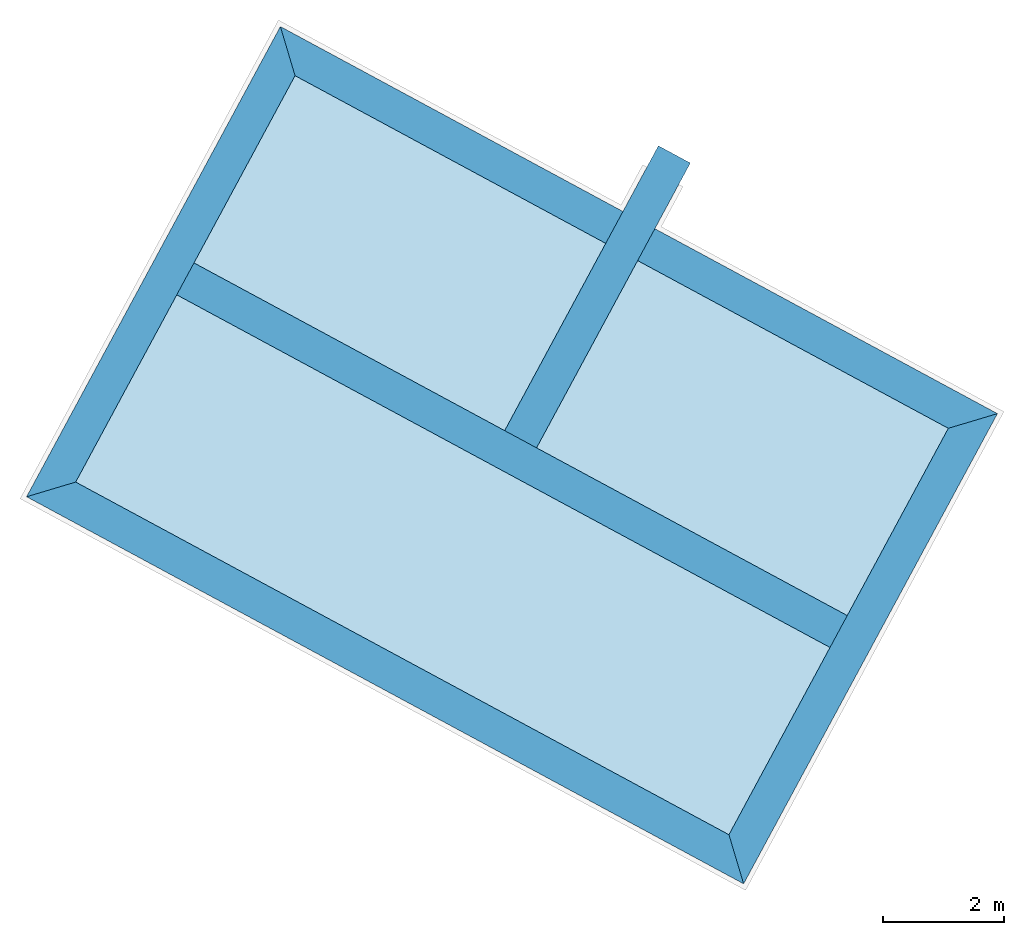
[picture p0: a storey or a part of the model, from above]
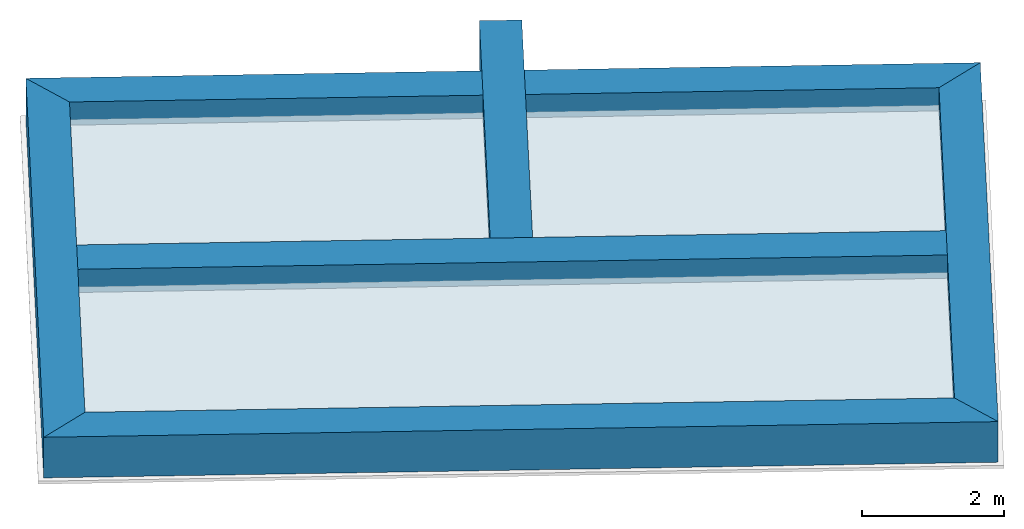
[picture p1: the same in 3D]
Properties of the parts of a building model (IFC2X3), part 1 of 3

# File
Description: ViewDefinition [CoordinationView_V2.0], Option [Elements to export: Visible elements (on all stories)], Option [Partial Structure Display: Entire Model], Option [IFC Domain: All], Option [Structural Function: All Elements], Option [Convert Grid elements: On], Option [Convert IFC Annotations and Archicad 2D elements: Off], Option [Convert 2D symbols of Doors and Windows: Off], Option [Export geometries that Participates in Collision Detection only: Off], Option [Split complex elements: Off], Option [Material Preservation: Never explode], Option [Elements in Solid Element Operations: BRep], Option [Elements with junctions: BRep], Option [IFC Model position: Survey Point and Project Origin], Option [Curtain Wall export mode: Single Element], Option [Railing export mode: Single Element], Option [Stair export mode: Single Element], Option [Properties To Export: All properties], Option [Space containment: Off], Option [Geometry to type objects: Off], Option [Element Properties: Off], Option [Building Material Properties: On], Option [Element Parameters: Off], Option [Component Parameters: Off], Option [IFC Base Quantities: Off], Option [Door Window Parameters: On], Option [IFC Space boundaries: Off], Option [Archicad Zone Categories as IFC Space classification data: Off], Option [Element Classifications: On]
File name: I:\_PROJEKT\PQRS\SIWH_18\05_Ausführungsplanung\02 CAD\06 IFC-Modelle\02 TGA\230327\SIWH_18_2302327 - neu.ifc
Time: 2023-03-27T13:30:50
Author: Kohlrausch Stephan
Organization: Gruppe GME Architekten BDA
Written by: DDS_IFC v3.0
Made in: IFC file generated by Graphisoft Archicad 26.0.0 GER FULL Windows version (IFC add-on version: 4022 GER FULL).
Authorization: Kohlrausch Stephan

# IfcProject, Neubau eines Einfamilienhauses
Description: Katrepeler Landstraße 70A

# IfcSite, Gelände
RefLatitude: 52, 31, 0, 0; RefLongitude: 13, 24, 0, 0; RefElevation: 4.65 m

# IfcBuildingStorey (5)
In: Gebäude
Name | Elevation (m)
Erdgeschoss | 0
Staffelgeschoss | 4.55
Gründung | -3.68
Dachaufsicht | 7.905
Kellergeschoss | -2.98

# IfcBuildingElementProxy: 1-Flügelfenster 22, Fenster-016
In: Kellergeschoss
AC_Pset_RenovationAndPhasing - Renovation Status: Existing

# IfcBuildingElementProxy: ALLGEMEIN - BAUTEIL (404)
In: Staffelgeschoss
Material: ALLGEMEIN - BAUTEIL
Material Properties - ALLGEMEIN - BAUTEIL, ThermalConductivity: 0.13; ALLGEMEIN - BAUTEIL, SpecificHeatCapacity: 1600 J/kg/K; ALLGEMEIN - BAUTEIL, MassDensity: 500 kg/m3; ALLGEMEIN - BAUTEIL, Embodied Energy: 13.1 (MJ/kg); ALLGEMEIN - BAUTEIL, Embodied Carbon: 0.64 (kgCO₂/kg); ALLGEMEIN - BAUTEIL, Name: ALLGEMEIN - BAUTEIL; ALLGEMEIN - BAUTEIL, Participates in Collision Detection: yes
AC_Pset_RenovationAndPhasing - Renovation Status: Existing

# IfcBuildingElementProxy: ALLGEMEIN - BAUTEIL 50 (3)
In: Staffelgeschoss
Material: ALLGEMEIN - BAUTEIL
AC_Pset_RenovationAndPhasing - Renovation Status: Existing
Material Properties - ALLGEMEIN - BAUTEIL, ThermalConductivity: 0.13; ALLGEMEIN - BAUTEIL, SpecificHeatCapacity: 1600 J/kg/K; ALLGEMEIN - BAUTEIL, MassDensity: 500 kg/m3; ALLGEMEIN - BAUTEIL, Embodied Energy: 13.1 (MJ/kg); ALLGEMEIN - BAUTEIL, Embodied Carbon: 0.64 (kgCO₂/kg); ALLGEMEIN - BAUTEIL, Name: ALLGEMEIN - BAUTEIL; ALLGEMEIN - BAUTEIL, Participates in Collision Detection: yes
Name
I-Wand038
I-Wand039
I-Wand040

# IfcBuildingElementProxy: ALLGEMEIN - BAUTEIL 520, Decke003
In: Erdgeschoss
Material: ALLGEMEIN - BAUTEIL
AC_Pset_RenovationAndPhasing - Renovation Status: Existing
Material Properties - ALLGEMEIN - BAUTEIL, ThermalConductivity: 0.13; ALLGEMEIN - BAUTEIL, SpecificHeatCapacity: 1600 J/kg/K; ALLGEMEIN - BAUTEIL, MassDensity: 500 kg/m3; ALLGEMEIN - BAUTEIL, Embodied Energy: 13.1 (MJ/kg); ALLGEMEIN - BAUTEIL, Embodied Carbon: 0.64 (kgCO₂/kg); ALLGEMEIN - BAUTEIL, Name: ALLGEMEIN - BAUTEIL; ALLGEMEIN - BAUTEIL, Participates in Collision Detection: yes

# IfcBuildingElementProxy: ALLGEMEIN - NIEDRIGE PRIORITÄT 100 (5)
In: Erdgeschoss
Material: ALLGEMEIN - NIEDRIGE PRIORITÄT
AC_Pset_RenovationAndPhasing - Renovation Status: Existing
Material Properties - ALLGEMEIN - NIEDRIGE PRIORITÄT, ThermalConductivity: 0; ALLGEMEIN - NIEDRIGE PRIORITÄT, SpecificHeatCapacity: 0 J/kg/K; ALLGEMEIN - NIEDRIGE PRIORITÄT, MassDensity: 0 kg/m3; ALLGEMEIN - NIEDRIGE PRIORITÄT, Embodied Energy: 0 (MJ/kg); ALLGEMEIN - NIEDRIGE PRIORITÄT, Embodied Carbon: 0 (kgCO₂/kg); ALLGEMEIN - NIEDRIGE PRIORITÄT, Name: ALLGEMEIN - NIEDRIGE PRIORITÄT; ALLGEMEIN - NIEDRIGE PRIORITÄT, Participates in Collision Detection: yes
Name
Decke043
Decke045
Decke047
Decke048
Decke049

# IfcBuildingElementProxy: ALLGEMEIN - NIEDRIGE PRIORITÄT 150, Decke051
In: Erdgeschoss
Material: ALLGEMEIN - NIEDRIGE PRIORITÄT
Material Properties - ALLGEMEIN - NIEDRIGE PRIORITÄT, ThermalConductivity: 0; ALLGEMEIN - NIEDRIGE PRIORITÄT, SpecificHeatCapacity: 0 J/kg/K; ALLGEMEIN - NIEDRIGE PRIORITÄT, MassDensity: 0 kg/m3; ALLGEMEIN - NIEDRIGE PRIORITÄT, Embodied Energy: 0 (MJ/kg); ALLGEMEIN - NIEDRIGE PRIORITÄT, Embodied Carbon: 0 (kgCO₂/kg); ALLGEMEIN - NIEDRIGE PRIORITÄT, Name: ALLGEMEIN - NIEDRIGE PRIORITÄT; ALLGEMEIN - NIEDRIGE PRIORITÄT, Participates in Collision Detection: yes
AC_Pset_RenovationAndPhasing - Renovation Status: Existing

# IfcBuildingElementProxy: ALLGEMEIN - NIEDRIGE PRIORITÄT 182 (2)
In: Erdgeschoss
Material: ALLGEMEIN - NIEDRIGE PRIORITÄT
AC_Pset_RenovationAndPhasing - Renovation Status: Existing
Material Properties - ALLGEMEIN - NIEDRIGE PRIORITÄT, ThermalConductivity: 0; ALLGEMEIN - NIEDRIGE PRIORITÄT, SpecificHeatCapacity: 0 J/kg/K; ALLGEMEIN - NIEDRIGE PRIORITÄT, MassDensity: 0 kg/m3; ALLGEMEIN - NIEDRIGE PRIORITÄT, Embodied Energy: 0 (MJ/kg); ALLGEMEIN - NIEDRIGE PRIORITÄT, Embodied Carbon: 0 (kgCO₂/kg); ALLGEMEIN - NIEDRIGE PRIORITÄT, Name: ALLGEMEIN - NIEDRIGE PRIORITÄT; ALLGEMEIN - NIEDRIGE PRIORITÄT, Participates in Collision Detection: yes
Name
Decke031
Decke042

# IfcBuildingElementProxy: ALLGEMEIN - NIEDRIGE PRIORITÄT 50 (3)
In: Erdgeschoss
Material: ALLGEMEIN - NIEDRIGE PRIORITÄT
AC_Pset_RenovationAndPhasing - Renovation Status: Existing
Material Properties - ALLGEMEIN - NIEDRIGE PRIORITÄT, ThermalConductivity: 0; ALLGEMEIN - NIEDRIGE PRIORITÄT, SpecificHeatCapacity: 0 J/kg/K; ALLGEMEIN - NIEDRIGE PRIORITÄT, MassDensity: 0 kg/m3; ALLGEMEIN - NIEDRIGE PRIORITÄT, Embodied Energy: 0 (MJ/kg); ALLGEMEIN - NIEDRIGE PRIORITÄT, Embodied Carbon: 0 (kgCO₂/kg); ALLGEMEIN - NIEDRIGE PRIORITÄT, Name: ALLGEMEIN - NIEDRIGE PRIORITÄT; ALLGEMEIN - NIEDRIGE PRIORITÄT, Participates in Collision Detection: yes
Name
Decke044
Decke046
Decke050

# IfcBuildingElementProxy: BO | Dämmung 8+Folie+Estrich 7+Fliese 0,5 | 16cm 170 (8)
In: Staffelgeschoss
AC_Pset_RenovationAndPhasing - Renovation Status: Existing
Material Properties - Dämmung, hart EPS, ThermalConductivity: 0.042; Dämmung, hart EPS, SpecificHeatCapacity: 1450 J/kg/K; Dämmung, hart EPS, MassDensity: 15 kg/m3; Dämmung, hart EPS, Embodied Energy: 76 (MJ/kg); Dämmung, hart EPS, Embodied Carbon: 3.18 (kgCO₂/kg); Dämmung, hart EPS, Name: Dämmung, hart EPS; Dämmung, hart EPS, Participates in Collision Detection: yes; Estrich, ThermalConductivity: 0.8; Estrich, SpecificHeatCapacity: 800 J/kg/K; Estrich, MassDensity: 2300 kg/m3; Estrich, Embodied Energy: 0.92 (MJ/kg); Estrich, Embodied Carbon: 0.15 (kgCO₂/kg); Estrich, Name: Estrich; Estrich, Participates in Collision Detection: yes; Kleber, ThermalConductivity: 0.8; Kleber, SpecificHeatCapacity: 800 J/kg/K; Kleber, MassDensity: 2300 kg/m3; Kleber, Embodied Energy: 0.92 (MJ/kg); Kleber, Embodied Carbon: 0.15 (kgCO₂/kg); Kleber, Name: Kleber; Kleber, Participates in Collision Detection: yes; Beton, Leichtbeton, ThermalConductivity: 0.12; Beton, Leichtbeton, SpecificHeatCapacity: 800 J/kg/K; Beton, Leichtbeton, MassDensity: 450 kg/m3; Beton, Leichtbeton, Embodied Energy: 6.2 (MJ/kg); Beton, Leichtbeton, Embodied Carbon: 0.46 (kgCO₂/kg); Beton, Leichtbeton, Name: Beton, Leichtbeton; Beton, Leichtbeton, Participates in Collision Detection: yes
Name | Material
Decke028 | Dämmung, hart EPS, Sperrschicht, Folie, Estrich, Kleber, Beton, Leichtbeton | Material Properties - Sperrschicht, Folie, ThermalConductivity: 0.14; Sperrschicht, Folie, SpecificHeatCapacity: 1000 J/kg/K; Sperrschicht, Folie, MassDensity: 1200 kg/m3; Sperrschicht, Folie, Embodied Energy: 77.2 (MJ/kg); Sperrschicht, Folie, Embodied Carbon: 3.1 (kgCO₂/kg); Sperrschicht, Folie, Name: Sperrschicht, Folie; Sperrschicht, Folie, Participates in Collision Detection: yes
Decke029 | Beton, Leichtbeton, Kleber, Estrich, Dämmung, hart EPS
Decke041 | Beton, Leichtbeton, Kleber, Estrich, Dämmung, hart EPS
Decke055 | Beton, Leichtbeton, Kleber, Estrich, Dämmung, hart EPS
Decke056 | Beton, Leichtbeton, Kleber, Estrich, Dämmung, hart EPS
Decke057 | Beton, Leichtbeton, Kleber, Estrich, Dämmung, hart EPS
Decke058 | Beton, Leichtbeton, Kleber, Estrich, Dämmung, hart EPS
Decke040 | Dämmung, hart EPS, Sperrschicht, Folie, Estrich, Kleber, Beton, Leichtbeton | Material Properties - Sperrschicht, Folie, ThermalConductivity: 0.14; Sperrschicht, Folie, SpecificHeatCapacity: 1000 J/kg/K; Sperrschicht, Folie, MassDensity: 1200 kg/m3; Sperrschicht, Folie, Embodied Energy: 77.2 (MJ/kg); Sperrschicht, Folie, Embodied Carbon: 3.1 (kgCO₂/kg); Sperrschicht, Folie, Name: Sperrschicht, Folie; Sperrschicht, Folie, Participates in Collision Detection: yes

# IfcBuildingElementProxy: Beton, Stahlbeton C30/35 500 (2)
In: Kellergeschoss
Material: Beton, Stahlbeton C30/35
AC_Pset_RenovationAndPhasing - Renovation Status: Existing
Material Properties - Beton, Stahlbeton C30/35, ThermalConductivity: 1.35; Beton, Stahlbeton C30/35, SpecificHeatCapacity: 1000 J/kg/K; Beton, Stahlbeton C30/35, MassDensity: 2000 kg/m3; Beton, Stahlbeton C30/35, Embodied Energy: 0.78 (MJ/kg); Beton, Stahlbeton C30/35, Embodied Carbon: 0.113 (kgCO₂/kg); Beton, Stahlbeton C30/35, Name: Beton, Stahlbeton C30/35; Beton, Stahlbeton C30/35, Participates in Collision Detection: yes
Name
A-Wand038
A-Wand037

# IfcBuildingElementProxy: Beton, WU-Beton 10 (3)
In: Erdgeschoss
Material: Beton, WU-Beton
AC_Pset_RenovationAndPhasing - Renovation Status: Existing
Material Properties - Beton, WU-Beton, ThermalConductivity: 1.7; Beton, WU-Beton, SpecificHeatCapacity: 800 J/kg/K; Beton, WU-Beton, MassDensity: 2300 kg/m3; Beton, WU-Beton, Embodied Energy: 0.88 (MJ/kg); Beton, WU-Beton, Embodied Carbon: 0.132 (kgCO₂/kg); Beton, WU-Beton, Name: Beton, WU-Beton; Beton, WU-Beton, Participates in Collision Detection: yes
Name
Wand-016
Wand-015
Wand-017

# IfcBuildingElementProxy: Eingangstür 02 1 22, Tür-017
In: Erdgeschoss
AC_Pset_RenovationAndPhasing - Renovation Status: Existing

# IfcBuildingElementProxy: Fassadentyp (12)
AC_Pset_RenovationAndPhasing - Renovation Status: Existing
Material Properties - Glas, Normalglas-50% durchlässig, ThermalConductivity: 1.4; Glas, Normalglas-50% durchlässig, SpecificHeatCapacity: 750 J/kg/K; Glas, Normalglas-50% durchlässig, MassDensity: 2200 kg/m3; Glas, Normalglas-50% durchlässig, Embodied Energy: 0.85 (MJ/kg); Glas, Normalglas-50% durchlässig, Embodied Carbon: 0.02 (kgCO₂/kg); Glas, Normalglas-50% durchlässig, Name: Glas, Normalglas-50% durchlässig; Glas, Normalglas-50% durchlässig, Participates in Collision Detection: yes; Metall, Stahl lackiert, ThermalConductivity: 50; Metall, Stahl lackiert, SpecificHeatCapacity: 450 J/kg/K; Metall, Stahl lackiert, MassDensity: 7800 kg/m3; Metall, Stahl lackiert, Embodied Energy: 20.1 (MJ/kg); Metall, Stahl lackiert, Embodied Carbon: 1.46 (kgCO₂/kg); Metall, Stahl lackiert, Name: Metall, Stahl lackiert; Metall, Stahl lackiert, Participates in Collision Detection: yes
Name | In | Material | Metall, Aluminium, ThermalConductivity | Metall, Aluminium, SpecificHeatCapacity (J/kg/K) | Metall, Aluminium, MassDensity (kg/m3) | Metall, Aluminium, Embodied Energy | Metall, Aluminium, Embodied Carbon | Metall, Aluminium, Name | Metall, Aluminium, Participates in Collision Detection
Fassade-006 | Erdgeschoss | Glas, Normalglas-50% durchlässig (2), Metall, Stahl lackiert (8), Metall, Aluminium (2) | 160 | 880 | 2800 | 155 (MJ/kg) | 9.16 (kgCO₂/kg) | Metall, Aluminium | yes
Fassade-006 | Erdgeschoss | Metall, Aluminium (3), Glas, Normalglas-50% durchlässig (2), Metall, Edelstahl, Metall, Stahl lackiert (16) | 160 | 880 | 2800 | 155 (MJ/kg) | 9.16 (kgCO₂/kg) | Metall, Aluminium | yes | Material Properties - Metall, Edelstahl, ThermalConductivity: 17; Metall, Edelstahl, SpecificHeatCapacity: 460 J/kg/K; Metall, Edelstahl, MassDensity: 7900 kg/m3; Metall, Edelstahl, Embodied Energy: 56.7 (MJ/kg); Metall, Edelstahl, Embodied Carbon: 6.15 (kgCO₂/kg); Metall, Edelstahl, Name: Metall, Edelstahl; Metall, Edelstahl, Participates in Collision Detection: yes
Fassade-007 | Erdgeschoss | Glas, Normalglas-50% durchlässig (3), Metall, Aluminium (5), Metall, Edelstahl, Metall, Stahl lackiert (18), Dämmung, hart EPS (2) | 160 | 880 | 2800 | 155 (MJ/kg) | 9.16 (kgCO₂/kg) | Metall, Aluminium | yes | Material Properties - Metall, Edelstahl, ThermalConductivity: 17; Metall, Edelstahl, SpecificHeatCapacity: 460 J/kg/K; Metall, Edelstahl, MassDensity: 7900 kg/m3; Metall, Edelstahl, Embodied Energy: 56.7 (MJ/kg); Metall, Edelstahl, Embodied Carbon: 6.15 (kgCO₂/kg); Metall, Edelstahl, Name: Metall, Edelstahl; Metall, Edelstahl, Participates in Collision Detection: yes; Dämmung, hart EPS, ThermalConductivity: 0.042; Dämmung, hart EPS, SpecificHeatCapacity: 1450 J/kg/K; Dämmung, hart EPS, MassDensity: 15 kg/m3; Dämmung, hart EPS, Embodied Energy: 76 (MJ/kg); Dämmung, hart EPS, Embodied Carbon: 3.18 (kgCO₂/kg); Dämmung, hart EPS, Name: Dämmung, hart EPS; Dämmung, hart EPS, Participates in Collision Detection: yes
Fassade-008 | Erdgeschoss | Glas, Normalglas-50% durchlässig (4), Metall, Stahl lackiert (14), Metall, Aluminium (5), Gummi, Dämmung, hart EPS | 160 | 880 | 2800 | 155 (MJ/kg) | 9.16 (kgCO₂/kg) | Metall, Aluminium | yes | Material Properties - Dämmung, hart EPS, ThermalConductivity: 0.042; Dämmung, hart EPS, SpecificHeatCapacity: 1450 J/kg/K; Dämmung, hart EPS, MassDensity: 15 kg/m3; Dämmung, hart EPS, Embodied Energy: 76 (MJ/kg); Dämmung, hart EPS, Embodied Carbon: 3.18 (kgCO₂/kg); Dämmung, hart EPS, Name: Dämmung, hart EPS; Dämmung, hart EPS, Participates in Collision Detection: yes; Gummi, ThermalConductivity: 0.17; Gummi, SpecificHeatCapacity: 1400 J/kg/K; Gummi, MassDensity: 1200 kg/m3; Gummi, Embodied Energy: 110 (MJ/kg); Gummi, Embodied Carbon: 3.8 (kgCO₂/kg); Gummi, Name: Gummi; Gummi, Participates in Collision Detection: yes
Fassade-006 | Erdgeschoss | Glas, Normalglas-50% durchlässig (3), Metall, Stahl lackiert (18), Metall, Aluminium (4) | 160 | 880 | 2800 | 155 (MJ/kg) | 9.16 (kgCO₂/kg) | Metall, Aluminium | yes
Fassade-007 | Erdgeschoss | Metall, Aluminium (4), Glas, Normalglas-50% durchlässig (2), Metall, Edelstahl (2), Dämmung, hart EPS (2), Metall, Stahl lackiert (14) | 160 | 880 | 2800 | 155 (MJ/kg) | 9.16 (kgCO₂/kg) | Metall, Aluminium | yes | Material Properties - Metall, Edelstahl, ThermalConductivity: 17; Metall, Edelstahl, SpecificHeatCapacity: 460 J/kg/K; Metall, Edelstahl, MassDensity: 7900 kg/m3; Metall, Edelstahl, Embodied Energy: 56.7 (MJ/kg); Metall, Edelstahl, Embodied Carbon: 6.15 (kgCO₂/kg); Metall, Edelstahl, Name: Metall, Edelstahl; Metall, Edelstahl, Participates in Collision Detection: yes; Dämmung, hart EPS, ThermalConductivity: 0.042; Dämmung, hart EPS, SpecificHeatCapacity: 1450 J/kg/K; Dämmung, hart EPS, MassDensity: 15 kg/m3; Dämmung, hart EPS, Embodied Energy: 76 (MJ/kg); Dämmung, hart EPS, Embodied Carbon: 3.18 (kgCO₂/kg); Dämmung, hart EPS, Name: Dämmung, hart EPS; Dämmung, hart EPS, Participates in Collision Detection: yes
Fassade-008 | Staffelgeschoss | Glas, Normalglas-50% durchlässig (27), Metall, Aluminium (28), Metall, Edelstahl, Metall, Stahl lackiert (74), Dämmung, hart EPS (2) | 160 | 880 | 2800 | 155 (MJ/kg) | 9.16 (kgCO₂/kg) | Metall, Aluminium | yes | Material Properties - Metall, Edelstahl, ThermalConductivity: 17; Metall, Edelstahl, SpecificHeatCapacity: 460 J/kg/K; Metall, Edelstahl, MassDensity: 7900 kg/m3; Metall, Edelstahl, Embodied Energy: 56.7 (MJ/kg); Metall, Edelstahl, Embodied Carbon: 6.15 (kgCO₂/kg); Metall, Edelstahl, Name: Metall, Edelstahl; Metall, Edelstahl, Participates in Collision Detection: yes; Dämmung, hart EPS, ThermalConductivity: 0.042; Dämmung, hart EPS, SpecificHeatCapacity: 1450 J/kg/K; Dämmung, hart EPS, MassDensity: 15 kg/m3; Dämmung, hart EPS, Embodied Energy: 76 (MJ/kg); Dämmung, hart EPS, Embodied Carbon: 3.18 (kgCO₂/kg); Dämmung, hart EPS, Name: Dämmung, hart EPS; Dämmung, hart EPS, Participates in Collision Detection: yes
3 x Fassade-006 | Staffelgeschoss | Glas, Normalglas-50% durchlässig, Metall, Stahl lackiert (6)
Fassade-008 | Staffelgeschoss | Glas, Normalglas-50% durchlässig (2), Metall, Aluminium (2), Metall, Edelstahl, Metall, Stahl lackiert (15), Dämmung, hart EPS | 160 | 880 | 2800 | 155 (MJ/kg) | 9.16 (kgCO₂/kg) | Metall, Aluminium | yes | Material Properties - Metall, Edelstahl, ThermalConductivity: 17; Metall, Edelstahl, SpecificHeatCapacity: 460 J/kg/K; Metall, Edelstahl, MassDensity: 7900 kg/m3; Metall, Edelstahl, Embodied Energy: 56.7 (MJ/kg); Metall, Edelstahl, Embodied Carbon: 6.15 (kgCO₂/kg); Metall, Edelstahl, Name: Metall, Edelstahl; Metall, Edelstahl, Participates in Collision Detection: yes; Dämmung, hart EPS, ThermalConductivity: 0.042; Dämmung, hart EPS, SpecificHeatCapacity: 1450 J/kg/K; Dämmung, hart EPS, MassDensity: 15 kg/m3; Dämmung, hart EPS, Embodied Energy: 76 (MJ/kg); Dämmung, hart EPS, Embodied Carbon: 3.18 (kgCO₂/kg); Dämmung, hart EPS, Name: Dämmung, hart EPS; Dämmung, hart EPS, Participates in Collision Detection: yes
Fassade-006 | Staffelgeschoss | Glas, Normalglas-50% durchlässig (3), Metall, Aluminium (3), Metall, Edelstahl, Metall, Stahl lackiert (15), Dämmung, hart EPS | 160 | 880 | 2800 | 155 (MJ/kg) | 9.16 (kgCO₂/kg) | Metall, Aluminium | yes | Material Properties - Metall, Edelstahl, ThermalConductivity: 17; Metall, Edelstahl, SpecificHeatCapacity: 460 J/kg/K; Metall, Edelstahl, MassDensity: 7900 kg/m3; Metall, Edelstahl, Embodied Energy: 56.7 (MJ/kg); Metall, Edelstahl, Embodied Carbon: 6.15 (kgCO₂/kg); Metall, Edelstahl, Name: Metall, Edelstahl; Metall, Edelstahl, Participates in Collision Detection: yes; Dämmung, hart EPS, ThermalConductivity: 0.042; Dämmung, hart EPS, SpecificHeatCapacity: 1450 J/kg/K; Dämmung, hart EPS, MassDensity: 15 kg/m3; Dämmung, hart EPS, Embodied Energy: 76 (MJ/kg); Dämmung, hart EPS, Embodied Carbon: 3.18 (kgCO₂/kg); Dämmung, hart EPS, Name: Dämmung, hart EPS; Dämmung, hart EPS, Participates in Collision Detection: yes

# IfcBuildingElementProxy: Flachbildfernseher 22, Objekt-0064
In: Erdgeschoss
AC_Pset_RenovationAndPhasing - Renovation Status: Existing

# IfcBuildingElementProxy: Geländerart (5)
In: Staffelgeschoss
AC_Pset_RenovationAndPhasing - Renovation Status: Existing
Material Properties - Metall, Stahl lackiert, ThermalConductivity: 50; Metall, Stahl lackiert, SpecificHeatCapacity: 450 J/kg/K; Metall, Stahl lackiert, MassDensity: 7800 kg/m3; Metall, Stahl lackiert, Embodied Energy: 20.1 (MJ/kg); Metall, Stahl lackiert, Embodied Carbon: 1.46 (kgCO₂/kg); Metall, Stahl lackiert, Name: Metall, Stahl lackiert; Metall, Stahl lackiert, Participates in Collision Detection: yes
Name | Material | Glas, Normalglas-50% durchlässig, ThermalConductivity | Glas, Normalglas-50% durchlässig, SpecificHeatCapacity (J/kg/K) | Glas, Normalglas-50% durchlässig, MassDensity (kg/m3) | Glas, Normalglas-50% durchlässig, Embodied Energy | Glas, Normalglas-50% durchlässig, Embodied Carbon | Glas, Normalglas-50% durchlässig, Name | Glas, Normalglas-50% durchlässig, Participates in Collision Detection
4 x Geländer-005 | Metall, Stahl lackiert (5), Glas, Normalglas-50% durchlässig | 1.4 | 750 | 2200 | 0.85 (MJ/kg) | 0.02 (kgCO₂/kg) | Glas, Normalglas-50% durchlässig | yes
Geländer-005 | Metall, Stahl lackiert (5), Glas, Normalglas | Material Properties - Glas, Normalglas, ThermalConductivity: 1.4; Glas, Normalglas, SpecificHeatCapacity: 750 J/kg/K; Glas, Normalglas, MassDensity: 2200 kg/m3; Glas, Normalglas, Embodied Energy: 0.85 (MJ/kg); Glas, Normalglas, Embodied Carbon: 0.02 (kgCO₂/kg); Glas, Normalglas, Name: Glas, Normalglas; Glas, Normalglas, Participates in Collision Detection: yes

# IfcBuildingElementProxy: Gipskarton 15 (3)
Material: Gipskarton
AC_Pset_RenovationAndPhasing - Renovation Status: Existing
Material Properties - Gipskarton, ThermalConductivity: 0.25; Gipskarton, SpecificHeatCapacity: 1000 J/kg/K; Gipskarton, MassDensity: 900 kg/m3; Gipskarton, Embodied Energy: 6.75 (MJ/kg); Gipskarton, Embodied Carbon: 0.39 (kgCO₂/kg); Gipskarton, Name: Gipskarton; Gipskarton, Participates in Collision Detection: yes
Name | In
Decke001 | Erdgeschoss
Decke007 | Erdgeschoss
Decke002 | Staffelgeschoss

# IfcBuildingElementProxy: Glas, Normalglas 10 (6)
Material: Glas, Normalglas
AC_Pset_RenovationAndPhasing - Renovation Status: Existing
Material Properties - Glas, Normalglas, ThermalConductivity: 1.4; Glas, Normalglas, SpecificHeatCapacity: 750 J/kg/K; Glas, Normalglas, MassDensity: 2200 kg/m3; Glas, Normalglas, Embodied Energy: 0.85 (MJ/kg); Glas, Normalglas, Embodied Carbon: 0.02 (kgCO₂/kg); Glas, Normalglas, Name: Glas, Normalglas; Glas, Normalglas, Participates in Collision Detection: yes
Name | In
I-Wand033 | Erdgeschoss
I-Wand035 | Erdgeschoss
I-Wand036 | Erdgeschoss
I-Wand031 | Staffelgeschoss
I-Wand032 | Staffelgeschoss
I-Wand037 | Staffelgeschoss

# IfcBuildingElementProxy: Holz, Treppenstufe 966, Decke000
In: Erdgeschoss
Material: Holz, Treppenstufe
AC_Pset_RenovationAndPhasing - Renovation Status: Existing
Material Properties - Holz, Treppenstufe, ThermalConductivity: 0.09; Holz, Treppenstufe, SpecificHeatCapacity: 1600 J/kg/K; Holz, Treppenstufe, MassDensity: 300 kg/m3; Holz, Treppenstufe, Embodied Energy: 11.9 (MJ/kg); Holz, Treppenstufe, Embodied Carbon: 0.52 (kgCO₂/kg); Holz, Treppenstufe, Name: Holz, Treppenstufe; Holz, Treppenstufe, Participates in Collision Detection: yes

# IfcBuildingElementProxy: Kamin freistehend 22 (2)
In: Staffelgeschoss
AC_Pset_RenovationAndPhasing - Renovation Status: Existing

# IfcBuildingElementProxy: Kleiderschrank 22 (2)
In: Erdgeschoss
AC_Pset_RenovationAndPhasing - Renovation Status: Existing

# IfcBuildingElementProxy: MW Kalksandstein 175, I-Wand017
In: Staffelgeschoss
Material: MW Kalksandstein
Material Properties - MW Kalksandstein, ThermalConductivity: 0.93; MW Kalksandstein, SpecificHeatCapacity: 840 J/kg/K; MW Kalksandstein, MassDensity: 1800 kg/m3; MW Kalksandstein, Embodied Energy: 1.2 (MJ/kg); MW Kalksandstein, Embodied Carbon: 0.07 (kgCO₂/kg); MW Kalksandstein, Name: MW Kalksandstein; MW Kalksandstein, Participates in Collision Detection: yes
AC_Pset_RenovationAndPhasing - Renovation Status: Existing

# IfcBuildingElementProxy: MW Kalksandstein 500, A-Wand036
In: Kellergeschoss
Material: MW Kalksandstein
AC_Pset_RenovationAndPhasing - Renovation Status: Existing
Material Properties - MW Kalksandstein, ThermalConductivity: 0.93; MW Kalksandstein, SpecificHeatCapacity: 840 J/kg/K; MW Kalksandstein, MassDensity: 1800 kg/m3; MW Kalksandstein, Embodied Energy: 1.2 (MJ/kg); MW Kalksandstein, Embodied Carbon: 0.07 (kgCO₂/kg); MW Kalksandstein, Name: MW Kalksandstein; MW Kalksandstein, Participates in Collision Detection: yes

# IfcBuildingElementProxy: Metall, Edelstahl D152 (10)
Material: Metall, Edelstahl
AC_Pset_RenovationAndPhasing - Renovation Status: Existing
Material Properties - Metall, Edelstahl, ThermalConductivity: 17; Metall, Edelstahl, SpecificHeatCapacity: 460 J/kg/K; Metall, Edelstahl, MassDensity: 7900 kg/m3; Metall, Edelstahl, Embodied Energy: 56.7 (MJ/kg); Metall, Edelstahl, Embodied Carbon: 6.15 (kgCO₂/kg); Metall, Edelstahl, Name: Metall, Edelstahl; Metall, Edelstahl, Participates in Collision Detection: yes
Name | In
5 x Stütze-003 | Erdgeschoss
5 x Stütze-003 | Staffelgeschoss

# IfcBuildingElementProxy: Metall, Edelstahl-Stütze D152 (4)
In: Erdgeschoss
Material: Metall, Edelstahl-Stütze
AC_Pset_RenovationAndPhasing - Renovation Status: Existing
Material Properties - Metall, Edelstahl-Stütze, ThermalConductivity: 17; Metall, Edelstahl-Stütze, SpecificHeatCapacity: 460 J/kg/K; Metall, Edelstahl-Stütze, MassDensity: 7900 kg/m3; Metall, Edelstahl-Stütze, Embodied Energy: 56.7 (MJ/kg); Metall, Edelstahl-Stütze, Embodied Carbon: 6.15 (kgCO₂/kg); Metall, Edelstahl-Stütze, Name: Metall, Edelstahl-Stütze; Metall, Edelstahl-Stütze, Participates in Collision Detection: yes

# IfcBuildingElementProxy: Metall, Stahl lackiert D152 (8)
In: Staffelgeschoss
Material: Metall, Stahl lackiert
AC_Pset_RenovationAndPhasing - Renovation Status: Existing
Material Properties - Metall, Stahl lackiert, ThermalConductivity: 50; Metall, Stahl lackiert, SpecificHeatCapacity: 450 J/kg/K; Metall, Stahl lackiert, MassDensity: 7800 kg/m3; Metall, Stahl lackiert, Embodied Energy: 20.1 (MJ/kg); Metall, Stahl lackiert, Embodied Carbon: 1.46 (kgCO₂/kg); Metall, Stahl lackiert, Name: Metall, Stahl lackiert; Metall, Stahl lackiert, Participates in Collision Detection: yes
Name
4 x Stütze-003
4 x Stütze-004

# IfcBuildingElementProxy: Schiebetür 02 1 22 (2)
In: Staffelgeschoss
AC_Pset_RenovationAndPhasing - Renovation Status: Existing

# IfcBuildingElementProxy: Schiebetür 02 1-Fl 26, Tür-017
In: Staffelgeschoss
AC_Pset_RenovationAndPhasing - Renovation Status: Existing

# IfcBuildingElementProxy: Schreibtisch 22, Objekt-0068
In: Staffelgeschoss
AC_Pset_RenovationAndPhasing - Renovation Status: Existing

# IfcBuildingElementProxy: Sektionaltor 22, Tür-016
In: Erdgeschoss
AC_Pset_RenovationAndPhasing - Renovation Status: Existing

# IfcBuildingElementProxy: Sofa Set 01 17 (4)
In: Erdgeschoss
AC_Pset_RenovationAndPhasing - Renovation Status: Existing

# IfcBuildingElementProxy: Teleskoptür 22 (2)
AC_Pset_RenovationAndPhasing - Renovation Status: Existing
Name | In
Tür-011 | Erdgeschoss
Tür-011 | Staffelgeschoss

# IfcBuildingElementProxy: Treppentyp (2)
AC_Pset_RenovationAndPhasing - Renovation Status: Existing
Name | In | Material
Treppe-001 | Kellergeschoss | ALLGEMEIN - BAUTEIL | Material Properties - ALLGEMEIN - BAUTEIL, ThermalConductivity: 0.13; ALLGEMEIN - BAUTEIL, SpecificHeatCapacity: 1600 J/kg/K; ALLGEMEIN - BAUTEIL, MassDensity: 500 kg/m3; ALLGEMEIN - BAUTEIL, Embodied Energy: 13.1 (MJ/kg); ALLGEMEIN - BAUTEIL, Embodied Carbon: 0.64 (kgCO₂/kg); ALLGEMEIN - BAUTEIL, Name: ALLGEMEIN - BAUTEIL; ALLGEMEIN - BAUTEIL, Participates in Collision Detection: yes
Treppe-001 | Erdgeschoss | Metall, Stahl lackiert | Material Properties - Metall, Stahl lackiert, ThermalConductivity: 50; Metall, Stahl lackiert, SpecificHeatCapacity: 450 J/kg/K; Metall, Stahl lackiert, MassDensity: 7800 kg/m3; Metall, Stahl lackiert, Embodied Energy: 20.1 (MJ/kg); Metall, Stahl lackiert, Embodied Carbon: 1.46 (kgCO₂/kg); Metall, Stahl lackiert, Name: Metall, Stahl lackiert; Metall, Stahl lackiert, Participates in Collision Detection: yes

# IfcBuildingElementProxy: Unterschrank Mehrfach-Schublade 22 (4)
In: Erdgeschoss
AC_Pset_RenovationAndPhasing - Renovation Status: Existing

# IfcBuildingElementProxy: WI | KS 11,5+1-seitig Putz 1,5 | 13cm 130 (3)
In: Staffelgeschoss
Material: Verputz, Gips, MW Kalksandstein
AC_Pset_RenovationAndPhasing - Renovation Status: Existing
Material Properties - Verputz, Gips, ThermalConductivity: 0.4; Verputz, Gips, SpecificHeatCapacity: 1000 J/kg/K; Verputz, Gips, MassDensity: 1000 kg/m3; Verputz, Gips, Embodied Energy: 1.6 (MJ/kg); Verputz, Gips, Embodied Carbon: 0.11 (kgCO₂/kg); Verputz, Gips, Name: Verputz, Gips; Verputz, Gips, Participates in Collision Detection: yes; MW Kalksandstein, ThermalConductivity: 0.93; MW Kalksandstein, SpecificHeatCapacity: 840 J/kg/K; MW Kalksandstein, MassDensity: 1800 kg/m3; MW Kalksandstein, Embodied Energy: 1.2 (MJ/kg); MW Kalksandstein, Embodied Carbon: 0.07 (kgCO₂/kg); MW Kalksandstein, Name: MW Kalksandstein; MW Kalksandstein, Participates in Collision Detection: yes
Name
I-Wand018
I-Wand019
I-Wand010

# IfcBuildingElementProxy: Wasser 789, Decke026
In: Erdgeschoss
Material: Wasser
Material Properties - Wasser, ThermalConductivity: 0.6; Wasser, SpecificHeatCapacity: 4200 J/kg/K; Wasser, MassDensity: 1000 kg/m3; Wasser, Embodied Energy: 0.01 (MJ/kg); Wasser, Embodied Carbon: 0.001 (kgCO₂/kg); Wasser, Name: Wasser; Wasser, Participates in Collision Detection: no
AC_Pset_RenovationAndPhasing - Renovation Status: Existing

# IfcBuildingElementProxy: Zargentür 1-Fl 22 (12)
AC_Pset_RenovationAndPhasing - Renovation Status: Existing
Name | In
3 x Tür-017 | Kellergeschoss
6 x Tür-017 | Erdgeschoss
3 x Tür-017 | Staffelgeschoss

# IfcBuildingElementProxy: _SIWH - BO | EG 180, Decke008
In: Erdgeschoss
Material: ALLGEMEIN - BAUTEIL
AC_Pset_RenovationAndPhasing - Renovation Status: Existing
Material Properties - ALLGEMEIN - BAUTEIL, ThermalConductivity: 0.13; ALLGEMEIN - BAUTEIL, SpecificHeatCapacity: 1600 J/kg/K; ALLGEMEIN - BAUTEIL, MassDensity: 500 kg/m3; ALLGEMEIN - BAUTEIL, Embodied Energy: 13.1 (MJ/kg); ALLGEMEIN - BAUTEIL, Embodied Carbon: 0.64 (kgCO₂/kg); ALLGEMEIN - BAUTEIL, Name: ALLGEMEIN - BAUTEIL; ALLGEMEIN - BAUTEIL, Participates in Collision Detection: yes

# IfcBuildingElementProxy: _SIWH - BO | SG 190, Decke005
In: Staffelgeschoss
Material: ALLGEMEIN - BAUTEIL
Material Properties - ALLGEMEIN - BAUTEIL, ThermalConductivity: 0.13; ALLGEMEIN - BAUTEIL, SpecificHeatCapacity: 1600 J/kg/K; ALLGEMEIN - BAUTEIL, MassDensity: 500 kg/m3; ALLGEMEIN - BAUTEIL, Embodied Energy: 13.1 (MJ/kg); ALLGEMEIN - BAUTEIL, Embodied Carbon: 0.64 (kgCO₂/kg); ALLGEMEIN - BAUTEIL, Name: ALLGEMEIN - BAUTEIL; ALLGEMEIN - BAUTEIL, Participates in Collision Detection: yes
AC_Pset_RenovationAndPhasing - Renovation Status: Existing

# IfcColumn: Beton, Stahlbeton C30/35 D450 (2)
In: Erdgeschoss
Classification: Stütze / Pfeiler (Archicad Klassifizierung); Material: Beton, Stahlbeton C30/35
AC_Pset_RenovationAndPhasing - Renovation Status: Existing
Pset_ColumnCommon - IsExternal: no; LoadBearing: yes; Reference: Beton, Stahlbeton C30/35 D450
Material Properties - Beton, Stahlbeton C30/35, ThermalConductivity: 1.35; Beton, Stahlbeton C30/35, SpecificHeatCapacity: 1000 J/kg/K; Beton, Stahlbeton C30/35, MassDensity: 2000 kg/m3; Beton, Stahlbeton C30/35, Embodied Energy: 0.78 (MJ/kg); Beton, Stahlbeton C30/35, Embodied Carbon: 0.113 (kgCO₂/kg); Beton, Stahlbeton C30/35, Name: Beton, Stahlbeton C30/35; Beton, Stahlbeton C30/35, Participates in Collision Detection: yes

# IfcColumn: _SIWH - Außenstütze1 EG 2395 x 400, Stütze-004
In: Erdgeschoss
Classification: Stütze (Archicad Klassifizierung); Material: _SIWH - Beton, Stahlbeton
AC_Pset_RenovationAndPhasing - Renovation Status: Existing
Pset_ColumnCommon - IsExternal: yes; LoadBearing: yes; Reference: _SIWH - Außenstütze1 EG 2395 x 400
Material Properties - _SIWH - Beton, Stahlbeton, ThermalConductivity: 1.35; _SIWH - Beton, Stahlbeton, SpecificHeatCapacity: 1000 J/kg/K; _SIWH - Beton, Stahlbeton, MassDensity: 2000 kg/m3; _SIWH - Beton, Stahlbeton, Embodied Energy: 0.78 (MJ/kg); _SIWH - Beton, Stahlbeton, Embodied Carbon: 0.113 (kgCO₂/kg); _SIWH - Beton, Stahlbeton, Name: _SIWH - Beton, Stahlbeton; _SIWH - Beton, Stahlbeton, Participates in Collision Detection: yes

# IfcColumn: _SIWH - Beton, Stahlbeton 400 x 2200, Stütze-003
In: Erdgeschoss
Classification: Stütze (Archicad Klassifizierung); Material: _SIWH - Beton, Stahlbeton
Pset_ColumnCommon - IsExternal: yes; LoadBearing: yes; Reference: _SIWH - Beton, Stahlbeton 400 x 2200
Material Properties - _SIWH - Beton, Stahlbeton, ThermalConductivity: 1.35; _SIWH - Beton, Stahlbeton, SpecificHeatCapacity: 1000 J/kg/K; _SIWH - Beton, Stahlbeton, MassDensity: 2000 kg/m3; _SIWH - Beton, Stahlbeton, Embodied Energy: 0.78 (MJ/kg); _SIWH - Beton, Stahlbeton, Embodied Carbon: 0.113 (kgCO₂/kg); _SIWH - Beton, Stahlbeton, Name: _SIWH - Beton, Stahlbeton; _SIWH - Beton, Stahlbeton, Participates in Collision Detection: yes
AC_Pset_RenovationAndPhasing - Renovation Status: Existing

# IfcColumn: _SIWH - Beton, Stahlbeton 400 x 400 (11)
In: Erdgeschoss
Classification: Stütze (Archicad Klassifizierung); Material: _SIWH - Beton, Stahlbeton
AC_Pset_RenovationAndPhasing - Renovation Status: Existing
Pset_ColumnCommon - IsExternal: yes; LoadBearing: yes; Reference: _SIWH - Beton, Stahlbeton 400 x 400
Material Properties - _SIWH - Beton, Stahlbeton, ThermalConductivity: 1.35; _SIWH - Beton, Stahlbeton, SpecificHeatCapacity: 1000 J/kg/K; _SIWH - Beton, Stahlbeton, MassDensity: 2000 kg/m3; _SIWH - Beton, Stahlbeton, Embodied Energy: 0.78 (MJ/kg); _SIWH - Beton, Stahlbeton, Embodied Carbon: 0.113 (kgCO₂/kg); _SIWH - Beton, Stahlbeton, Name: _SIWH - Beton, Stahlbeton; _SIWH - Beton, Stahlbeton, Participates in Collision Detection: yes

# IfcCovering: Dämmung, hart Mineralwolle (6)
Classification: Dämmung (Archicad Klassifizierung); Material: Dämmung, hart Mineralwolle
Pset_CoveringCommon - Material: Dämmung, hart Mineralwolle
Material Properties - Dämmung, hart Mineralwolle, ThermalConductivity: 0.036; Dämmung, hart Mineralwolle, SpecificHeatCapacity: 840 J/kg/K; Dämmung, hart Mineralwolle, MassDensity: 115 kg/m3; Dämmung, hart Mineralwolle, Embodied Energy: 21.4 (MJ/kg); Dämmung, hart Mineralwolle, Embodied Carbon: 1.69 (kgCO₂/kg); Dämmung, hart Mineralwolle, Name: Dämmung, hart Mineralwolle; Dämmung, hart Mineralwolle, Participates in Collision Detection: yes
AC_Pset_RenovationAndPhasing - Renovation Status: Existing
Name | In
4 x Freifläche-006 | Staffelgeschoss
Freifläche-005 | Staffelgeschoss
Freifläche-004 | Dachaufsicht

# IfcCovering: _SIWH - Abgehängte Decke Arkade 25 (2)
In: Erdgeschoss
Classification: Abgehängte Decke / Deckenbekleidung (Archicad Klassifizierung); Material: _SIWH - Abgehängte Decke Arkade
Pset_CoveringCommon - Material: _SIWH - Abgehängte Decke Arkade
AC_Pset_RenovationAndPhasing - Renovation Status: Existing
Material Properties - _SIWH - Abgehängte Decke Arkade, ThermalConductivity: 0.13; _SIWH - Abgehängte Decke Arkade, SpecificHeatCapacity: 1600 J/kg/K; _SIWH - Abgehängte Decke Arkade, MassDensity: 500 kg/m3; _SIWH - Abgehängte Decke Arkade, Embodied Energy: 13.1 (MJ/kg); _SIWH - Abgehängte Decke Arkade, Embodied Carbon: 0.64 (kgCO₂/kg); _SIWH - Abgehängte Decke Arkade, Name: _SIWH - Abgehängte Decke Arkade; _SIWH - Abgehängte Decke Arkade, Participates in Collision Detection: yes
Name
Decke016
Decke015

# IfcCovering: _SIWH - Attika1 Achse3 EG 440 x 865, A-Wand054
In: Staffelgeschoss
Classification: Dämmung (Archicad Klassifizierung); Material: _SIWH - Dämmung, weich Mineralwolle, _SIWH - Dämmung, hart Mineralwolle
Pset_CoveringCommon - Material: _SIWH - Attika1 Achse3 EG
AC_Pset_RenovationAndPhasing - Renovation Status: Existing
Material Properties - _SIWH - Dämmung, weich Mineralwolle, ThermalConductivity: 0.037; _SIWH - Dämmung, weich Mineralwolle, SpecificHeatCapacity: 840 J/kg/K; _SIWH - Dämmung, weich Mineralwolle, MassDensity: 40 kg/m3; _SIWH - Dämmung, weich Mineralwolle, Embodied Energy: 14.3 (MJ/kg); _SIWH - Dämmung, weich Mineralwolle, Embodied Carbon: 1.08 (kgCO₂/kg); _SIWH - Dämmung, weich Mineralwolle, Name: _SIWH - Dämmung, weich Mineralwolle; _SIWH - Dämmung, weich Mineralwolle, Participates in Collision Detection: yes; _SIWH - Dämmung, hart Mineralwolle, ThermalConductivity: 0.036; _SIWH - Dämmung, hart Mineralwolle, SpecificHeatCapacity: 840 J/kg/K; _SIWH - Dämmung, hart Mineralwolle, MassDensity: 115 kg/m3; _SIWH - Dämmung, hart Mineralwolle, Embodied Energy: 21.4 (MJ/kg); _SIWH - Dämmung, hart Mineralwolle, Embodied Carbon: 1.69 (kgCO₂/kg); _SIWH - Dämmung, hart Mineralwolle, Name: _SIWH - Dämmung, hart Mineralwolle; _SIWH - Dämmung, hart Mineralwolle, Participates in Collision Detection: yes

# IfcCovering: _SIWH - Attika1 AchseB EG 440 x 865 (2)
In: Staffelgeschoss
Classification: Dämmung (Archicad Klassifizierung); Material: _SIWH - Dämmung, weich Mineralwolle, _SIWH - Dämmung, hart Mineralwolle
Pset_CoveringCommon - Material: _SIWH - Attika1 AchseB EG
AC_Pset_RenovationAndPhasing - Renovation Status: Existing
Material Properties - _SIWH - Dämmung, weich Mineralwolle, ThermalConductivity: 0.037; _SIWH - Dämmung, weich Mineralwolle, SpecificHeatCapacity: 840 J/kg/K; _SIWH - Dämmung, weich Mineralwolle, MassDensity: 40 kg/m3; _SIWH - Dämmung, weich Mineralwolle, Embodied Energy: 14.3 (MJ/kg); _SIWH - Dämmung, weich Mineralwolle, Embodied Carbon: 1.08 (kgCO₂/kg); _SIWH - Dämmung, weich Mineralwolle, Name: _SIWH - Dämmung, weich Mineralwolle; _SIWH - Dämmung, weich Mineralwolle, Participates in Collision Detection: yes; _SIWH - Dämmung, hart Mineralwolle, ThermalConductivity: 0.036; _SIWH - Dämmung, hart Mineralwolle, SpecificHeatCapacity: 840 J/kg/K; _SIWH - Dämmung, hart Mineralwolle, MassDensity: 115 kg/m3; _SIWH - Dämmung, hart Mineralwolle, Embodied Energy: 21.4 (MJ/kg); _SIWH - Dämmung, hart Mineralwolle, Embodied Carbon: 1.69 (kgCO₂/kg); _SIWH - Dämmung, hart Mineralwolle, Name: _SIWH - Dämmung, hart Mineralwolle; _SIWH - Dämmung, hart Mineralwolle, Participates in Collision Detection: yes
Name
A-Wand057
A-Wand059

# IfcCovering: _SIWH - Attika2 Achse3 EG 440 x 585, A-Wand056
In: Staffelgeschoss
Classification: Dämmung (Archicad Klassifizierung); Material: _SIWH - Dämmung, weich Mineralwolle, _SIWH - Dämmung, hart Mineralwolle
Pset_CoveringCommon - Material: _SIWH - Attika2 Achse3 EG
Material Properties - _SIWH - Dämmung, weich Mineralwolle, ThermalConductivity: 0.037; _SIWH - Dämmung, weich Mineralwolle, SpecificHeatCapacity: 840 J/kg/K; _SIWH - Dämmung, weich Mineralwolle, MassDensity: 40 kg/m3; _SIWH - Dämmung, weich Mineralwolle, Embodied Energy: 14.3 (MJ/kg); _SIWH - Dämmung, weich Mineralwolle, Embodied Carbon: 1.08 (kgCO₂/kg); _SIWH - Dämmung, weich Mineralwolle, Name: _SIWH - Dämmung, weich Mineralwolle; _SIWH - Dämmung, weich Mineralwolle, Participates in Collision Detection: yes; _SIWH - Dämmung, hart Mineralwolle, ThermalConductivity: 0.036; _SIWH - Dämmung, hart Mineralwolle, SpecificHeatCapacity: 840 J/kg/K; _SIWH - Dämmung, hart Mineralwolle, MassDensity: 115 kg/m3; _SIWH - Dämmung, hart Mineralwolle, Embodied Energy: 21.4 (MJ/kg); _SIWH - Dämmung, hart Mineralwolle, Embodied Carbon: 1.69 (kgCO₂/kg); _SIWH - Dämmung, hart Mineralwolle, Name: _SIWH - Dämmung, hart Mineralwolle; _SIWH - Dämmung, hart Mineralwolle, Participates in Collision Detection: yes
AC_Pset_RenovationAndPhasing - Renovation Status: Existing

# IfcCovering: _SIWH - Attika3 Achse3 EG 260 x 385, A-Wand055
In: Staffelgeschoss
Classification: Dämmung (Archicad Klassifizierung); Material: _SIWH - Dämmung, hart Mineralwolle
Pset_CoveringCommon - Material: _SIWH - Attika3 Achse3 EG
AC_Pset_RenovationAndPhasing - Renovation Status: Existing
Material Properties - _SIWH - Dämmung, hart Mineralwolle, ThermalConductivity: 0.036; _SIWH - Dämmung, hart Mineralwolle, SpecificHeatCapacity: 840 J/kg/K; _SIWH - Dämmung, hart Mineralwolle, MassDensity: 115 kg/m3; _SIWH - Dämmung, hart Mineralwolle, Embodied Energy: 21.4 (MJ/kg); _SIWH - Dämmung, hart Mineralwolle, Embodied Carbon: 1.69 (kgCO₂/kg); _SIWH - Dämmung, hart Mineralwolle, Name: _SIWH - Dämmung, hart Mineralwolle; _SIWH - Dämmung, hart Mineralwolle, Participates in Collision Detection: yes

# IfcCovering: _SIWH - Attika4 Achse3 EG 320 x 385, A-Wand058
In: Staffelgeschoss
Classification: Dämmung (Archicad Klassifizierung); Material: _SIWH - Dämmung, hart Mineralwolle
Pset_CoveringCommon - Material: _SIWH - Attika4 Achse3 EG
Material Properties - _SIWH - Dämmung, hart Mineralwolle, ThermalConductivity: 0.036; _SIWH - Dämmung, hart Mineralwolle, SpecificHeatCapacity: 840 J/kg/K; _SIWH - Dämmung, hart Mineralwolle, MassDensity: 115 kg/m3; _SIWH - Dämmung, hart Mineralwolle, Embodied Energy: 21.4 (MJ/kg); _SIWH - Dämmung, hart Mineralwolle, Embodied Carbon: 1.69 (kgCO₂/kg); _SIWH - Dämmung, hart Mineralwolle, Name: _SIWH - Dämmung, hart Mineralwolle; _SIWH - Dämmung, hart Mineralwolle, Participates in Collision Detection: yes
AC_Pset_RenovationAndPhasing - Renovation Status: Existing

# IfcCovering: _SIWH - Attikablech1 Achse3+B EG 660 x 115 (2)
In: Staffelgeschoss
Classification: Dachdeckung (Archicad Klassifizierung)
Pset_CoveringCommon - Material: _SIWH - Attikablech1 Achse3+B EG
AC_Pset_RenovationAndPhasing - Renovation Status: Existing
Material Properties - _SIWH - Metall, Aluminium, ThermalConductivity: 160; _SIWH - Metall, Aluminium, SpecificHeatCapacity: 880 J/kg/K; _SIWH - Metall, Aluminium, MassDensity: 2800 kg/m3; _SIWH - Metall, Aluminium, Embodied Energy: 155 (MJ/kg); _SIWH - Metall, Aluminium, Embodied Carbon: 9.16 (kgCO₂/kg); _SIWH - Metall, Aluminium, Name: _SIWH - Metall, Aluminium; _SIWH - Metall, Aluminium, Participates in Collision Detection: yes; _SIWH - Holz, Bauholz, ThermalConductivity: 0.13; _SIWH - Holz, Bauholz, SpecificHeatCapacity: 1600 J/kg/K; _SIWH - Holz, Bauholz, MassDensity: 500 kg/m3; _SIWH - Holz, Bauholz, Embodied Energy: 6.95 (MJ/kg); _SIWH - Holz, Bauholz, Embodied Carbon: 0.29 (kgCO₂/kg); _SIWH - Holz, Bauholz, Name: _SIWH - Holz, Bauholz; _SIWH - Holz, Bauholz, Participates in Collision Detection: yes
Name | Material
Wand-028 | _SIWH - Metall, Aluminium, _SIWH - Holz, Bauholz
Wand-028 | _SIWH - Holz, Bauholz, _SIWH - Metall, Aluminium

# IfcCovering: _SIWH - Attikablech3 Achse3+4' EG 380 x 92 (2)
In: Staffelgeschoss
Classification: Dachdeckung (Archicad Klassifizierung); Material: _SIWH - Metall, Aluminium, _SIWH - Holz, Bauholz
Pset_CoveringCommon - Material: _SIWH - Attikablech3 Achse3+4' EG
AC_Pset_RenovationAndPhasing - Renovation Status: Existing
Material Properties - _SIWH - Metall, Aluminium, ThermalConductivity: 160; _SIWH - Metall, Aluminium, SpecificHeatCapacity: 880 J/kg/K; _SIWH - Metall, Aluminium, MassDensity: 2800 kg/m3; _SIWH - Metall, Aluminium, Embodied Energy: 155 (MJ/kg); _SIWH - Metall, Aluminium, Embodied Carbon: 9.16 (kgCO₂/kg); _SIWH - Metall, Aluminium, Name: _SIWH - Metall, Aluminium; _SIWH - Metall, Aluminium, Participates in Collision Detection: yes; _SIWH - Holz, Bauholz, ThermalConductivity: 0.13; _SIWH - Holz, Bauholz, SpecificHeatCapacity: 1600 J/kg/K; _SIWH - Holz, Bauholz, MassDensity: 500 kg/m3; _SIWH - Holz, Bauholz, Embodied Energy: 6.95 (MJ/kg); _SIWH - Holz, Bauholz, Embodied Carbon: 0.29 (kgCO₂/kg); _SIWH - Holz, Bauholz, Name: _SIWH - Holz, Bauholz; _SIWH - Holz, Bauholz, Participates in Collision Detection: yes

# IfcCovering: _SIWH - Außendämmung Wand KG 230 x 2305, Unterzug-015
In: Kellergeschoss
Classification: Dämmung (Archicad Klassifizierung); Material: _SIWH - Dämmung, Perimeterdämmung (3)
Pset_CoveringCommon - Material: _SIWH - Außendämmung Wand KG
AC_Pset_RenovationAndPhasing - Renovation Status: Existing
Material Properties - _SIWH - Dämmung, Perimeterdämmung, ThermalConductivity: 0.046; _SIWH - Dämmung, Perimeterdämmung, SpecificHeatCapacity: 900 J/kg/K; _SIWH - Dämmung, Perimeterdämmung, MassDensity: 151.33 kg/m3; _SIWH - Dämmung, Perimeterdämmung, Embodied Energy: 13.5 (MJ/kg); _SIWH - Dämmung, Perimeterdämmung, Embodied Carbon: 0.9 (kgCO₂/kg); _SIWH - Dämmung, Perimeterdämmung, Name: _SIWH - Dämmung, Perimeterdämmung; _SIWH - Dämmung, Perimeterdämmung, Participates in Collision Detection: yes

# IfcCovering: _SIWH - Außendämmung Wand KG 230 x 3250 (2)
In: Kellergeschoss
Classification: Dämmung (Archicad Klassifizierung); Material: _SIWH - Dämmung, Perimeterdämmung (3)
AC_Pset_RenovationAndPhasing - Renovation Status: Existing
Material Properties - _SIWH - Dämmung, Perimeterdämmung, ThermalConductivity: 0.046; _SIWH - Dämmung, Perimeterdämmung, SpecificHeatCapacity: 900 J/kg/K; _SIWH - Dämmung, Perimeterdämmung, MassDensity: 151.33 kg/m3; _SIWH - Dämmung, Perimeterdämmung, Embodied Energy: 13.5 (MJ/kg); _SIWH - Dämmung, Perimeterdämmung, Embodied Carbon: 0.9 (kgCO₂/kg); _SIWH - Dämmung, Perimeterdämmung, Name: _SIWH - Dämmung, Perimeterdämmung; _SIWH - Dämmung, Perimeterdämmung, Participates in Collision Detection: yes
Pset_CoveringCommon - Material: _SIWH - Außendämmung Wand KG
Name
Unterzug-016
Unterzug-015

# IfcCovering: _SIWH - Außendämmung Wand KG 230 x 3500 (8)
In: Kellergeschoss
Classification: Dämmung (Archicad Klassifizierung); Material: _SIWH - Dämmung, Perimeterdämmung (3)
Pset_CoveringCommon - Material: _SIWH - Außendämmung Wand KG
AC_Pset_RenovationAndPhasing - Renovation Status: Existing
Material Properties - _SIWH - Dämmung, Perimeterdämmung, ThermalConductivity: 0.046; _SIWH - Dämmung, Perimeterdämmung, SpecificHeatCapacity: 900 J/kg/K; _SIWH - Dämmung, Perimeterdämmung, MassDensity: 151.33 kg/m3; _SIWH - Dämmung, Perimeterdämmung, Embodied Energy: 13.5 (MJ/kg); _SIWH - Dämmung, Perimeterdämmung, Embodied Carbon: 0.9 (kgCO₂/kg); _SIWH - Dämmung, Perimeterdämmung, Name: _SIWH - Dämmung, Perimeterdämmung; _SIWH - Dämmung, Perimeterdämmung, Participates in Collision Detection: yes
Name
5 x Unterzug-015
2 x Unterzug-017
Unterzug-016

# IfcCovering: _SIWH - BO | Perimeterdämmung 10 | 10cm 100 (3)
In: Gründung
Classification: Dämmung (Archicad Klassifizierung); Material: _SIWH - Dämmung, Perimeterdämmung
Pset_CoveringCommon - Material: _SIWH - BO | Perimeterdämmung 10 | 10cm
AC_Pset_RenovationAndPhasing - Renovation Status: Existing
Material Properties - _SIWH - Dämmung, Perimeterdämmung, ThermalConductivity: 0.046; _SIWH - Dämmung, Perimeterdämmung, SpecificHeatCapacity: 900 J/kg/K; _SIWH - Dämmung, Perimeterdämmung, MassDensity: 151.33 kg/m3; _SIWH - Dämmung, Perimeterdämmung, Embodied Energy: 13.5 (MJ/kg); _SIWH - Dämmung, Perimeterdämmung, Embodied Carbon: 0.9 (kgCO₂/kg); _SIWH - Dämmung, Perimeterdämmung, Name: _SIWH - Dämmung, Perimeterdämmung; _SIWH - Dämmung, Perimeterdämmung, Participates in Collision Detection: yes
Name
Decke035
Decke033
Decke034

# IfcCovering: _SIWH - Belag Terrasse SG 40, Decke052
In: Staffelgeschoss
Classification: Dachdeckung (Archicad Klassifizierung); Material: _SIWH - Belag Terrasse SG
Pset_CoveringCommon - Material: _SIWH - Belag Terrasse SG
AC_Pset_RenovationAndPhasing - Renovation Status: Existing
Material Properties - _SIWH - Belag Terrasse SG, ThermalConductivity: 2.3; _SIWH - Belag Terrasse SG, SpecificHeatCapacity: 1000 J/kg/K; _SIWH - Belag Terrasse SG, MassDensity: 2600 kg/m3; _SIWH - Belag Terrasse SG, Embodied Energy: 1 (MJ/kg); _SIWH - Belag Terrasse SG, Embodied Carbon: 0.06 (kgCO₂/kg); _SIWH - Belag Terrasse SG, Name: _SIWH - Belag Terrasse SG; _SIWH - Belag Terrasse SG, Participates in Collision Detection: yes

# IfcCovering: _SIWH - DE | Dämmung 8 | 8cm 80, Decke018
In: Erdgeschoss
Classification: Dämmung (Archicad Klassifizierung); Material: _SIWH - Dämmung, weich Mineralwolle
Pset_CoveringCommon - Material: _SIWH - DE | Dämmung 8 | 8cm
Material Properties - _SIWH - Dämmung, weich Mineralwolle, ThermalConductivity: 0.037; _SIWH - Dämmung, weich Mineralwolle, SpecificHeatCapacity: 840 J/kg/K; _SIWH - Dämmung, weich Mineralwolle, MassDensity: 40 kg/m3; _SIWH - Dämmung, weich Mineralwolle, Embodied Energy: 14.3 (MJ/kg); _SIWH - Dämmung, weich Mineralwolle, Embodied Carbon: 1.08 (kgCO₂/kg); _SIWH - Dämmung, weich Mineralwolle, Name: _SIWH - Dämmung, weich Mineralwolle; _SIWH - Dämmung, weich Mineralwolle, Participates in Collision Detection: yes
AC_Pset_RenovationAndPhasing - Renovation Status: Existing

# IfcCovering: _SIWH - Dämmung, hart Mineralwolle 100 (3)
In: Staffelgeschoss
Classification: Dämmung (Archicad Klassifizierung); Material: _SIWH - Dämmung, hart Mineralwolle
Pset_CoveringCommon - Material: _SIWH - Dämmung, hart Mineralwolle
AC_Pset_RenovationAndPhasing - Renovation Status: Existing
Material Properties - _SIWH - Dämmung, hart Mineralwolle, ThermalConductivity: 0.036; _SIWH - Dämmung, hart Mineralwolle, SpecificHeatCapacity: 840 J/kg/K; _SIWH - Dämmung, hart Mineralwolle, MassDensity: 115 kg/m3; _SIWH - Dämmung, hart Mineralwolle, Embodied Energy: 21.4 (MJ/kg); _SIWH - Dämmung, hart Mineralwolle, Embodied Carbon: 1.69 (kgCO₂/kg); _SIWH - Dämmung, hart Mineralwolle, Name: _SIWH - Dämmung, hart Mineralwolle; _SIWH - Dämmung, hart Mineralwolle, Participates in Collision Detection: yes
Name
Decke012
Decke011
Decke022

# IfcCovering: _SIWH - Dämmung, hart Mineralwolle 140 (2)
Classification: Dämmung (Archicad Klassifizierung); Material: _SIWH - Dämmung, hart Mineralwolle
Pset_CoveringCommon - Material: _SIWH - Dämmung, hart Mineralwolle
AC_Pset_RenovationAndPhasing - Renovation Status: Existing
Material Properties - _SIWH - Dämmung, hart Mineralwolle, ThermalConductivity: 0.036; _SIWH - Dämmung, hart Mineralwolle, SpecificHeatCapacity: 840 J/kg/K; _SIWH - Dämmung, hart Mineralwolle, MassDensity: 115 kg/m3; _SIWH - Dämmung, hart Mineralwolle, Embodied Energy: 21.4 (MJ/kg); _SIWH - Dämmung, hart Mineralwolle, Embodied Carbon: 1.69 (kgCO₂/kg); _SIWH - Dämmung, hart Mineralwolle, Name: _SIWH - Dämmung, hart Mineralwolle; _SIWH - Dämmung, hart Mineralwolle, Participates in Collision Detection: yes
Name | In
Decke014 | Staffelgeschoss
Decke032 | Dachaufsicht

# IfcCovering: _SIWH - Dämmung, hart Mineralwolle 150, Decke023
In: Staffelgeschoss
Classification: Dämmung (Archicad Klassifizierung); Material: _SIWH - Dämmung, hart Mineralwolle
Pset_CoveringCommon - Material: _SIWH - Dämmung, hart Mineralwolle
AC_Pset_RenovationAndPhasing - Renovation Status: Existing
Material Properties - _SIWH - Dämmung, hart Mineralwolle, ThermalConductivity: 0.036; _SIWH - Dämmung, hart Mineralwolle, SpecificHeatCapacity: 840 J/kg/K; _SIWH - Dämmung, hart Mineralwolle, MassDensity: 115 kg/m3; _SIWH - Dämmung, hart Mineralwolle, Embodied Energy: 21.4 (MJ/kg); _SIWH - Dämmung, hart Mineralwolle, Embodied Carbon: 1.69 (kgCO₂/kg); _SIWH - Dämmung, hart Mineralwolle, Name: _SIWH - Dämmung, hart Mineralwolle; _SIWH - Dämmung, hart Mineralwolle, Participates in Collision Detection: yes

# IfcCovering: _SIWH - Dämmung, hart Mineralwolle 275 (2)
In: Staffelgeschoss
Classification: Dämmung (Archicad Klassifizierung); Material: _SIWH - Dämmung, hart Mineralwolle
Pset_CoveringCommon - Material: _SIWH - Dämmung, hart Mineralwolle
AC_Pset_RenovationAndPhasing - Renovation Status: Existing
Material Properties - _SIWH - Dämmung, hart Mineralwolle, ThermalConductivity: 0.036; _SIWH - Dämmung, hart Mineralwolle, SpecificHeatCapacity: 840 J/kg/K; _SIWH - Dämmung, hart Mineralwolle, MassDensity: 115 kg/m3; _SIWH - Dämmung, hart Mineralwolle, Embodied Energy: 21.4 (MJ/kg); _SIWH - Dämmung, hart Mineralwolle, Embodied Carbon: 1.69 (kgCO₂/kg); _SIWH - Dämmung, hart Mineralwolle, Name: _SIWH - Dämmung, hart Mineralwolle; _SIWH - Dämmung, hart Mineralwolle, Participates in Collision Detection: yes
Name
Decke018
Decke019

# IfcCovering: _SIWH - Dämmung, hart Mineralwolle 60 (4)
Classification: Dämmung (Archicad Klassifizierung); Material: _SIWH - Dämmung, hart Mineralwolle
Pset_CoveringCommon - Material: _SIWH - Dämmung, hart Mineralwolle
AC_Pset_RenovationAndPhasing - Renovation Status: Existing
Material Properties - _SIWH - Dämmung, hart Mineralwolle, ThermalConductivity: 0.036; _SIWH - Dämmung, hart Mineralwolle, SpecificHeatCapacity: 840 J/kg/K; _SIWH - Dämmung, hart Mineralwolle, MassDensity: 115 kg/m3; _SIWH - Dämmung, hart Mineralwolle, Embodied Energy: 21.4 (MJ/kg); _SIWH - Dämmung, hart Mineralwolle, Embodied Carbon: 1.69 (kgCO₂/kg); _SIWH - Dämmung, hart Mineralwolle, Name: _SIWH - Dämmung, hart Mineralwolle; _SIWH - Dämmung, hart Mineralwolle, Participates in Collision Detection: yes
Name | In
Decke017 | Erdgeschoss
2 x A-Wand035 | Erdgeschoss
Decke017 | Staffelgeschoss

# IfcCovering: _SIWH - Dämmung, weich Mineralwolle 180, A-Wand060
In: Staffelgeschoss
Classification: Dämmung (Archicad Klassifizierung); Material: _SIWH - Dämmung, weich Mineralwolle
Pset_CoveringCommon - Material: _SIWH - Dämmung, weich Mineralwolle
AC_Pset_RenovationAndPhasing - Renovation Status: Existing
Material Properties - _SIWH - Dämmung, weich Mineralwolle, ThermalConductivity: 0.037; _SIWH - Dämmung, weich Mineralwolle, SpecificHeatCapacity: 840 J/kg/K; _SIWH - Dämmung, weich Mineralwolle, MassDensity: 40 kg/m3; _SIWH - Dämmung, weich Mineralwolle, Embodied Energy: 14.3 (MJ/kg); _SIWH - Dämmung, weich Mineralwolle, Embodied Carbon: 1.08 (kgCO₂/kg); _SIWH - Dämmung, weich Mineralwolle, Name: _SIWH - Dämmung, weich Mineralwolle; _SIWH - Dämmung, weich Mineralwolle, Participates in Collision Detection: yes

# IfcCovering: _SIWH - Gründach (5)
Material: _SIWH - Gründach
Pset_CoveringCommon - Material: _SIWH - Gründach
AC_Pset_RenovationAndPhasing - Renovation Status: Existing
Material Properties - _SIWH - Gründach, ThermalConductivity: 0.8; _SIWH - Gründach, SpecificHeatCapacity: 800 J/kg/K; _SIWH - Gründach, MassDensity: 2300 kg/m3; _SIWH - Gründach, Embodied Energy: 0.92 (MJ/kg); _SIWH - Gründach, Embodied Carbon: 0.15 (kgCO₂/kg); _SIWH - Gründach, Name: _SIWH - Gründach; _SIWH - Gründach, Participates in Collision Detection: yes
Name | In | Classification
2 x Freifläche-006 | Staffelgeschoss | Dachdeckung (Archicad Klassifizierung)
2 x Freifläche-006 | Staffelgeschoss | Dämmung (Archicad Klassifizierung)
Freifläche-004 | Dachaufsicht | Dachdeckung (Archicad Klassifizierung)

# IfcCovering: _SIWH - Schotter, fein, Freifläche-004
In: Dachaufsicht
Classification: Dachdeckung (Archicad Klassifizierung); Material: _SIWH - Schotter, fein
Pset_CoveringCommon - Material: _SIWH - Schotter, fein
Material Properties - _SIWH - Schotter, fein, ThermalConductivity: 0.55; _SIWH - Schotter, fein, SpecificHeatCapacity: 1000 J/kg/K; _SIWH - Schotter, fein, MassDensity: 1600 kg/m3; _SIWH - Schotter, fein, Embodied Energy: 1 (MJ/kg); _SIWH - Schotter, fein, Embodied Carbon: 0.06 (kgCO₂/kg); _SIWH - Schotter, fein, Name: _SIWH - Schotter, fein; _SIWH - Schotter, fein, Participates in Collision Detection: yes
AC_Pset_RenovationAndPhasing - Renovation Status: Existing

# IfcCovering: _SIWH - Schotter, fein 150, Decke053
In: Staffelgeschoss
Classification: Dachdeckung (Archicad Klassifizierung); Material: _SIWH - Schotter, fein
AC_Pset_RenovationAndPhasing - Renovation Status: Existing
Material Properties - _SIWH - Schotter, fein, ThermalConductivity: 0.55; _SIWH - Schotter, fein, SpecificHeatCapacity: 1000 J/kg/K; _SIWH - Schotter, fein, MassDensity: 1600 kg/m3; _SIWH - Schotter, fein, Embodied Energy: 1 (MJ/kg); _SIWH - Schotter, fein, Embodied Carbon: 0.06 (kgCO₂/kg); _SIWH - Schotter, fein, Name: _SIWH - Schotter, fein; _SIWH - Schotter, fein, Participates in Collision Detection: yes
Pset_CoveringCommon - Material: _SIWH - Schotter, fein

# IfcCovering: _SIWH - Schotter, fein 200, Decke054
In: Staffelgeschoss
Classification: Dachdeckung (Archicad Klassifizierung); Material: _SIWH - Schotter, fein
Pset_CoveringCommon - Material: _SIWH - Schotter, fein
Material Properties - _SIWH - Schotter, fein, ThermalConductivity: 0.55; _SIWH - Schotter, fein, SpecificHeatCapacity: 1000 J/kg/K; _SIWH - Schotter, fein, MassDensity: 1600 kg/m3; _SIWH - Schotter, fein, Embodied Energy: 1 (MJ/kg); _SIWH - Schotter, fein, Embodied Carbon: 0.06 (kgCO₂/kg); _SIWH - Schotter, fein, Name: _SIWH - Schotter, fein; _SIWH - Schotter, fein, Participates in Collision Detection: yes
AC_Pset_RenovationAndPhasing - Renovation Status: Existing

# IfcCovering: _SIWH - WA | Dämmung 8 | 8cm 80, A-Wand036
In: Erdgeschoss
Classification: Dämmung (Archicad Klassifizierung); Material: _SIWH - Dämmung, weich Mineralwolle
Pset_CoveringCommon - Material: _SIWH - WA | Dämmung 8 | 8cm
AC_Pset_RenovationAndPhasing - Renovation Status: Existing
Material Properties - _SIWH - Dämmung, weich Mineralwolle, ThermalConductivity: 0.037; _SIWH - Dämmung, weich Mineralwolle, SpecificHeatCapacity: 840 J/kg/K; _SIWH - Dämmung, weich Mineralwolle, MassDensity: 40 kg/m3; _SIWH - Dämmung, weich Mineralwolle, Embodied Energy: 14.3 (MJ/kg); _SIWH - Dämmung, weich Mineralwolle, Embodied Carbon: 1.08 (kgCO₂/kg); _SIWH - Dämmung, weich Mineralwolle, Name: _SIWH - Dämmung, weich Mineralwolle; _SIWH - Dämmung, weich Mineralwolle, Participates in Collision Detection: yes

# IfcDistributionElement: Badewanne rund 22, Objekt-0061
In: Staffelgeschoss
Classification: Sanitäreinrichtung (Archicad Klassifizierung)
AC_Pset_RenovationAndPhasing - Renovation Status: Existing

# IfcDistributionElement: Duschset 22 (2)
In: Staffelgeschoss
Classification: Sanitäreinrichtung (Archicad Klassifizierung)
AC_Pset_RenovationAndPhasing - Renovation Status: Existing

# IfcDistributionElement: Kleiderschrank 22, Objekt-0063
In: Staffelgeschoss
Classification: Sanitäreinrichtung (Archicad Klassifizierung)
AC_Pset_RenovationAndPhasing - Renovation Status: Existing

# IfcDistributionElement: Unterschrank Mehrfach-Schublade 22 (2)
Classification: Sanitäreinrichtung (Archicad Klassifizierung)
AC_Pset_RenovationAndPhasing - Renovation Status: Existing
Name | In
Objekt-0079 | Erdgeschoss
Objekt-0079 | Staffelgeschoss

# IfcDistributionElement: Wand WC 22 (4)
Classification: Sanitäreinrichtung (Archicad Klassifizierung)
AC_Pset_RenovationAndPhasing - Renovation Status: Existing
Name | In
Objekt-0061 | Erdgeschoss
3 x Objekt-0061 | Staffelgeschoss

# IfcDistributionElement: Waschbecken 1 22 (4)
Classification: Sanitäreinrichtung (Archicad Klassifizierung)
AC_Pset_RenovationAndPhasing - Renovation Status: Existing
Name | In
Objekt-0061 | Erdgeschoss
3 x Objekt-0061 | Staffelgeschoss

# IfcDistributionElement: _SIWH - Lichtschacht 1270x800 870 x 1410, Stütze-004
In: Kellergeschoss
Classification: Schacht / Graben / Revisionsschacht (Archicad Klassifizierung); Material: _SIWH - Beton, Stahlbeton Fertigteil, _SIWH - Dämmung, hart Mineralwolle (2)
AC_Pset_RenovationAndPhasing - Renovation Status: Existing
Material Properties - _SIWH - Beton, Stahlbeton Fertigteil, ThermalConductivity: 1.15; _SIWH - Beton, Stahlbeton Fertigteil, SpecificHeatCapacity: 1000 J/kg/K; _SIWH - Beton, Stahlbeton Fertigteil, MassDensity: 1800 kg/m3; _SIWH - Beton, Stahlbeton Fertigteil, Embodied Energy: 0.74 (MJ/kg); _SIWH - Beton, Stahlbeton Fertigteil, Embodied Carbon: 0.107 (kgCO₂/kg); _SIWH - Beton, Stahlbeton Fertigteil, Name: _SIWH - Beton, Stahlbeton Fertigteil; _SIWH - Beton, Stahlbeton Fertigteil, Participates in Collision Detection: yes; _SIWH - Dämmung, hart Mineralwolle, ThermalConductivity: 0.036; _SIWH - Dämmung, hart Mineralwolle, SpecificHeatCapacity: 840 J/kg/K; _SIWH - Dämmung, hart Mineralwolle, MassDensity: 115 kg/m3; _SIWH - Dämmung, hart Mineralwolle, Embodied Energy: 21.4 (MJ/kg); _SIWH - Dämmung, hart Mineralwolle, Embodied Carbon: 1.69 (kgCO₂/kg); _SIWH - Dämmung, hart Mineralwolle, Name: _SIWH - Dämmung, hart Mineralwolle; _SIWH - Dämmung, hart Mineralwolle, Participates in Collision Detection: yes

# IfcDoor: Eingang 01 1-Fl 1S 26, Tür-018
In: Erdgeschoss
Type - OperationType: SINGLE_SWING_RIGHT; ParameterTakesPrecedence: no; Sizeable: no
OverallHeight: 3.62 m; OverallWidth: 2.63477 m; Classification: Tür / Tor (Archicad Klassifizierung)
Pset_DoorCommon - GlazingAreaFraction: 4.86465; IsExternal: yes
AC_Pset_RenovationAndPhasing - Renovation Status: Existing

# IfcDoor: Schiebetür 02 1-Fl 26, Tür-024
In: Erdgeschoss
Type - OperationType: SLIDING_TO_LEFT; ParameterTakesPrecedence: no; Sizeable: no
OverallHeight: 2.94 m; OverallWidth: 1.15 m; Classification: Tür (Archicad Klassifizierung)
AC_Pset_RenovationAndPhasing - Renovation Status: Existing
Pset_DoorCommon - GlazingAreaFraction: 2.60263; IsExternal: no

# IfcDoor: Schiebetür 02 1-Fl 26 (3)
In: Erdgeschoss
Type - OperationType: SLIDING_TO_RIGHT; ParameterTakesPrecedence: no; Sizeable: no
Classification: Tür (Archicad Klassifizierung)
Pset_DoorCommon - IsExternal: no
AC_Pset_RenovationAndPhasing - Renovation Status: Existing
Name | OverallHeight (m) | OverallWidth (m) | GlazingAreaFraction
Tür-024 | 2.94 | 2.76 | 7.01387
Tür-024 | 2.94 | 1.26 | 2.90402
Tür-024 | 2.26 | 1.26 | 2.18329

# IfcFooting (10)
In: Gründung
AC_Pset_RenovationAndPhasing - Renovation Status: Existing
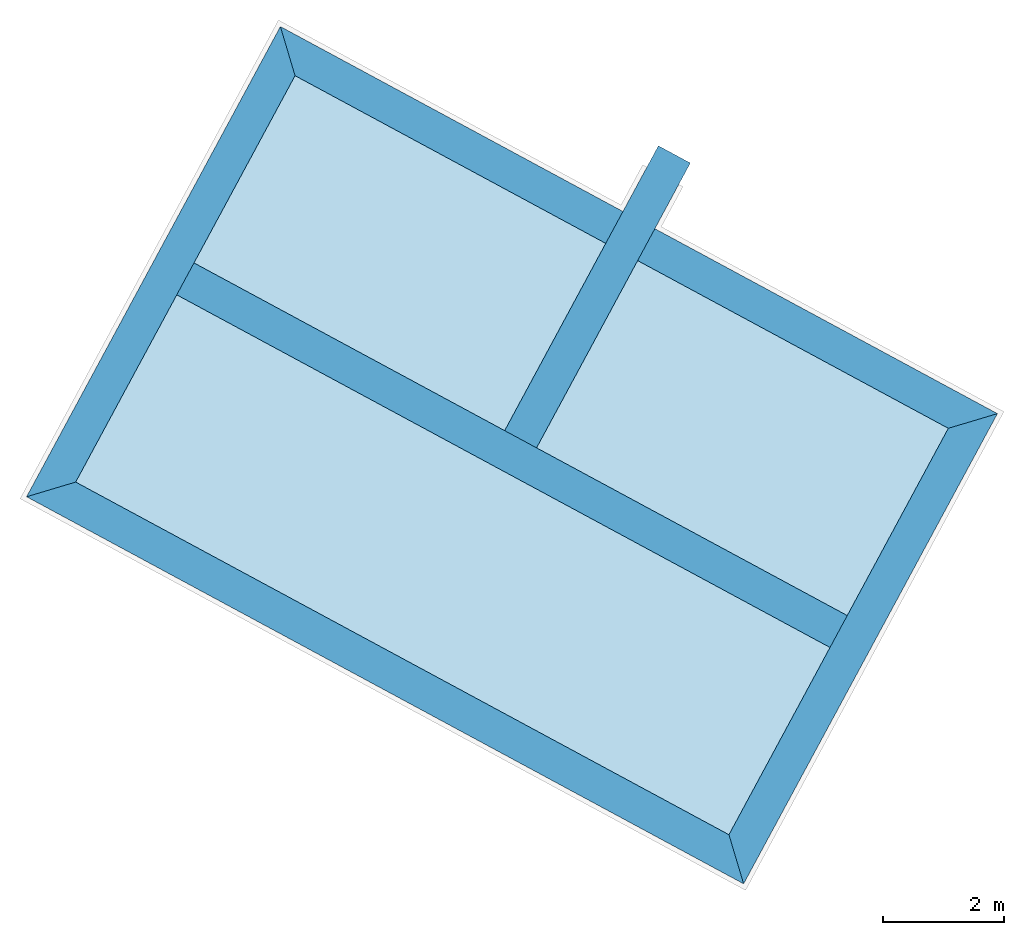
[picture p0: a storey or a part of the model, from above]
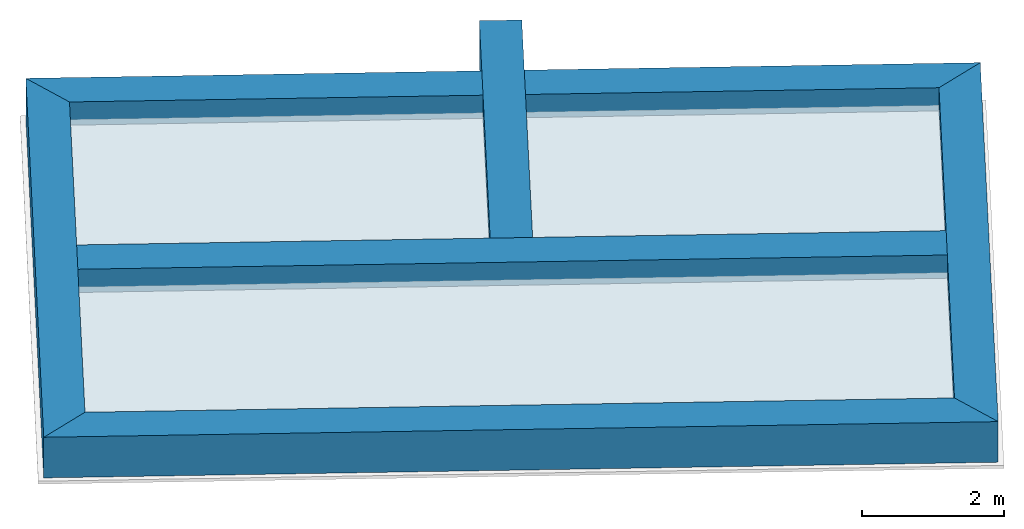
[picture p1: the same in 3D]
Properties of the parts of a building model (IFC2X3), part 2 of 3

# IfcFooting (10)
Name | Classification | Material | _SIWH - Beton, Stahlbeton, ThermalConductivity | _SIWH - Beton, Stahlbeton, SpecificHeatCapacity (J/kg/K) | _SIWH - Beton, Stahlbeton, MassDensity (kg/m3) | _SIWH - Beton, Stahlbeton, Embodied Energy | _SIWH - Beton, Stahlbeton, Embodied Carbon | _SIWH - Beton, Stahlbeton, Name | _SIWH - Beton, Stahlbeton, Participates in Collision Detection
6 x Unterzug-014 | Fundament (Archicad Klassifizierung) | _SIWH - Beton, Stahlbeton | 1.35 | 1000 | 2000 | 0.78 (MJ/kg) | 0.113 (kgCO₂/kg) | _SIWH - Beton, Stahlbeton | yes
Decke037 | Fundament (Archicad Klassifizierung) | Beton, unbewehrt | Material Properties - Beton, unbewehrt, ThermalConductivity: 0.8; Beton, unbewehrt, SpecificHeatCapacity: 800 J/kg/K; Beton, unbewehrt, MassDensity: 2300 kg/m3; Beton, unbewehrt, Embodied Energy: 0.92 (MJ/kg); Beton, unbewehrt, Embodied Carbon: 0.15 (kgCO₂/kg); Beton, unbewehrt, Name: Beton, unbewehrt; Beton, unbewehrt, Participates in Collision Detection: yes
Decke038 | Fundament (Archicad Klassifizierung) | Beton, unbewehrt | Material Properties - Beton, unbewehrt, ThermalConductivity: 0.8; Beton, unbewehrt, SpecificHeatCapacity: 800 J/kg/K; Beton, unbewehrt, MassDensity: 2300 kg/m3; Beton, unbewehrt, Embodied Energy: 0.92 (MJ/kg); Beton, unbewehrt, Embodied Carbon: 0.15 (kgCO₂/kg); Beton, unbewehrt, Name: Beton, unbewehrt; Beton, unbewehrt, Participates in Collision Detection: yes
Decke039 | Bodenplatte / Flachgründung (Archicad Klassifizierung) | Beton, unbewehrt | Material Properties - Beton, unbewehrt, ThermalConductivity: 0.8; Beton, unbewehrt, SpecificHeatCapacity: 800 J/kg/K; Beton, unbewehrt, MassDensity: 2300 kg/m3; Beton, unbewehrt, Embodied Energy: 0.92 (MJ/kg); Beton, unbewehrt, Embodied Carbon: 0.15 (kgCO₂/kg); Beton, unbewehrt, Name: Beton, unbewehrt; Beton, unbewehrt, Participates in Collision Detection: yes
Decke036 | Fundament (Archicad Klassifizierung) | Beton, unbewehrt | Material Properties - Beton, unbewehrt, ThermalConductivity: 0.8; Beton, unbewehrt, SpecificHeatCapacity: 800 J/kg/K; Beton, unbewehrt, MassDensity: 2300 kg/m3; Beton, unbewehrt, Embodied Energy: 0.92 (MJ/kg); Beton, unbewehrt, Embodied Carbon: 0.15 (kgCO₂/kg); Beton, unbewehrt, Name: Beton, unbewehrt; Beton, unbewehrt, Participates in Collision Detection: yes

# IfcFurnishingElement: Armstuhl 2 22 (3)
In: Staffelgeschoss
Classification: Möbel (Archicad Klassifizierung)
AC_Pset_RenovationAndPhasing - Renovation Status: Existing

# IfcFurnishingElement: Bistrotisch 26, Objekt-0064
In: Erdgeschoss
Classification: Möbel (Archicad Klassifizierung)
AC_Pset_RenovationAndPhasing - Renovation Status: Existing

# IfcFurnishingElement: Couchtisch 03 26, Objekt-0062
In: Erdgeschoss
Classification: Möbel (Archicad Klassifizierung)
AC_Pset_RenovationAndPhasing - Renovation Status: Existing

# IfcFurnishingElement: Couchtisch 1 22 (8)
Classification: Möbel (Archicad Klassifizierung)
AC_Pset_RenovationAndPhasing - Renovation Status: Existing
Name | In
6 x Objekt-0076 | Erdgeschoss
2 x Objekt-0072 | Staffelgeschoss

# IfcFurnishingElement: Designhocker 22, Objekt-0093
In: Erdgeschoss
Classification: Möbel (Archicad Klassifizierung)
AC_Pset_RenovationAndPhasing - Renovation Status: Existing

# IfcFurnishingElement: Designstuhl 2 22 (2)
In: Staffelgeschoss
Classification: Möbel (Archicad Klassifizierung)
AC_Pset_RenovationAndPhasing - Renovation Status: Existing

# IfcFurnishingElement: Designstuhl 3 22, Objekt-0064
In: Erdgeschoss
Classification: Möbel (Archicad Klassifizierung)
AC_Pset_RenovationAndPhasing - Renovation Status: Existing

# IfcFurnishingElement: Doppelbett 2 22, Objekt-0064
In: Staffelgeschoss
Classification: Möbel (Archicad Klassifizierung)
AC_Pset_RenovationAndPhasing - Renovation Status: Existing

# IfcFurnishingElement: Doppelbett Rahmen 22, Objekt-0064
In: Staffelgeschoss
Classification: Möbel (Archicad Klassifizierung)
AC_Pset_RenovationAndPhasing - Renovation Status: Existing

# IfcFurnishingElement: Flachbildfernseher 22 (2)
In: Staffelgeschoss
Classification: Möbel (Archicad Klassifizierung)
AC_Pset_RenovationAndPhasing - Renovation Status: Existing

# IfcFurnishingElement: Flügel 22, Objekt-0090
In: Erdgeschoss
Classification: Möbel (Archicad Klassifizierung)
AC_Pset_RenovationAndPhasing - Renovation Status: Existing

# IfcFurnishingElement: Gitter 26, Objekt-0100
In: Erdgeschoss
Classification: Möbel (Archicad Klassifizierung)
AC_Pset_RenovationAndPhasing - Renovation Status: Existing

# IfcFurnishingElement: Kamin freistehend 22, Objekt-0070
In: Erdgeschoss
Classification: Möbel (Archicad Klassifizierung)
AC_Pset_RenovationAndPhasing - Renovation Status: Existing

# IfcFurnishingElement: Kleiderschrank 22 (22)
Classification: Möbel (Archicad Klassifizierung)
AC_Pset_RenovationAndPhasing - Renovation Status: Existing
Name | In
3 x Objekt-0067 | Erdgeschoss
19 x Objekt-0066 | Staffelgeschoss

# IfcFurnishingElement: Kleiderschrank modular 22, Objekt-0066
In: Staffelgeschoss
Classification: Möbel (Archicad Klassifizierung)
AC_Pset_RenovationAndPhasing - Renovation Status: Existing

# IfcFurnishingElement: Kommode 26, Objekt-0098
In: Staffelgeschoss
Classification: Möbel (Archicad Klassifizierung)
AC_Pset_RenovationAndPhasing - Renovation Status: Existing

# IfcFurnishingElement: Konzeptküche 26 (5)
In: Erdgeschoss
Classification: Möbel (Archicad Klassifizierung)
AC_Pset_RenovationAndPhasing - Renovation Status: Existing

# IfcFurnishingElement: Regal 1 22 (2)
In: Staffelgeschoss
Classification: Möbel (Archicad Klassifizierung)
AC_Pset_RenovationAndPhasing - Renovation Status: Existing
Name
Objekt-0070
Objekt-0067

# IfcFurnishingElement: Regal 3 22 (5)
In: Erdgeschoss
Classification: Möbel (Archicad Klassifizierung)
AC_Pset_RenovationAndPhasing - Renovation Status: Existing

# IfcFurnishingElement: Schreibtisch 22, Objekt-0068
In: Staffelgeschoss
Classification: Möbel (Archicad Klassifizierung)
AC_Pset_RenovationAndPhasing - Renovation Status: Existing

# IfcFurnishingElement: Sideboard 22, Objekt-0067
In: Erdgeschoss
Classification: Möbel (Archicad Klassifizierung)
AC_Pset_RenovationAndPhasing - Renovation Status: Existing

# IfcFurnishingElement: Sideboard wandhängend 26, Objekt-0099
In: Erdgeschoss
Classification: Möbel (Archicad Klassifizierung)
AC_Pset_RenovationAndPhasing - Renovation Status: Existing

# IfcFurnishingElement: Sofa L-Form 01 26, Objekt-0064
In: Erdgeschoss
Classification: Möbel (Archicad Klassifizierung)
AC_Pset_RenovationAndPhasing - Renovation Status: Existing

# IfcFurnishingElement: Sofa Set 01 17 (5)
In: Erdgeschoss
Classification: Möbel (Archicad Klassifizierung)
AC_Pset_RenovationAndPhasing - Renovation Status: Existing

# IfcFurnishingElement: Stuhl 09 26 (12)
In: Erdgeschoss
Classification: Möbel (Archicad Klassifizierung)
AC_Pset_RenovationAndPhasing - Renovation Status: Existing

# IfcFurnishingElement: Teppich 22, Objekt-0074
In: Staffelgeschoss
Classification: Möbel (Archicad Klassifizierung)
AC_Pset_RenovationAndPhasing - Renovation Status: Existing

# IfcFurnishingElement: Tisch rechteckig 1 22, Objekt-0073
In: Erdgeschoss
Classification: Möbel (Archicad Klassifizierung)
AC_Pset_RenovationAndPhasing - Renovation Status: Existing

# IfcFurnishingElement: Unterschrank Mehrfach-Schublade 22 (3)
In: Erdgeschoss
Classification: Möbel (Archicad Klassifizierung)
AC_Pset_RenovationAndPhasing - Renovation Status: Existing

# IfcFurnishingElement: bucket chair (1) (8)
In: Erdgeschoss
Classification: Möbel (Archicad Klassifizierung)
AC_Pset_RenovationAndPhasing - Renovation Status: Existing

# IfcOpeningElement (56)
Name | In
3 x Tür-017 | Kellergeschoss
Fenster-016 | Kellergeschoss
Tür-026 | Kellergeschoss
3 x Fenster-014 | Erdgeschoss
2 x Eckfenster-008 | Erdgeschoss
7 x Tür-017 | Erdgeschoss
BD-002 | Erdgeschoss | Classification: Öffnung (Archicad Klassifizierung); AC_Pset_RenovationAndPhasing - Renovation Status: Existing
2 x Tür-026 | Erdgeschoss
4 x Fenster-003 | Erdgeschoss
4 x Tür-024 | Erdgeschoss
Tür-011 | Erdgeschoss
2 x Tür-025 | Erdgeschoss
Tür-018 | Erdgeschoss
Tür-016 | Erdgeschoss
6 x Tür-017 | Staffelgeschoss
2 x WandAbschl-001 | Staffelgeschoss
11 x Fenster-003 | Staffelgeschoss
2 x Eckfenster-007 | Staffelgeschoss
Tür-011 | Staffelgeschoss
Eckfenster-008 | Staffelgeschoss

# IfcSlab: _SIWH - Beton, Stahlbeton 120, Decke013
In: Staffelgeschoss
Classification: Rohbaudecke (Archicad Klassifizierung); Material: _SIWH - Beton, Stahlbeton
Pset_SlabCommon - IsExternal: no; LoadBearing: yes
AC_Pset_RenovationAndPhasing - Renovation Status: Existing
Material Properties - _SIWH - Beton, Stahlbeton, ThermalConductivity: 1.35; _SIWH - Beton, Stahlbeton, SpecificHeatCapacity: 1000 J/kg/K; _SIWH - Beton, Stahlbeton, MassDensity: 2000 kg/m3; _SIWH - Beton, Stahlbeton, Embodied Energy: 0.78 (MJ/kg); _SIWH - Beton, Stahlbeton, Embodied Carbon: 0.113 (kgCO₂/kg); _SIWH - Beton, Stahlbeton, Name: _SIWH - Beton, Stahlbeton; _SIWH - Beton, Stahlbeton, Participates in Collision Detection: yes

# IfcSlab: _SIWH - Beton, Stahlbeton 200 (9)
Classification: Rohbaudecke (Archicad Klassifizierung); Material: _SIWH - Beton, Stahlbeton
AC_Pset_RenovationAndPhasing - Renovation Status: Existing
Pset_SlabCommon - LoadBearing: yes
Material Properties - _SIWH - Beton, Stahlbeton, ThermalConductivity: 1.35; _SIWH - Beton, Stahlbeton, SpecificHeatCapacity: 1000 J/kg/K; _SIWH - Beton, Stahlbeton, MassDensity: 2000 kg/m3; _SIWH - Beton, Stahlbeton, Embodied Energy: 0.78 (MJ/kg); _SIWH - Beton, Stahlbeton, Embodied Carbon: 0.113 (kgCO₂/kg); _SIWH - Beton, Stahlbeton, Name: _SIWH - Beton, Stahlbeton; _SIWH - Beton, Stahlbeton, Participates in Collision Detection: yes
Name | In | IsExternal
5 x Wand-026 | Staffelgeschoss | yes
Decke010 | Staffelgeschoss | no
Decke020 | Staffelgeschoss | no
Decke-004 | Staffelgeschoss | no
Decke030 | Dachaufsicht | no

# IfcSlab: _SIWH - Beton, Stahlbeton 250 (3)
Classification: Rohbaudecke (Archicad Klassifizierung); Material: _SIWH - Beton, Stahlbeton
AC_Pset_RenovationAndPhasing - Renovation Status: Existing
Pset_SlabCommon - IsExternal: no; LoadBearing: yes
Material Properties - _SIWH - Beton, Stahlbeton, ThermalConductivity: 1.35; _SIWH - Beton, Stahlbeton, SpecificHeatCapacity: 1000 J/kg/K; _SIWH - Beton, Stahlbeton, MassDensity: 2000 kg/m3; _SIWH - Beton, Stahlbeton, Embodied Energy: 0.78 (MJ/kg); _SIWH - Beton, Stahlbeton, Embodied Carbon: 0.113 (kgCO₂/kg); _SIWH - Beton, Stahlbeton, Name: _SIWH - Beton, Stahlbeton; _SIWH - Beton, Stahlbeton, Participates in Collision Detection: yes
Name | In
Decke004 | Erdgeschoss
Decke009 | Staffelgeschoss
Decke-004 | Staffelgeschoss

# IfcSlab: _SIWH - Beton, Stahlbeton 300, Decke027
In: Kellergeschoss
Classification: Rohbaudecke (Archicad Klassifizierung); Material: _SIWH - Beton, Stahlbeton
AC_Pset_RenovationAndPhasing - Renovation Status: Existing
Pset_SlabCommon - IsExternal: yes; LoadBearing: yes
Material Properties - _SIWH - Beton, Stahlbeton, ThermalConductivity: 1.35; _SIWH - Beton, Stahlbeton, SpecificHeatCapacity: 1000 J/kg/K; _SIWH - Beton, Stahlbeton, MassDensity: 2000 kg/m3; _SIWH - Beton, Stahlbeton, Embodied Energy: 0.78 (MJ/kg); _SIWH - Beton, Stahlbeton, Embodied Carbon: 0.113 (kgCO₂/kg); _SIWH - Beton, Stahlbeton, Name: _SIWH - Beton, Stahlbeton; _SIWH - Beton, Stahlbeton, Participates in Collision Detection: yes

# IfcSlab: _SIWH - Beton, Stahlbeton 340, Decke006
In: Staffelgeschoss
Classification: Rohbaudecke (Archicad Klassifizierung); Material: _SIWH - Beton, Stahlbeton
Pset_SlabCommon - IsExternal: no; LoadBearing: yes
Material Properties - _SIWH - Beton, Stahlbeton, ThermalConductivity: 1.35; _SIWH - Beton, Stahlbeton, SpecificHeatCapacity: 1000 J/kg/K; _SIWH - Beton, Stahlbeton, MassDensity: 2000 kg/m3; _SIWH - Beton, Stahlbeton, Embodied Energy: 0.78 (MJ/kg); _SIWH - Beton, Stahlbeton, Embodied Carbon: 0.113 (kgCO₂/kg); _SIWH - Beton, Stahlbeton, Name: _SIWH - Beton, Stahlbeton; _SIWH - Beton, Stahlbeton, Participates in Collision Detection: yes
AC_Pset_RenovationAndPhasing - Renovation Status: Existing

# IfcSlab: _SIWH - Beton, Stahlbeton Polygon, Wand-026
In: Staffelgeschoss
Classification: Rohbaudecke (Archicad Klassifizierung); Material: _SIWH - Beton, Stahlbeton
AC_Pset_RenovationAndPhasing - Renovation Status: Existing
Pset_SlabCommon - IsExternal: yes; LoadBearing: yes
Material Properties - _SIWH - Beton, Stahlbeton, ThermalConductivity: 1.35; _SIWH - Beton, Stahlbeton, SpecificHeatCapacity: 1000 J/kg/K; _SIWH - Beton, Stahlbeton, MassDensity: 2000 kg/m3; _SIWH - Beton, Stahlbeton, Embodied Energy: 0.78 (MJ/kg); _SIWH - Beton, Stahlbeton, Embodied Carbon: 0.113 (kgCO₂/kg); _SIWH - Beton, Stahlbeton, Name: _SIWH - Beton, Stahlbeton; _SIWH - Beton, Stahlbeton, Participates in Collision Detection: yes

# IfcSlab: _SIWH - Dämmung, weich Mineralwolle 200, Decke021
In: Staffelgeschoss
Classification: Rohbaudecke (Archicad Klassifizierung); Material: _SIWH - Dämmung, weich Mineralwolle
AC_Pset_RenovationAndPhasing - Renovation Status: Existing
Material Properties - _SIWH - Dämmung, weich Mineralwolle, ThermalConductivity: 0.037; _SIWH - Dämmung, weich Mineralwolle, SpecificHeatCapacity: 840 J/kg/K; _SIWH - Dämmung, weich Mineralwolle, MassDensity: 40 kg/m3; _SIWH - Dämmung, weich Mineralwolle, Embodied Energy: 14.3 (MJ/kg); _SIWH - Dämmung, weich Mineralwolle, Embodied Carbon: 1.08 (kgCO₂/kg); _SIWH - Dämmung, weich Mineralwolle, Name: _SIWH - Dämmung, weich Mineralwolle; _SIWH - Dämmung, weich Mineralwolle, Participates in Collision Detection: yes
Pset_SlabCommon - IsExternal: no; LoadBearing: yes

# IfcSlab: _SIWH - Vordach Eingang 1 4035 x 310, Wand-024
In: Staffelgeschoss
Classification: Rohbaudecke (Archicad Klassifizierung); Material: _SIWH - Holz, Bauholz (4), _SIWH - Abgehängte Decke Arkade (3), _SIWH - Luftschicht vertikal (3), _SIWH - Dämmung, weich Mineralwolle
AC_Pset_RenovationAndPhasing - Renovation Status: Existing
Pset_SlabCommon - IsExternal: yes; LoadBearing: yes
Material Properties - _SIWH - Holz, Bauholz, ThermalConductivity: 0.13; _SIWH - Holz, Bauholz, SpecificHeatCapacity: 1600 J/kg/K; _SIWH - Holz, Bauholz, MassDensity: 500 kg/m3; _SIWH - Holz, Bauholz, Embodied Energy: 6.95 (MJ/kg); _SIWH - Holz, Bauholz, Embodied Carbon: 0.29 (kgCO₂/kg); _SIWH - Holz, Bauholz, Name: _SIWH - Holz, Bauholz; _SIWH - Holz, Bauholz, Participates in Collision Detection: yes; _SIWH - Abgehängte Decke Arkade, ThermalConductivity: 0.13; _SIWH - Abgehängte Decke Arkade, SpecificHeatCapacity: 1600 J/kg/K; _SIWH - Abgehängte Decke Arkade, MassDensity: 500 kg/m3; _SIWH - Abgehängte Decke Arkade, Embodied Energy: 13.1 (MJ/kg); _SIWH - Abgehängte Decke Arkade, Embodied Carbon: 0.64 (kgCO₂/kg); _SIWH - Abgehängte Decke Arkade, Name: _SIWH - Abgehängte Decke Arkade; _SIWH - Abgehängte Decke Arkade, Participates in Collision Detection: yes; _SIWH - Luftschicht vertikal, ThermalConductivity: 0.16; _SIWH - Luftschicht vertikal, SpecificHeatCapacity: 1008 J/kg/K; _SIWH - Luftschicht vertikal, MassDensity: 1.2 kg/m3; _SIWH - Luftschicht vertikal, Embodied Energy: 0 (MJ/kg); _SIWH - Luftschicht vertikal, Embodied Carbon: 0 (kgCO₂/kg); _SIWH - Luftschicht vertikal, Name: _SIWH - Luftschicht vertikal; _SIWH - Luftschicht vertikal, Participates in Collision Detection: no; _SIWH - Dämmung, weich Mineralwolle, ThermalConductivity: 0.037; _SIWH - Dämmung, weich Mineralwolle, SpecificHeatCapacity: 840 J/kg/K; _SIWH - Dämmung, weich Mineralwolle, MassDensity: 40 kg/m3; _SIWH - Dämmung, weich Mineralwolle, Embodied Energy: 14.3 (MJ/kg); _SIWH - Dämmung, weich Mineralwolle, Embodied Carbon: 1.08 (kgCO₂/kg); _SIWH - Dämmung, weich Mineralwolle, Name: _SIWH - Dämmung, weich Mineralwolle; _SIWH - Dämmung, weich Mineralwolle, Participates in Collision Detection: yes

# IfcSlab: _SIWH - Vordach Eingang 2 2720 x 310 (2)
In: Staffelgeschoss
Classification: Rohbaudecke (Archicad Klassifizierung); Material: _SIWH - Abgehängte Decke Arkade (3), _SIWH - Holz, Bauholz (2), _SIWH - Luftschicht vertikal (2), _SIWH - Dämmung, weich Mineralwolle
AC_Pset_RenovationAndPhasing - Renovation Status: Existing
Pset_SlabCommon - IsExternal: yes; LoadBearing: yes
Material Properties - _SIWH - Abgehängte Decke Arkade, ThermalConductivity: 0.13; _SIWH - Abgehängte Decke Arkade, SpecificHeatCapacity: 1600 J/kg/K; _SIWH - Abgehängte Decke Arkade, MassDensity: 500 kg/m3; _SIWH - Abgehängte Decke Arkade, Embodied Energy: 13.1 (MJ/kg); _SIWH - Abgehängte Decke Arkade, Embodied Carbon: 0.64 (kgCO₂/kg); _SIWH - Abgehängte Decke Arkade, Name: _SIWH - Abgehängte Decke Arkade; _SIWH - Abgehängte Decke Arkade, Participates in Collision Detection: yes; _SIWH - Holz, Bauholz, ThermalConductivity: 0.13; _SIWH - Holz, Bauholz, SpecificHeatCapacity: 1600 J/kg/K; _SIWH - Holz, Bauholz, MassDensity: 500 kg/m3; _SIWH - Holz, Bauholz, Embodied Energy: 6.95 (MJ/kg); _SIWH - Holz, Bauholz, Embodied Carbon: 0.29 (kgCO₂/kg); _SIWH - Holz, Bauholz, Name: _SIWH - Holz, Bauholz; _SIWH - Holz, Bauholz, Participates in Collision Detection: yes; _SIWH - Luftschicht vertikal, ThermalConductivity: 0.16; _SIWH - Luftschicht vertikal, SpecificHeatCapacity: 1008 J/kg/K; _SIWH - Luftschicht vertikal, MassDensity: 1.2 kg/m3; _SIWH - Luftschicht vertikal, Embodied Energy: 0 (MJ/kg); _SIWH - Luftschicht vertikal, Embodied Carbon: 0 (kgCO₂/kg); _SIWH - Luftschicht vertikal, Name: _SIWH - Luftschicht vertikal; _SIWH - Luftschicht vertikal, Participates in Collision Detection: no; _SIWH - Dämmung, weich Mineralwolle, ThermalConductivity: 0.037; _SIWH - Dämmung, weich Mineralwolle, SpecificHeatCapacity: 840 J/kg/K; _SIWH - Dämmung, weich Mineralwolle, MassDensity: 40 kg/m3; _SIWH - Dämmung, weich Mineralwolle, Embodied Energy: 14.3 (MJ/kg); _SIWH - Dämmung, weich Mineralwolle, Embodied Carbon: 1.08 (kgCO₂/kg); _SIWH - Dämmung, weich Mineralwolle, Name: _SIWH - Dämmung, weich Mineralwolle; _SIWH - Dämmung, weich Mineralwolle, Participates in Collision Detection: yes

# IfcSlab: _SIWH - Vordach Luftbalken2 410 x 980, Wand-024
In: Staffelgeschoss
Classification: Rohbaudecke (Archicad Klassifizierung); Material: _SIWH - Metall, Aluminium, _SIWH - Beton, Stahlbeton Fertigteil
AC_Pset_RenovationAndPhasing - Renovation Status: Existing
Pset_SlabCommon - IsExternal: yes; LoadBearing: yes
Material Properties - _SIWH - Metall, Aluminium, ThermalConductivity: 160; _SIWH - Metall, Aluminium, SpecificHeatCapacity: 880 J/kg/K; _SIWH - Metall, Aluminium, MassDensity: 2800 kg/m3; _SIWH - Metall, Aluminium, Embodied Energy: 155 (MJ/kg); _SIWH - Metall, Aluminium, Embodied Carbon: 9.16 (kgCO₂/kg); _SIWH - Metall, Aluminium, Name: _SIWH - Metall, Aluminium; _SIWH - Metall, Aluminium, Participates in Collision Detection: yes; _SIWH - Beton, Stahlbeton Fertigteil, ThermalConductivity: 1.15; _SIWH - Beton, Stahlbeton Fertigteil, SpecificHeatCapacity: 1000 J/kg/K; _SIWH - Beton, Stahlbeton Fertigteil, MassDensity: 1800 kg/m3; _SIWH - Beton, Stahlbeton Fertigteil, Embodied Energy: 0.74 (MJ/kg); _SIWH - Beton, Stahlbeton Fertigteil, Embodied Carbon: 0.107 (kgCO₂/kg); _SIWH - Beton, Stahlbeton Fertigteil, Name: _SIWH - Beton, Stahlbeton Fertigteil; _SIWH - Beton, Stahlbeton Fertigteil, Participates in Collision Detection: yes

# IfcSlab: _SIWH - Vordach+Arkade1 1555 x 980 (3)
In: Staffelgeschoss
Classification: Rohbaudecke (Archicad Klassifizierung); Material: _SIWH - Metall, Aluminium, _SIWH - Beton, Stahlbeton Fertigteil, _SIWH - Beton, Stahlbeton, _SIWH - Dämmung, weich Mineralwolle
AC_Pset_RenovationAndPhasing - Renovation Status: Existing
Material Properties - _SIWH - Metall, Aluminium, ThermalConductivity: 160; _SIWH - Metall, Aluminium, SpecificHeatCapacity: 880 J/kg/K; _SIWH - Metall, Aluminium, MassDensity: 2800 kg/m3; _SIWH - Metall, Aluminium, Embodied Energy: 155 (MJ/kg); _SIWH - Metall, Aluminium, Embodied Carbon: 9.16 (kgCO₂/kg); _SIWH - Metall, Aluminium, Name: _SIWH - Metall, Aluminium; _SIWH - Metall, Aluminium, Participates in Collision Detection: yes; _SIWH - Beton, Stahlbeton Fertigteil, ThermalConductivity: 1.15; _SIWH - Beton, Stahlbeton Fertigteil, SpecificHeatCapacity: 1000 J/kg/K; _SIWH - Beton, Stahlbeton Fertigteil, MassDensity: 1800 kg/m3; _SIWH - Beton, Stahlbeton Fertigteil, Embodied Energy: 0.74 (MJ/kg); _SIWH - Beton, Stahlbeton Fertigteil, Embodied Carbon: 0.107 (kgCO₂/kg); _SIWH - Beton, Stahlbeton Fertigteil, Name: _SIWH - Beton, Stahlbeton Fertigteil; _SIWH - Beton, Stahlbeton Fertigteil, Participates in Collision Detection: yes; _SIWH - Beton, Stahlbeton, ThermalConductivity: 1.35; _SIWH - Beton, Stahlbeton, SpecificHeatCapacity: 1000 J/kg/K; _SIWH - Beton, Stahlbeton, MassDensity: 2000 kg/m3; _SIWH - Beton, Stahlbeton, Embodied Energy: 0.78 (MJ/kg); _SIWH - Beton, Stahlbeton, Embodied Carbon: 0.113 (kgCO₂/kg); _SIWH - Beton, Stahlbeton, Name: _SIWH - Beton, Stahlbeton; _SIWH - Beton, Stahlbeton, Participates in Collision Detection: yes; _SIWH - Dämmung, weich Mineralwolle, ThermalConductivity: 0.037; _SIWH - Dämmung, weich Mineralwolle, SpecificHeatCapacity: 840 J/kg/K; _SIWH - Dämmung, weich Mineralwolle, MassDensity: 40 kg/m3; _SIWH - Dämmung, weich Mineralwolle, Embodied Energy: 14.3 (MJ/kg); _SIWH - Dämmung, weich Mineralwolle, Embodied Carbon: 1.08 (kgCO₂/kg); _SIWH - Dämmung, weich Mineralwolle, Name: _SIWH - Dämmung, weich Mineralwolle; _SIWH - Dämmung, weich Mineralwolle, Participates in Collision Detection: yes
Pset_SlabCommon - IsExternal: yes; LoadBearing: yes

# IfcSlab: _SIWH - Vordach+Arkade2 1555 x 980, Wand-024
In: Staffelgeschoss
Classification: Rohbaudecke (Archicad Klassifizierung); Material: _SIWH - Metall, Aluminium, _SIWH - Beton, Stahlbeton Fertigteil, _SIWH - Beton, Stahlbeton, _SIWH - Dämmung, weich Mineralwolle
AC_Pset_RenovationAndPhasing - Renovation Status: Existing
Pset_SlabCommon - IsExternal: yes; LoadBearing: yes
Material Properties - _SIWH - Metall, Aluminium, ThermalConductivity: 160; _SIWH - Metall, Aluminium, SpecificHeatCapacity: 880 J/kg/K; _SIWH - Metall, Aluminium, MassDensity: 2800 kg/m3; _SIWH - Metall, Aluminium, Embodied Energy: 155 (MJ/kg); _SIWH - Metall, Aluminium, Embodied Carbon: 9.16 (kgCO₂/kg); _SIWH - Metall, Aluminium, Name: _SIWH - Metall, Aluminium; _SIWH - Metall, Aluminium, Participates in Collision Detection: yes; _SIWH - Beton, Stahlbeton Fertigteil, ThermalConductivity: 1.15; _SIWH - Beton, Stahlbeton Fertigteil, SpecificHeatCapacity: 1000 J/kg/K; _SIWH - Beton, Stahlbeton Fertigteil, MassDensity: 1800 kg/m3; _SIWH - Beton, Stahlbeton Fertigteil, Embodied Energy: 0.74 (MJ/kg); _SIWH - Beton, Stahlbeton Fertigteil, Embodied Carbon: 0.107 (kgCO₂/kg); _SIWH - Beton, Stahlbeton Fertigteil, Name: _SIWH - Beton, Stahlbeton Fertigteil; _SIWH - Beton, Stahlbeton Fertigteil, Participates in Collision Detection: yes; _SIWH - Beton, Stahlbeton, ThermalConductivity: 1.35; _SIWH - Beton, Stahlbeton, SpecificHeatCapacity: 1000 J/kg/K; _SIWH - Beton, Stahlbeton, MassDensity: 2000 kg/m3; _SIWH - Beton, Stahlbeton, Embodied Energy: 0.78 (MJ/kg); _SIWH - Beton, Stahlbeton, Embodied Carbon: 0.113 (kgCO₂/kg); _SIWH - Beton, Stahlbeton, Name: _SIWH - Beton, Stahlbeton; _SIWH - Beton, Stahlbeton, Participates in Collision Detection: yes; _SIWH - Dämmung, weich Mineralwolle, ThermalConductivity: 0.037; _SIWH - Dämmung, weich Mineralwolle, SpecificHeatCapacity: 840 J/kg/K; _SIWH - Dämmung, weich Mineralwolle, MassDensity: 40 kg/m3; _SIWH - Dämmung, weich Mineralwolle, Embodied Energy: 14.3 (MJ/kg); _SIWH - Dämmung, weich Mineralwolle, Embodied Carbon: 1.08 (kgCO₂/kg); _SIWH - Dämmung, weich Mineralwolle, Name: _SIWH - Dämmung, weich Mineralwolle; _SIWH - Dämmung, weich Mineralwolle, Participates in Collision Detection: yes

# IfcSlab: _SIWH - Vordach+Arkade2 nur Luftbalken 210 x 650, Wand-024
In: Staffelgeschoss
Classification: Rohbaudecke (Archicad Klassifizierung); Material: _SIWH - Metall, Aluminium, _SIWH - Beton, Stahlbeton Fertigteil
AC_Pset_RenovationAndPhasing - Renovation Status: Existing
Pset_SlabCommon - IsExternal: yes; LoadBearing: yes
Material Properties - _SIWH - Metall, Aluminium, ThermalConductivity: 160; _SIWH - Metall, Aluminium, SpecificHeatCapacity: 880 J/kg/K; _SIWH - Metall, Aluminium, MassDensity: 2800 kg/m3; _SIWH - Metall, Aluminium, Embodied Energy: 155 (MJ/kg); _SIWH - Metall, Aluminium, Embodied Carbon: 9.16 (kgCO₂/kg); _SIWH - Metall, Aluminium, Name: _SIWH - Metall, Aluminium; _SIWH - Metall, Aluminium, Participates in Collision Detection: yes; _SIWH - Beton, Stahlbeton Fertigteil, ThermalConductivity: 1.15; _SIWH - Beton, Stahlbeton Fertigteil, SpecificHeatCapacity: 1000 J/kg/K; _SIWH - Beton, Stahlbeton Fertigteil, MassDensity: 1800 kg/m3; _SIWH - Beton, Stahlbeton Fertigteil, Embodied Energy: 0.74 (MJ/kg); _SIWH - Beton, Stahlbeton Fertigteil, Embodied Carbon: 0.107 (kgCO₂/kg); _SIWH - Beton, Stahlbeton Fertigteil, Name: _SIWH - Beton, Stahlbeton Fertigteil; _SIWH - Beton, Stahlbeton Fertigteil, Participates in Collision Detection: yes

# IfcSlab: _SIWH - Vordach+Arkade3 1395 x 980, Wand-024
In: Staffelgeschoss
Classification: Rohbaudecke (Archicad Klassifizierung); Material: _SIWH - Metall, Aluminium, _SIWH - Beton, Stahlbeton Fertigteil, _SIWH - Beton, Stahlbeton, _SIWH - Dämmung, weich Mineralwolle
AC_Pset_RenovationAndPhasing - Renovation Status: Existing
Pset_SlabCommon - IsExternal: yes; LoadBearing: yes
Material Properties - _SIWH - Metall, Aluminium, ThermalConductivity: 160; _SIWH - Metall, Aluminium, SpecificHeatCapacity: 880 J/kg/K; _SIWH - Metall, Aluminium, MassDensity: 2800 kg/m3; _SIWH - Metall, Aluminium, Embodied Energy: 155 (MJ/kg); _SIWH - Metall, Aluminium, Embodied Carbon: 9.16 (kgCO₂/kg); _SIWH - Metall, Aluminium, Name: _SIWH - Metall, Aluminium; _SIWH - Metall, Aluminium, Participates in Collision Detection: yes; _SIWH - Beton, Stahlbeton Fertigteil, ThermalConductivity: 1.15; _SIWH - Beton, Stahlbeton Fertigteil, SpecificHeatCapacity: 1000 J/kg/K; _SIWH - Beton, Stahlbeton Fertigteil, MassDensity: 1800 kg/m3; _SIWH - Beton, Stahlbeton Fertigteil, Embodied Energy: 0.74 (MJ/kg); _SIWH - Beton, Stahlbeton Fertigteil, Embodied Carbon: 0.107 (kgCO₂/kg); _SIWH - Beton, Stahlbeton Fertigteil, Name: _SIWH - Beton, Stahlbeton Fertigteil; _SIWH - Beton, Stahlbeton Fertigteil, Participates in Collision Detection: yes; _SIWH - Beton, Stahlbeton, ThermalConductivity: 1.35; _SIWH - Beton, Stahlbeton, SpecificHeatCapacity: 1000 J/kg/K; _SIWH - Beton, Stahlbeton, MassDensity: 2000 kg/m3; _SIWH - Beton, Stahlbeton, Embodied Energy: 0.78 (MJ/kg); _SIWH - Beton, Stahlbeton, Embodied Carbon: 0.113 (kgCO₂/kg); _SIWH - Beton, Stahlbeton, Name: _SIWH - Beton, Stahlbeton; _SIWH - Beton, Stahlbeton, Participates in Collision Detection: yes; _SIWH - Dämmung, weich Mineralwolle, ThermalConductivity: 0.037; _SIWH - Dämmung, weich Mineralwolle, SpecificHeatCapacity: 840 J/kg/K; _SIWH - Dämmung, weich Mineralwolle, MassDensity: 40 kg/m3; _SIWH - Dämmung, weich Mineralwolle, Embodied Energy: 14.3 (MJ/kg); _SIWH - Dämmung, weich Mineralwolle, Embodied Carbon: 1.08 (kgCO₂/kg); _SIWH - Dämmung, weich Mineralwolle, Name: _SIWH - Dämmung, weich Mineralwolle; _SIWH - Dämmung, weich Mineralwolle, Participates in Collision Detection: yes

# IfcSlab: _SIWH - Vordach+Arkade3 nur Luftbalken 210 x 980 (2)
In: Staffelgeschoss
Classification: Rohbaudecke (Archicad Klassifizierung); Material: _SIWH - Metall, Aluminium, _SIWH - Beton, Stahlbeton Fertigteil
AC_Pset_RenovationAndPhasing - Renovation Status: Existing
Pset_SlabCommon - IsExternal: yes; LoadBearing: yes
Material Properties - _SIWH - Metall, Aluminium, ThermalConductivity: 160; _SIWH - Metall, Aluminium, SpecificHeatCapacity: 880 J/kg/K; _SIWH - Metall, Aluminium, MassDensity: 2800 kg/m3; _SIWH - Metall, Aluminium, Embodied Energy: 155 (MJ/kg); _SIWH - Metall, Aluminium, Embodied Carbon: 9.16 (kgCO₂/kg); _SIWH - Metall, Aluminium, Name: _SIWH - Metall, Aluminium; _SIWH - Metall, Aluminium, Participates in Collision Detection: yes; _SIWH - Beton, Stahlbeton Fertigteil, ThermalConductivity: 1.15; _SIWH - Beton, Stahlbeton Fertigteil, SpecificHeatCapacity: 1000 J/kg/K; _SIWH - Beton, Stahlbeton Fertigteil, MassDensity: 1800 kg/m3; _SIWH - Beton, Stahlbeton Fertigteil, Embodied Energy: 0.74 (MJ/kg); _SIWH - Beton, Stahlbeton Fertigteil, Embodied Carbon: 0.107 (kgCO₂/kg); _SIWH - Beton, Stahlbeton Fertigteil, Name: _SIWH - Beton, Stahlbeton Fertigteil; _SIWH - Beton, Stahlbeton Fertigteil, Participates in Collision Detection: yes

# IfcWall: ALLGEMEIN - BAUTEIL 125, L-Wand036
In: Erdgeschoss
Classification: Vorwand / Installationswand (Archicad Klassifizierung); Material: ALLGEMEIN - BAUTEIL
AC_Pset_RenovationAndPhasing - Renovation Status: Existing
Pset_WallCommon - IsExternal: no; LoadBearing: no
Material Properties - ALLGEMEIN - BAUTEIL, ThermalConductivity: 0.13; ALLGEMEIN - BAUTEIL, SpecificHeatCapacity: 1600 J/kg/K; ALLGEMEIN - BAUTEIL, MassDensity: 500 kg/m3; ALLGEMEIN - BAUTEIL, Embodied Energy: 13.1 (MJ/kg); ALLGEMEIN - BAUTEIL, Embodied Carbon: 0.64 (kgCO₂/kg); ALLGEMEIN - BAUTEIL, Name: ALLGEMEIN - BAUTEIL; ALLGEMEIN - BAUTEIL, Participates in Collision Detection: yes

# IfcWall: Glas, Normalglas-50% durchlässig 30, L-Wand033
In: Staffelgeschoss
Classification: Trennwand (Archicad Klassifizierung); Material: Glas, Normalglas-50% durchlässig
AC_Pset_RenovationAndPhasing - Renovation Status: Existing
Pset_WallCommon - IsExternal: no; LoadBearing: no
Material Properties - Glas, Normalglas-50% durchlässig, ThermalConductivity: 1.4; Glas, Normalglas-50% durchlässig, SpecificHeatCapacity: 750 J/kg/K; Glas, Normalglas-50% durchlässig, MassDensity: 2200 kg/m3; Glas, Normalglas-50% durchlässig, Embodied Energy: 0.85 (MJ/kg); Glas, Normalglas-50% durchlässig, Embodied Carbon: 0.02 (kgCO₂/kg); Glas, Normalglas-50% durchlässig, Name: Glas, Normalglas-50% durchlässig; Glas, Normalglas-50% durchlässig, Participates in Collision Detection: yes

# IfcWall: Wandabschluss 02 26 (2)
In: Staffelgeschoss
Classification: Vorwand / Installationswand (Archicad Klassifizierung); Material: _SIWH - Gipskarton
AC_Pset_RenovationAndPhasing - Renovation Status: Existing
Material Properties - _SIWH - Gipskarton, ThermalConductivity: 0.25; _SIWH - Gipskarton, SpecificHeatCapacity: 1000 J/kg/K; _SIWH - Gipskarton, MassDensity: 900 kg/m3; _SIWH - Gipskarton, Embodied Energy: 6.75 (MJ/kg); _SIWH - Gipskarton, Embodied Carbon: 0.39 (kgCO₂/kg); _SIWH - Gipskarton, Name: _SIWH - Gipskarton; _SIWH - Gipskarton, Participates in Collision Detection: yes

# IfcWall: _SIWH - Attika 1.OG 635 x 625 (4)
In: Dachaufsicht
Classification: Wand (Archicad Klassifizierung)
AC_Pset_RenovationAndPhasing - Renovation Status: Existing
Pset_WallCommon - IsExternal: yes; LoadBearing: yes
Material Properties - _SIWH - Dämmung, hart Mineralwolle, ThermalConductivity: 0.036; _SIWH - Dämmung, hart Mineralwolle, SpecificHeatCapacity: 840 J/kg/K; _SIWH - Dämmung, hart Mineralwolle, MassDensity: 115 kg/m3; _SIWH - Dämmung, hart Mineralwolle, Embodied Energy: 21.4 (MJ/kg); _SIWH - Dämmung, hart Mineralwolle, Embodied Carbon: 1.69 (kgCO₂/kg); _SIWH - Dämmung, hart Mineralwolle, Name: _SIWH - Dämmung, hart Mineralwolle; _SIWH - Dämmung, hart Mineralwolle, Participates in Collision Detection: yes; _SIWH - Beton, Stahlbeton, ThermalConductivity: 1.35; _SIWH - Beton, Stahlbeton, SpecificHeatCapacity: 1000 J/kg/K; _SIWH - Beton, Stahlbeton, MassDensity: 2000 kg/m3; _SIWH - Beton, Stahlbeton, Embodied Energy: 0.78 (MJ/kg); _SIWH - Beton, Stahlbeton, Embodied Carbon: 0.113 (kgCO₂/kg); _SIWH - Beton, Stahlbeton, Name: _SIWH - Beton, Stahlbeton; _SIWH - Beton, Stahlbeton, Participates in Collision Detection: yes; _SIWH - Holz, Bauholz, ThermalConductivity: 0.13; _SIWH - Holz, Bauholz, SpecificHeatCapacity: 1600 J/kg/K; _SIWH - Holz, Bauholz, MassDensity: 500 kg/m3; _SIWH - Holz, Bauholz, Embodied Energy: 6.95 (MJ/kg); _SIWH - Holz, Bauholz, Embodied Carbon: 0.29 (kgCO₂/kg); _SIWH - Holz, Bauholz, Name: _SIWH - Holz, Bauholz; _SIWH - Holz, Bauholz, Participates in Collision Detection: yes; _SIWH - Dämmung, weich Mineralwolle, ThermalConductivity: 0.037; _SIWH - Dämmung, weich Mineralwolle, SpecificHeatCapacity: 840 J/kg/K; _SIWH - Dämmung, weich Mineralwolle, MassDensity: 40 kg/m3; _SIWH - Dämmung, weich Mineralwolle, Embodied Energy: 14.3 (MJ/kg); _SIWH - Dämmung, weich Mineralwolle, Embodied Carbon: 1.08 (kgCO₂/kg); _SIWH - Dämmung, weich Mineralwolle, Name: _SIWH - Dämmung, weich Mineralwolle; _SIWH - Dämmung, weich Mineralwolle, Participates in Collision Detection: yes; _SIWH - Luftschicht vertikal, ThermalConductivity: 0.16; _SIWH - Luftschicht vertikal, SpecificHeatCapacity: 1008 J/kg/K; _SIWH - Luftschicht vertikal, MassDensity: 1.2 kg/m3; _SIWH - Luftschicht vertikal, Embodied Energy: 0 (MJ/kg); _SIWH - Luftschicht vertikal, Embodied Carbon: 0 (kgCO₂/kg); _SIWH - Luftschicht vertikal, Name: _SIWH - Luftschicht vertikal; _SIWH - Luftschicht vertikal, Participates in Collision Detection: no; _SIWH - MW Vormauerziegel, ThermalConductivity: 0.109; _SIWH - MW Vormauerziegel, SpecificHeatCapacity: 920 J/kg/K; _SIWH - MW Vormauerziegel, MassDensity: 600 kg/m3; _SIWH - MW Vormauerziegel, Embodied Energy: 6 (MJ/kg); _SIWH - MW Vormauerziegel, Embodied Carbon: 0.48 (kgCO₂/kg); _SIWH - MW Vormauerziegel, Name: _SIWH - MW Vormauerziegel; _SIWH - MW Vormauerziegel, Participates in Collision Detection: yes; _SIWH - Metall, Aluminium, ThermalConductivity: 160; _SIWH - Metall, Aluminium, SpecificHeatCapacity: 880 J/kg/K; _SIWH - Metall, Aluminium, MassDensity: 2800 kg/m3; _SIWH - Metall, Aluminium, Embodied Energy: 155 (MJ/kg); _SIWH - Metall, Aluminium, Embodied Carbon: 9.16 (kgCO₂/kg); _SIWH - Metall, Aluminium, Name: _SIWH - Metall, Aluminium; _SIWH - Metall, Aluminium, Participates in Collision Detection: yes
Name | Material
A-Wand030 | _SIWH - Dämmung, hart Mineralwolle, _SIWH - Beton, Stahlbeton, _SIWH - Holz, Bauholz, _SIWH - Dämmung, weich Mineralwolle, _SIWH - Luftschicht vertikal, _SIWH - MW Vormauerziegel, _SIWH - Metall, Aluminium
A-Wand031 | _SIWH - Dämmung, hart Mineralwolle, _SIWH - Beton, Stahlbeton, _SIWH - Holz, Bauholz, _SIWH - Dämmung, weich Mineralwolle, _SIWH - Luftschicht vertikal, _SIWH - MW Vormauerziegel, _SIWH - Metall, Aluminium
A-Wand032 | _SIWH - Dämmung, hart Mineralwolle, _SIWH - Beton, Stahlbeton, _SIWH - Holz, Bauholz, _SIWH - Dämmung, weich Mineralwolle, _SIWH - Luftschicht vertikal, _SIWH - MW Vormauerziegel, _SIWH - Metall, Aluminium
A-Wand033 | _SIWH - Metall, Aluminium, _SIWH - MW Vormauerziegel, _SIWH - Luftschicht vertikal, _SIWH - Dämmung, weich Mineralwolle, _SIWH - Beton, Stahlbeton, _SIWH - Dämmung, hart Mineralwolle, _SIWH - Holz, Bauholz

# IfcWall: _SIWH - Attikablech2 Achse3 EG 660 x 65, Wand-028
In: Staffelgeschoss
Classification: Wand (Archicad Klassifizierung); Material: _SIWH - Metall, Aluminium
AC_Pset_RenovationAndPhasing - Renovation Status: Existing
Material Properties - _SIWH - Metall, Aluminium, ThermalConductivity: 160; _SIWH - Metall, Aluminium, SpecificHeatCapacity: 880 J/kg/K; _SIWH - Metall, Aluminium, MassDensity: 2800 kg/m3; _SIWH - Metall, Aluminium, Embodied Energy: 155 (MJ/kg); _SIWH - Metall, Aluminium, Embodied Carbon: 9.16 (kgCO₂/kg); _SIWH - Metall, Aluminium, Name: _SIWH - Metall, Aluminium; _SIWH - Metall, Aluminium, Participates in Collision Detection: yes
Pset_WallCommon - IsExternal: yes; LoadBearing: yes

# IfcWall: _SIWH - Beton, Stahlbeton 200, A-Wand034
In: Erdgeschoss
Classification: Wand (Archicad Klassifizierung); Material: _SIWH - Beton, Stahlbeton
AC_Pset_RenovationAndPhasing - Renovation Status: Existing
Pset_WallCommon - IsExternal: yes; LoadBearing: yes
Material Properties - _SIWH - Beton, Stahlbeton, ThermalConductivity: 1.35; _SIWH - Beton, Stahlbeton, SpecificHeatCapacity: 1000 J/kg/K; _SIWH - Beton, Stahlbeton, MassDensity: 2000 kg/m3; _SIWH - Beton, Stahlbeton, Embodied Energy: 0.78 (MJ/kg); _SIWH - Beton, Stahlbeton, Embodied Carbon: 0.113 (kgCO₂/kg); _SIWH - Beton, Stahlbeton, Name: _SIWH - Beton, Stahlbeton; _SIWH - Beton, Stahlbeton, Participates in Collision Detection: yes

# IfcWall: _SIWH - Beton, Stahlbeton 240 (2)
In: Erdgeschoss
Classification: Wand (Archicad Klassifizierung); Material: _SIWH - Beton, Stahlbeton
AC_Pset_RenovationAndPhasing - Renovation Status: Existing
Material Properties - _SIWH - Beton, Stahlbeton, ThermalConductivity: 1.35; _SIWH - Beton, Stahlbeton, SpecificHeatCapacity: 1000 J/kg/K; _SIWH - Beton, Stahlbeton, MassDensity: 2000 kg/m3; _SIWH - Beton, Stahlbeton, Embodied Energy: 0.78 (MJ/kg); _SIWH - Beton, Stahlbeton, Embodied Carbon: 0.113 (kgCO₂/kg); _SIWH - Beton, Stahlbeton, Name: _SIWH - Beton, Stahlbeton; _SIWH - Beton, Stahlbeton, Participates in Collision Detection: yes
Pset_WallCommon - IsExternal: yes; LoadBearing: yes
Name
A-Wand052
A-Wand053

# IfcWall: _SIWH - Beton, Stahlbeton 240 x 930, Unterzug-014
In: Erdgeschoss
Classification: Wand (Archicad Klassifizierung); Material: _SIWH - Beton, Stahlbeton
Pset_WallCommon - IsExternal: yes; LoadBearing: yes
AC_Pset_RenovationAndPhasing - Renovation Status: Existing
Material Properties - _SIWH - Beton, Stahlbeton, ThermalConductivity: 1.35; _SIWH - Beton, Stahlbeton, SpecificHeatCapacity: 1000 J/kg/K; _SIWH - Beton, Stahlbeton, MassDensity: 2000 kg/m3; _SIWH - Beton, Stahlbeton, Embodied Energy: 0.78 (MJ/kg); _SIWH - Beton, Stahlbeton, Embodied Carbon: 0.113 (kgCO₂/kg); _SIWH - Beton, Stahlbeton, Name: _SIWH - Beton, Stahlbeton; _SIWH - Beton, Stahlbeton, Participates in Collision Detection: yes

# IfcWall: _SIWH - Beton, Stahlbeton Fertigteil 70, Decke025
In: Kellergeschoss
Classification: Elementwand (Archicad Klassifizierung); Material: _SIWH - Beton, Stahlbeton Fertigteil
AC_Pset_RenovationAndPhasing - Renovation Status: Existing
Pset_WallCommon - IsExternal: yes; LoadBearing: no
Material Properties - _SIWH - Beton, Stahlbeton Fertigteil, ThermalConductivity: 1.15; _SIWH - Beton, Stahlbeton Fertigteil, SpecificHeatCapacity: 1000 J/kg/K; _SIWH - Beton, Stahlbeton Fertigteil, MassDensity: 1800 kg/m3; _SIWH - Beton, Stahlbeton Fertigteil, Embodied Energy: 0.74 (MJ/kg); _SIWH - Beton, Stahlbeton Fertigteil, Embodied Carbon: 0.107 (kgCO₂/kg); _SIWH - Beton, Stahlbeton Fertigteil, Name: _SIWH - Beton, Stahlbeton Fertigteil; _SIWH - Beton, Stahlbeton Fertigteil, Participates in Collision Detection: yes

# IfcWall: _SIWH - Dämmung, hart Mineralwolle 70, Decke024
In: Kellergeschoss
Classification: Elementwand (Archicad Klassifizierung); Material: _SIWH - Dämmung, hart Mineralwolle
AC_Pset_RenovationAndPhasing - Renovation Status: Existing
Material Properties - _SIWH - Dämmung, hart Mineralwolle, ThermalConductivity: 0.036; _SIWH - Dämmung, hart Mineralwolle, SpecificHeatCapacity: 840 J/kg/K; _SIWH - Dämmung, hart Mineralwolle, MassDensity: 115 kg/m3; _SIWH - Dämmung, hart Mineralwolle, Embodied Energy: 21.4 (MJ/kg); _SIWH - Dämmung, hart Mineralwolle, Embodied Carbon: 1.69 (kgCO₂/kg); _SIWH - Dämmung, hart Mineralwolle, Name: _SIWH - Dämmung, hart Mineralwolle; _SIWH - Dämmung, hart Mineralwolle, Participates in Collision Detection: yes
Pset_WallCommon - IsExternal: yes; LoadBearing: no

# IfcWall: _SIWH - Dämmung, weich Mineralwolle 180, A-Wand066
In: Staffelgeschoss
Classification: Wand (Archicad Klassifizierung); Material: _SIWH - Dämmung, weich Mineralwolle
AC_Pset_RenovationAndPhasing - Renovation Status: Existing
Pset_WallCommon - IsExternal: yes; LoadBearing: yes
Material Properties - _SIWH - Dämmung, weich Mineralwolle, ThermalConductivity: 0.037; _SIWH - Dämmung, weich Mineralwolle, SpecificHeatCapacity: 840 J/kg/K; _SIWH - Dämmung, weich Mineralwolle, MassDensity: 40 kg/m3; _SIWH - Dämmung, weich Mineralwolle, Embodied Energy: 14.3 (MJ/kg); _SIWH - Dämmung, weich Mineralwolle, Embodied Carbon: 1.08 (kgCO₂/kg); _SIWH - Dämmung, weich Mineralwolle, Name: _SIWH - Dämmung, weich Mineralwolle; _SIWH - Dämmung, weich Mineralwolle, Participates in Collision Detection: yes

# IfcWall: _SIWH - Dämmung, weich Mineralwolle, hohe Priorität 180, A-Wand065
In: Staffelgeschoss
Classification: Wand (Archicad Klassifizierung); Material: _SIWH - Dämmung, weich Mineralwolle, hohe Priorität
AC_Pset_RenovationAndPhasing - Renovation Status: Existing
Pset_WallCommon - IsExternal: yes; LoadBearing: yes
Material Properties - _SIWH - Dämmung, weich Mineralwolle, hohe Priorität, ThermalConductivity: 0.037; _SIWH - Dämmung, weich Mineralwolle, hohe Priorität, SpecificHeatCapacity: 840 J/kg/K; _SIWH - Dämmung, weich Mineralwolle, hohe Priorität, MassDensity: 40 kg/m3; _SIWH - Dämmung, weich Mineralwolle, hohe Priorität, Embodied Energy: 14.3 (MJ/kg); _SIWH - Dämmung, weich Mineralwolle, hohe Priorität, Embodied Carbon: 1.08 (kgCO₂/kg); _SIWH - Dämmung, weich Mineralwolle, hohe Priorität, Name: _SIWH - Dämmung, weich Mineralwolle, hohe Priorität; _SIWH - Dämmung, weich Mineralwolle, hohe Priorität, Participates in Collision Detection: yes

# IfcWall: _SIWH - Glas, Normalglas 30 (2)
In: Staffelgeschoss
Classification: Trennwand (Archicad Klassifizierung); Material: _SIWH - Glas, Normalglas
AC_Pset_RenovationAndPhasing - Renovation Status: Existing
Material Properties - _SIWH - Glas, Normalglas, ThermalConductivity: 1.4; _SIWH - Glas, Normalglas, SpecificHeatCapacity: 750 J/kg/K; _SIWH - Glas, Normalglas, MassDensity: 2200 kg/m3; _SIWH - Glas, Normalglas, Embodied Energy: 0.85 (MJ/kg); _SIWH - Glas, Normalglas, Embodied Carbon: 0.02 (kgCO₂/kg); _SIWH - Glas, Normalglas, Name: _SIWH - Glas, Normalglas; _SIWH - Glas, Normalglas, Participates in Collision Detection: yes
Name
L-Wand047
L-Wand046

# IfcWall: _SIWH - MW Kalksandstein, nichttragend 120, L-Wand045
In: Staffelgeschoss
Classification: Wand (Archicad Klassifizierung); Material: _SIWH - MW Kalksandstein, nichttragend
AC_Pset_RenovationAndPhasing - Renovation Status: Existing
Pset_WallCommon - IsExternal: no; LoadBearing: no
Material Properties - _SIWH - MW Kalksandstein, nichttragend, ThermalConductivity: 0.93; _SIWH - MW Kalksandstein, nichttragend, SpecificHeatCapacity: 840 J/kg/K; _SIWH - MW Kalksandstein, nichttragend, MassDensity: 1800 kg/m3; _SIWH - MW Kalksandstein, nichttragend, Embodied Energy: 1.2 (MJ/kg); _SIWH - MW Kalksandstein, nichttragend, Embodied Carbon: 0.07 (kgCO₂/kg); _SIWH - MW Kalksandstein, nichttragend, Name: _SIWH - MW Kalksandstein, nichttragend; _SIWH - MW Kalksandstein, nichttragend, Participates in Collision Detection: yes

# IfcWall: _SIWH - Sturz Außenwand EG - Stb. 20cm 515 x 280, A-Wand020
In: Erdgeschoss
Classification: Wand (Archicad Klassifizierung); Material: _SIWH - MW Vormauerziegel, _SIWH - Luftschicht vertikal, _SIWH - Dämmung, weich Mineralwolle, _SIWH - Beton, Stahlbeton
AC_Pset_RenovationAndPhasing - Renovation Status: Existing
Material Properties - _SIWH - MW Vormauerziegel, ThermalConductivity: 0.109; _SIWH - MW Vormauerziegel, SpecificHeatCapacity: 920 J/kg/K; _SIWH - MW Vormauerziegel, MassDensity: 600 kg/m3; _SIWH - MW Vormauerziegel, Embodied Energy: 6 (MJ/kg); _SIWH - MW Vormauerziegel, Embodied Carbon: 0.48 (kgCO₂/kg); _SIWH - MW Vormauerziegel, Name: _SIWH - MW Vormauerziegel; _SIWH - MW Vormauerziegel, Participates in Collision Detection: yes; _SIWH - Luftschicht vertikal, ThermalConductivity: 0.16; _SIWH - Luftschicht vertikal, SpecificHeatCapacity: 1008 J/kg/K; _SIWH - Luftschicht vertikal, MassDensity: 1.2 kg/m3; _SIWH - Luftschicht vertikal, Embodied Energy: 0 (MJ/kg); _SIWH - Luftschicht vertikal, Embodied Carbon: 0 (kgCO₂/kg); _SIWH - Luftschicht vertikal, Name: _SIWH - Luftschicht vertikal; _SIWH - Luftschicht vertikal, Participates in Collision Detection: no; _SIWH - Dämmung, weich Mineralwolle, ThermalConductivity: 0.037; _SIWH - Dämmung, weich Mineralwolle, SpecificHeatCapacity: 840 J/kg/K; _SIWH - Dämmung, weich Mineralwolle, MassDensity: 40 kg/m3; _SIWH - Dämmung, weich Mineralwolle, Embodied Energy: 14.3 (MJ/kg); _SIWH - Dämmung, weich Mineralwolle, Embodied Carbon: 1.08 (kgCO₂/kg); _SIWH - Dämmung, weich Mineralwolle, Name: _SIWH - Dämmung, weich Mineralwolle; _SIWH - Dämmung, weich Mineralwolle, Participates in Collision Detection: yes; _SIWH - Beton, Stahlbeton, ThermalConductivity: 1.35; _SIWH - Beton, Stahlbeton, SpecificHeatCapacity: 1000 J/kg/K; _SIWH - Beton, Stahlbeton, MassDensity: 2000 kg/m3; _SIWH - Beton, Stahlbeton, Embodied Energy: 0.78 (MJ/kg); _SIWH - Beton, Stahlbeton, Embodied Carbon: 0.113 (kgCO₂/kg); _SIWH - Beton, Stahlbeton, Name: _SIWH - Beton, Stahlbeton; _SIWH - Beton, Stahlbeton, Participates in Collision Detection: yes
Pset_WallCommon - IsExternal: yes; LoadBearing: yes

# IfcWall: _SIWH - Sturz Außenwand EG 555 x 330 (5)
In: Erdgeschoss
Classification: Wand (Archicad Klassifizierung)
Pset_WallCommon - IsExternal: yes; LoadBearing: yes
AC_Pset_RenovationAndPhasing - Renovation Status: Existing
Material Properties - _SIWH - Beton, Stahlbeton, ThermalConductivity: 1.35; _SIWH - Beton, Stahlbeton, SpecificHeatCapacity: 1000 J/kg/K; _SIWH - Beton, Stahlbeton, MassDensity: 2000 kg/m3; _SIWH - Beton, Stahlbeton, Embodied Energy: 0.78 (MJ/kg); _SIWH - Beton, Stahlbeton, Embodied Carbon: 0.113 (kgCO₂/kg); _SIWH - Beton, Stahlbeton, Name: _SIWH - Beton, Stahlbeton; _SIWH - Beton, Stahlbeton, Participates in Collision Detection: yes; _SIWH - Dämmung, weich Mineralwolle, ThermalConductivity: 0.037; _SIWH - Dämmung, weich Mineralwolle, SpecificHeatCapacity: 840 J/kg/K; _SIWH - Dämmung, weich Mineralwolle, MassDensity: 40 kg/m3; _SIWH - Dämmung, weich Mineralwolle, Embodied Energy: 14.3 (MJ/kg); _SIWH - Dämmung, weich Mineralwolle, Embodied Carbon: 1.08 (kgCO₂/kg); _SIWH - Dämmung, weich Mineralwolle, Name: _SIWH - Dämmung, weich Mineralwolle; _SIWH - Dämmung, weich Mineralwolle, Participates in Collision Detection: yes; _SIWH - Luftschicht vertikal, ThermalConductivity: 0.16; _SIWH - Luftschicht vertikal, SpecificHeatCapacity: 1008 J/kg/K; _SIWH - Luftschicht vertikal, MassDensity: 1.2 kg/m3; _SIWH - Luftschicht vertikal, Embodied Energy: 0 (MJ/kg); _SIWH - Luftschicht vertikal, Embodied Carbon: 0 (kgCO₂/kg); _SIWH - Luftschicht vertikal, Name: _SIWH - Luftschicht vertikal; _SIWH - Luftschicht vertikal, Participates in Collision Detection: no; _SIWH - MW Vormauerziegel, ThermalConductivity: 0.109; _SIWH - MW Vormauerziegel, SpecificHeatCapacity: 920 J/kg/K; _SIWH - MW Vormauerziegel, MassDensity: 600 kg/m3; _SIWH - MW Vormauerziegel, Embodied Energy: 6 (MJ/kg); _SIWH - MW Vormauerziegel, Embodied Carbon: 0.48 (kgCO₂/kg); _SIWH - MW Vormauerziegel, Name: _SIWH - MW Vormauerziegel; _SIWH - MW Vormauerziegel, Participates in Collision Detection: yes
Name | Material
A-Wand010 | _SIWH - Beton, Stahlbeton, _SIWH - Dämmung, weich Mineralwolle, _SIWH - Luftschicht vertikal, _SIWH - MW Vormauerziegel
A-Wand009 | _SIWH - Beton, Stahlbeton, _SIWH - Dämmung, weich Mineralwolle, _SIWH - Luftschicht vertikal, _SIWH - MW Vormauerziegel
A-Wand016 | _SIWH - Beton, Stahlbeton, _SIWH - Dämmung, weich Mineralwolle, _SIWH - Luftschicht vertikal, _SIWH - MW Vormauerziegel
A-Wand041 | _SIWH - MW Vormauerziegel, _SIWH - Luftschicht vertikal, _SIWH - Dämmung, weich Mineralwolle, _SIWH - Beton, Stahlbeton
A-Wand013 | _SIWH - MW Vormauerziegel, _SIWH - Luftschicht vertikal, _SIWH - Dämmung, weich Mineralwolle, _SIWH - Beton, Stahlbeton

# IfcWall: _SIWH - Sturz Außenwand EG Garage 615 x 280 (2)
In: Erdgeschoss
Classification: Wand (Archicad Klassifizierung); Material: _SIWH - MW Vormauerziegel, _SIWH - Luftschicht vertikal, _SIWH - Dämmung, weich Mineralwolle, _SIWH - Beton, Stahlbeton
AC_Pset_RenovationAndPhasing - Renovation Status: Existing
Pset_WallCommon - IsExternal: yes; LoadBearing: yes
Material Properties - _SIWH - MW Vormauerziegel, ThermalConductivity: 0.109; _SIWH - MW Vormauerziegel, SpecificHeatCapacity: 920 J/kg/K; _SIWH - MW Vormauerziegel, MassDensity: 600 kg/m3; _SIWH - MW Vormauerziegel, Embodied Energy: 6 (MJ/kg); _SIWH - MW Vormauerziegel, Embodied Carbon: 0.48 (kgCO₂/kg); _SIWH - MW Vormauerziegel, Name: _SIWH - MW Vormauerziegel; _SIWH - MW Vormauerziegel, Participates in Collision Detection: yes; _SIWH - Luftschicht vertikal, ThermalConductivity: 0.16; _SIWH - Luftschicht vertikal, SpecificHeatCapacity: 1008 J/kg/K; _SIWH - Luftschicht vertikal, MassDensity: 1.2 kg/m3; _SIWH - Luftschicht vertikal, Embodied Energy: 0 (MJ/kg); _SIWH - Luftschicht vertikal, Embodied Carbon: 0 (kgCO₂/kg); _SIWH - Luftschicht vertikal, Name: _SIWH - Luftschicht vertikal; _SIWH - Luftschicht vertikal, Participates in Collision Detection: no; _SIWH - Dämmung, weich Mineralwolle, ThermalConductivity: 0.037; _SIWH - Dämmung, weich Mineralwolle, SpecificHeatCapacity: 840 J/kg/K; _SIWH - Dämmung, weich Mineralwolle, MassDensity: 40 kg/m3; _SIWH - Dämmung, weich Mineralwolle, Embodied Energy: 14.3 (MJ/kg); _SIWH - Dämmung, weich Mineralwolle, Embodied Carbon: 1.08 (kgCO₂/kg); _SIWH - Dämmung, weich Mineralwolle, Name: _SIWH - Dämmung, weich Mineralwolle; _SIWH - Dämmung, weich Mineralwolle, Participates in Collision Detection: yes; _SIWH - Beton, Stahlbeton, ThermalConductivity: 1.35; _SIWH - Beton, Stahlbeton, SpecificHeatCapacity: 1000 J/kg/K; _SIWH - Beton, Stahlbeton, MassDensity: 2000 kg/m3; _SIWH - Beton, Stahlbeton, Embodied Energy: 0.78 (MJ/kg); _SIWH - Beton, Stahlbeton, Embodied Carbon: 0.113 (kgCO₂/kg); _SIWH - Beton, Stahlbeton, Name: _SIWH - Beton, Stahlbeton; _SIWH - Beton, Stahlbeton, Participates in Collision Detection: yes
Name
A-Wand019
A-Wand018

# IfcWall: _SIWH - Sturz Außenwand EG Vordach 555 x 280 (2)
In: Erdgeschoss
Classification: Wand (Archicad Klassifizierung)
AC_Pset_RenovationAndPhasing - Renovation Status: Existing
Pset_WallCommon - IsExternal: yes; LoadBearing: yes
Material Properties - _SIWH - Beton, Stahlbeton, ThermalConductivity: 1.35; _SIWH - Beton, Stahlbeton, SpecificHeatCapacity: 1000 J/kg/K; _SIWH - Beton, Stahlbeton, MassDensity: 2000 kg/m3; _SIWH - Beton, Stahlbeton, Embodied Energy: 0.78 (MJ/kg); _SIWH - Beton, Stahlbeton, Embodied Carbon: 0.113 (kgCO₂/kg); _SIWH - Beton, Stahlbeton, Name: _SIWH - Beton, Stahlbeton; _SIWH - Beton, Stahlbeton, Participates in Collision Detection: yes; _SIWH - Dämmung, weich Mineralwolle, ThermalConductivity: 0.037; _SIWH - Dämmung, weich Mineralwolle, SpecificHeatCapacity: 840 J/kg/K; _SIWH - Dämmung, weich Mineralwolle, MassDensity: 40 kg/m3; _SIWH - Dämmung, weich Mineralwolle, Embodied Energy: 14.3 (MJ/kg); _SIWH - Dämmung, weich Mineralwolle, Embodied Carbon: 1.08 (kgCO₂/kg); _SIWH - Dämmung, weich Mineralwolle, Name: _SIWH - Dämmung, weich Mineralwolle; _SIWH - Dämmung, weich Mineralwolle, Participates in Collision Detection: yes; _SIWH - Luftschicht vertikal, ThermalConductivity: 0.16; _SIWH - Luftschicht vertikal, SpecificHeatCapacity: 1008 J/kg/K; _SIWH - Luftschicht vertikal, MassDensity: 1.2 kg/m3; _SIWH - Luftschicht vertikal, Embodied Energy: 0 (MJ/kg); _SIWH - Luftschicht vertikal, Embodied Carbon: 0 (kgCO₂/kg); _SIWH - Luftschicht vertikal, Name: _SIWH - Luftschicht vertikal; _SIWH - Luftschicht vertikal, Participates in Collision Detection: no; _SIWH - MW Vormauerziegel, ThermalConductivity: 0.109; _SIWH - MW Vormauerziegel, SpecificHeatCapacity: 920 J/kg/K; _SIWH - MW Vormauerziegel, MassDensity: 600 kg/m3; _SIWH - MW Vormauerziegel, Embodied Energy: 6 (MJ/kg); _SIWH - MW Vormauerziegel, Embodied Carbon: 0.48 (kgCO₂/kg); _SIWH - MW Vormauerziegel, Name: _SIWH - MW Vormauerziegel; _SIWH - MW Vormauerziegel, Participates in Collision Detection: yes
Name | Material
A-Wand022 | _SIWH - Beton, Stahlbeton, _SIWH - Dämmung, weich Mineralwolle, _SIWH - Luftschicht vertikal, _SIWH - MW Vormauerziegel
A-Wand017 | _SIWH - MW Vormauerziegel, _SIWH - Luftschicht vertikal, _SIWH - Dämmung, weich Mineralwolle, _SIWH - Beton, Stahlbeton

# IfcWall: _SIWH - Terrasse Luftbalken 140 x 915 (2)
In: Staffelgeschoss
Classification: Wand (Archicad Klassifizierung); Material: _SIWH - Beton, Stahlbeton Fertigteil
AC_Pset_RenovationAndPhasing - Renovation Status: Existing
Pset_WallCommon - IsExternal: yes; LoadBearing: no
Material Properties - _SIWH - Beton, Stahlbeton Fertigteil, ThermalConductivity: 1.15; _SIWH - Beton, Stahlbeton Fertigteil, SpecificHeatCapacity: 1000 J/kg/K; _SIWH - Beton, Stahlbeton Fertigteil, MassDensity: 1800 kg/m3; _SIWH - Beton, Stahlbeton Fertigteil, Embodied Energy: 0.74 (MJ/kg); _SIWH - Beton, Stahlbeton Fertigteil, Embodied Carbon: 0.107 (kgCO₂/kg); _SIWH - Beton, Stahlbeton Fertigteil, Name: _SIWH - Beton, Stahlbeton Fertigteil; _SIWH - Beton, Stahlbeton Fertigteil, Participates in Collision Detection: yes

# IfcWall: _SIWH - WA | Perimeterdämmung 8 | 8cm 80, A-Wand029
In: Kellergeschoss
Classification: Wand (Archicad Klassifizierung); Material: _SIWH - Dämmung, Perimeterdämmung
AC_Pset_RenovationAndPhasing - Renovation Status: Existing
Pset_WallCommon - IsExternal: yes; LoadBearing: yes
Material Properties - _SIWH - Dämmung, Perimeterdämmung, ThermalConductivity: 0.046; _SIWH - Dämmung, Perimeterdämmung, SpecificHeatCapacity: 900 J/kg/K; _SIWH - Dämmung, Perimeterdämmung, MassDensity: 151.33 kg/m3; _SIWH - Dämmung, Perimeterdämmung, Embodied Energy: 13.5 (MJ/kg); _SIWH - Dämmung, Perimeterdämmung, Embodied Carbon: 0.9 (kgCO₂/kg); _SIWH - Dämmung, Perimeterdämmung, Name: _SIWH - Dämmung, Perimeterdämmung; _SIWH - Dämmung, Perimeterdämmung, Participates in Collision Detection: yes

# IfcWall: _SIWH - WA | Stb. 20+WD 18 | 38cm 380 (6)
Classification: Wand (Archicad Klassifizierung)
AC_Pset_RenovationAndPhasing - Renovation Status: Existing
Pset_WallCommon - IsExternal: yes; LoadBearing: yes
Material Properties - _SIWH - Dämmung, weich Mineralwolle, ThermalConductivity: 0.037; _SIWH - Dämmung, weich Mineralwolle, SpecificHeatCapacity: 840 J/kg/K; _SIWH - Dämmung, weich Mineralwolle, MassDensity: 40 kg/m3; _SIWH - Dämmung, weich Mineralwolle, Embodied Energy: 14.3 (MJ/kg); _SIWH - Dämmung, weich Mineralwolle, Embodied Carbon: 1.08 (kgCO₂/kg); _SIWH - Dämmung, weich Mineralwolle, Name: _SIWH - Dämmung, weich Mineralwolle; _SIWH - Dämmung, weich Mineralwolle, Participates in Collision Detection: yes; _SIWH - Beton, Stahlbeton, ThermalConductivity: 1.35; _SIWH - Beton, Stahlbeton, SpecificHeatCapacity: 1000 J/kg/K; _SIWH - Beton, Stahlbeton, MassDensity: 2000 kg/m3; _SIWH - Beton, Stahlbeton, Embodied Energy: 0.78 (MJ/kg); _SIWH - Beton, Stahlbeton, Embodied Carbon: 0.113 (kgCO₂/kg); _SIWH - Beton, Stahlbeton, Name: _SIWH - Beton, Stahlbeton; _SIWH - Beton, Stahlbeton, Participates in Collision Detection: yes
Name | In | Material
A-Wand021 | Erdgeschoss | _SIWH - Dämmung, weich Mineralwolle, _SIWH - Beton, Stahlbeton
A-Wand051 | Staffelgeschoss | _SIWH - Beton, Stahlbeton, _SIWH - Dämmung, weich Mineralwolle
A-Wand050 | Staffelgeschoss | _SIWH - Beton, Stahlbeton, _SIWH - Dämmung, weich Mineralwolle
A-Wand049 | Staffelgeschoss | _SIWH - Beton, Stahlbeton, _SIWH - Dämmung, weich Mineralwolle
A-Wand048 | Staffelgeschoss | _SIWH - Beton, Stahlbeton, _SIWH - Dämmung, weich Mineralwolle
A-Wand047 | Staffelgeschoss | _SIWH - Beton, Stahlbeton, _SIWH - Dämmung, weich Mineralwolle

# IfcWall: _SIWH - WA | Stb. 20+WD 18+LS 2+Verblender 11,5 | 51,5cm 515 (6)
Classification: Wand (Archicad Klassifizierung)
AC_Pset_RenovationAndPhasing - Renovation Status: Existing
Pset_WallCommon - IsExternal: yes; LoadBearing: yes
Material Properties - _SIWH - Beton, Stahlbeton, ThermalConductivity: 1.35; _SIWH - Beton, Stahlbeton, SpecificHeatCapacity: 1000 J/kg/K; _SIWH - Beton, Stahlbeton, MassDensity: 2000 kg/m3; _SIWH - Beton, Stahlbeton, Embodied Energy: 0.78 (MJ/kg); _SIWH - Beton, Stahlbeton, Embodied Carbon: 0.113 (kgCO₂/kg); _SIWH - Beton, Stahlbeton, Name: _SIWH - Beton, Stahlbeton; _SIWH - Beton, Stahlbeton, Participates in Collision Detection: yes; _SIWH - Dämmung, weich Mineralwolle, ThermalConductivity: 0.037; _SIWH - Dämmung, weich Mineralwolle, SpecificHeatCapacity: 840 J/kg/K; _SIWH - Dämmung, weich Mineralwolle, MassDensity: 40 kg/m3; _SIWH - Dämmung, weich Mineralwolle, Embodied Energy: 14.3 (MJ/kg); _SIWH - Dämmung, weich Mineralwolle, Embodied Carbon: 1.08 (kgCO₂/kg); _SIWH - Dämmung, weich Mineralwolle, Name: _SIWH - Dämmung, weich Mineralwolle; _SIWH - Dämmung, weich Mineralwolle, Participates in Collision Detection: yes; _SIWH - Luftschicht vertikal, ThermalConductivity: 0.16; _SIWH - Luftschicht vertikal, SpecificHeatCapacity: 1008 J/kg/K; _SIWH - Luftschicht vertikal, MassDensity: 1.2 kg/m3; _SIWH - Luftschicht vertikal, Embodied Energy: 0 (MJ/kg); _SIWH - Luftschicht vertikal, Embodied Carbon: 0 (kgCO₂/kg); _SIWH - Luftschicht vertikal, Name: _SIWH - Luftschicht vertikal; _SIWH - Luftschicht vertikal, Participates in Collision Detection: no; _SIWH - MW Vormauerziegel, ThermalConductivity: 0.109; _SIWH - MW Vormauerziegel, SpecificHeatCapacity: 920 J/kg/K; _SIWH - MW Vormauerziegel, MassDensity: 600 kg/m3; _SIWH - MW Vormauerziegel, Embodied Energy: 6 (MJ/kg); _SIWH - MW Vormauerziegel, Embodied Carbon: 0.48 (kgCO₂/kg); _SIWH - MW Vormauerziegel, Name: _SIWH - MW Vormauerziegel; _SIWH - MW Vormauerziegel, Participates in Collision Detection: yes
Name | In | Material
A-Wand001 | Erdgeschoss | _SIWH - Beton, Stahlbeton, _SIWH - Dämmung, weich Mineralwolle, _SIWH - Luftschicht vertikal, _SIWH - MW Vormauerziegel
A-Wand003 | Erdgeschoss | _SIWH - MW Vormauerziegel, _SIWH - Luftschicht vertikal, _SIWH - Dämmung, weich Mineralwolle, _SIWH - Beton, Stahlbeton
A-Wand043 | Staffelgeschoss | _SIWH - Beton, Stahlbeton, _SIWH - Dämmung, weich Mineralwolle, _SIWH - Luftschicht vertikal, _SIWH - MW Vormauerziegel
A-Wand044 | Staffelgeschoss | _SIWH - Beton, Stahlbeton, _SIWH - Dämmung, weich Mineralwolle, _SIWH - Luftschicht vertikal, _SIWH - MW Vormauerziegel
A-Wand045 | Staffelgeschoss | _SIWH - Beton, Stahlbeton, _SIWH - Dämmung, weich Mineralwolle, _SIWH - Luftschicht vertikal, _SIWH - MW Vormauerziegel
A-Wand046 | Staffelgeschoss | _SIWH - Beton, Stahlbeton, _SIWH - Dämmung, weich Mineralwolle, _SIWH - Luftschicht vertikal, _SIWH - MW Vormauerziegel

# IfcWall: _SIWH - WA | Stb. 24+WD 18 | 42cm 420 (6)
In: Erdgeschoss
Classification: Wand (Archicad Klassifizierung); Material: _SIWH - Beton, Stahlbeton, _SIWH - Dämmung, weich Mineralwolle
AC_Pset_RenovationAndPhasing - Renovation Status: Existing
Pset_WallCommon - IsExternal: yes; LoadBearing: yes
Material Properties - _SIWH - Beton, Stahlbeton, ThermalConductivity: 1.35; _SIWH - Beton, Stahlbeton, SpecificHeatCapacity: 1000 J/kg/K; _SIWH - Beton, Stahlbeton, MassDensity: 2000 kg/m3; _SIWH - Beton, Stahlbeton, Embodied Energy: 0.78 (MJ/kg); _SIWH - Beton, Stahlbeton, Embodied Carbon: 0.113 (kgCO₂/kg); _SIWH - Beton, Stahlbeton, Name: _SIWH - Beton, Stahlbeton; _SIWH - Beton, Stahlbeton, Participates in Collision Detection: yes; _SIWH - Dämmung, weich Mineralwolle, ThermalConductivity: 0.037; _SIWH - Dämmung, weich Mineralwolle, SpecificHeatCapacity: 840 J/kg/K; _SIWH - Dämmung, weich Mineralwolle, MassDensity: 40 kg/m3; _SIWH - Dämmung, weich Mineralwolle, Embodied Energy: 14.3 (MJ/kg); _SIWH - Dämmung, weich Mineralwolle, Embodied Carbon: 1.08 (kgCO₂/kg); _SIWH - Dämmung, weich Mineralwolle, Name: _SIWH - Dämmung, weich Mineralwolle; _SIWH - Dämmung, weich Mineralwolle, Participates in Collision Detection: yes
Name
A-Wand011
A-Wand008
A-Wand007
A-Wand014
A-Wand015
A-Wand012

# IfcWall: _SIWH - WA | Stb. 24+WD 18+LS 2+Verblender 11,5 | 55,5cm 555 (6)
In: Erdgeschoss
Classification: Wand (Archicad Klassifizierung); Material: _SIWH - Beton, Stahlbeton, _SIWH - Dämmung, weich Mineralwolle, _SIWH - Luftschicht vertikal, _SIWH - MW Vormauerziegel
AC_Pset_RenovationAndPhasing - Renovation Status: Existing
Pset_WallCommon - IsExternal: yes; LoadBearing: yes
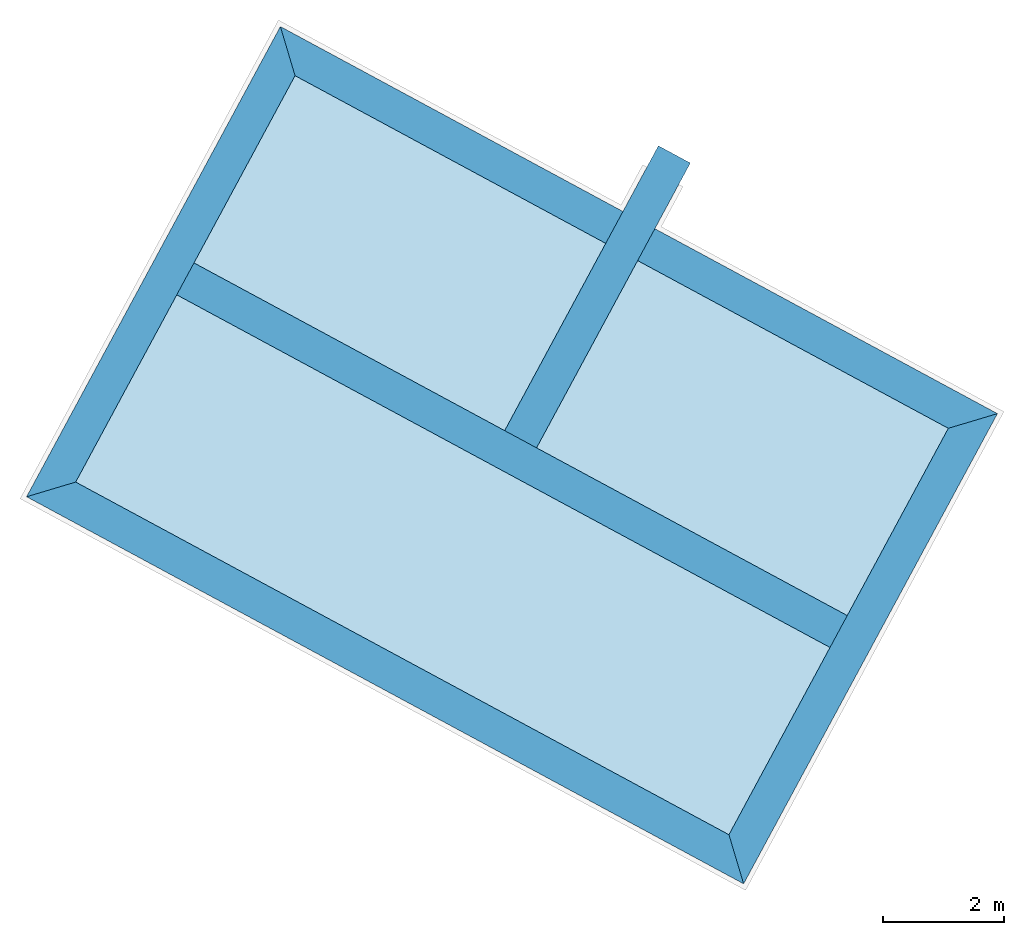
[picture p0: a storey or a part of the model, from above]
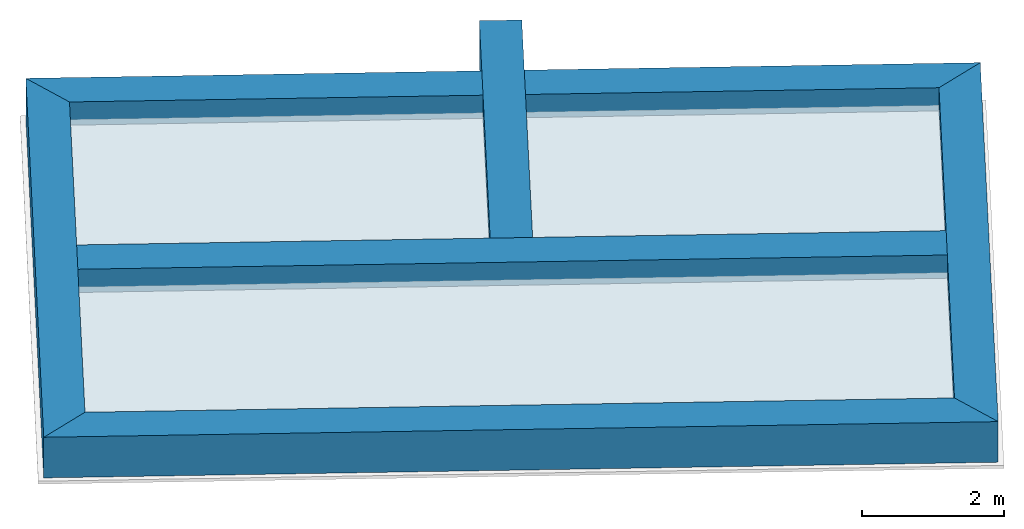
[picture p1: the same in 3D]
Properties of the parts of a building model (IFC2X3), part 3 of 3

# IfcWall: _SIWH - WA | Stb. 24+WD 18+LS 2+Verblender 11,5 | 55,5cm 555 (6)
Material Properties - _SIWH - Beton, Stahlbeton, ThermalConductivity: 1.35; _SIWH - Beton, Stahlbeton, SpecificHeatCapacity: 1000 J/kg/K; _SIWH - Beton, Stahlbeton, MassDensity: 2000 kg/m3; _SIWH - Beton, Stahlbeton, Embodied Energy: 0.78 (MJ/kg); _SIWH - Beton, Stahlbeton, Embodied Carbon: 0.113 (kgCO₂/kg); _SIWH - Beton, Stahlbeton, Name: _SIWH - Beton, Stahlbeton; _SIWH - Beton, Stahlbeton, Participates in Collision Detection: yes; _SIWH - Dämmung, weich Mineralwolle, ThermalConductivity: 0.037; _SIWH - Dämmung, weich Mineralwolle, SpecificHeatCapacity: 840 J/kg/K; _SIWH - Dämmung, weich Mineralwolle, MassDensity: 40 kg/m3; _SIWH - Dämmung, weich Mineralwolle, Embodied Energy: 14.3 (MJ/kg); _SIWH - Dämmung, weich Mineralwolle, Embodied Carbon: 1.08 (kgCO₂/kg); _SIWH - Dämmung, weich Mineralwolle, Name: _SIWH - Dämmung, weich Mineralwolle; _SIWH - Dämmung, weich Mineralwolle, Participates in Collision Detection: yes; _SIWH - Luftschicht vertikal, ThermalConductivity: 0.16; _SIWH - Luftschicht vertikal, SpecificHeatCapacity: 1008 J/kg/K; _SIWH - Luftschicht vertikal, MassDensity: 1.2 kg/m3; _SIWH - Luftschicht vertikal, Embodied Energy: 0 (MJ/kg); _SIWH - Luftschicht vertikal, Embodied Carbon: 0 (kgCO₂/kg); _SIWH - Luftschicht vertikal, Name: _SIWH - Luftschicht vertikal; _SIWH - Luftschicht vertikal, Participates in Collision Detection: no; _SIWH - MW Vormauerziegel, ThermalConductivity: 0.109; _SIWH - MW Vormauerziegel, SpecificHeatCapacity: 920 J/kg/K; _SIWH - MW Vormauerziegel, MassDensity: 600 kg/m3; _SIWH - MW Vormauerziegel, Embodied Energy: 6 (MJ/kg); _SIWH - MW Vormauerziegel, Embodied Carbon: 0.48 (kgCO₂/kg); _SIWH - MW Vormauerziegel, Name: _SIWH - MW Vormauerziegel; _SIWH - MW Vormauerziegel, Participates in Collision Detection: yes
Name
A-Wand042
A-Wand026
A-Wand027
A-Wand040
A-Wand004
A-Wand028

# IfcWall: _SIWH - WA | Stb. 30 | 30cm 300 (5)
In: Kellergeschoss
Classification: Wand (Archicad Klassifizierung); Material: _SIWH - Beton, Stahlbeton
AC_Pset_RenovationAndPhasing - Renovation Status: Existing
Pset_WallCommon - IsExternal: yes; LoadBearing: yes
Material Properties - _SIWH - Beton, Stahlbeton, ThermalConductivity: 1.35; _SIWH - Beton, Stahlbeton, SpecificHeatCapacity: 1000 J/kg/K; _SIWH - Beton, Stahlbeton, MassDensity: 2000 kg/m3; _SIWH - Beton, Stahlbeton, Embodied Energy: 0.78 (MJ/kg); _SIWH - Beton, Stahlbeton, Embodied Carbon: 0.113 (kgCO₂/kg); _SIWH - Beton, Stahlbeton, Name: _SIWH - Beton, Stahlbeton; _SIWH - Beton, Stahlbeton, Participates in Collision Detection: yes
Name
A-Wand000
A-Wand039
A-Wand002
A-Wand025
A-Wand024

# IfcWall: _SIWH - WA | Stb. 30+WD 18+LS 2+Verblender 11,5 | 61,5 615 (2)
In: Erdgeschoss
Classification: Wand (Archicad Klassifizierung); Material: _SIWH - Beton, Stahlbeton, _SIWH - Dämmung, weich Mineralwolle, _SIWH - Luftschicht vertikal, _SIWH - MW Vormauerziegel
AC_Pset_RenovationAndPhasing - Renovation Status: Existing
Pset_WallCommon - IsExternal: yes; LoadBearing: yes
Material Properties - _SIWH - Beton, Stahlbeton, ThermalConductivity: 1.35; _SIWH - Beton, Stahlbeton, SpecificHeatCapacity: 1000 J/kg/K; _SIWH - Beton, Stahlbeton, MassDensity: 2000 kg/m3; _SIWH - Beton, Stahlbeton, Embodied Energy: 0.78 (MJ/kg); _SIWH - Beton, Stahlbeton, Embodied Carbon: 0.113 (kgCO₂/kg); _SIWH - Beton, Stahlbeton, Name: _SIWH - Beton, Stahlbeton; _SIWH - Beton, Stahlbeton, Participates in Collision Detection: yes; _SIWH - Dämmung, weich Mineralwolle, ThermalConductivity: 0.037; _SIWH - Dämmung, weich Mineralwolle, SpecificHeatCapacity: 840 J/kg/K; _SIWH - Dämmung, weich Mineralwolle, MassDensity: 40 kg/m3; _SIWH - Dämmung, weich Mineralwolle, Embodied Energy: 14.3 (MJ/kg); _SIWH - Dämmung, weich Mineralwolle, Embodied Carbon: 1.08 (kgCO₂/kg); _SIWH - Dämmung, weich Mineralwolle, Name: _SIWH - Dämmung, weich Mineralwolle; _SIWH - Dämmung, weich Mineralwolle, Participates in Collision Detection: yes; _SIWH - Luftschicht vertikal, ThermalConductivity: 0.16; _SIWH - Luftschicht vertikal, SpecificHeatCapacity: 1008 J/kg/K; _SIWH - Luftschicht vertikal, MassDensity: 1.2 kg/m3; _SIWH - Luftschicht vertikal, Embodied Energy: 0 (MJ/kg); _SIWH - Luftschicht vertikal, Embodied Carbon: 0 (kgCO₂/kg); _SIWH - Luftschicht vertikal, Name: _SIWH - Luftschicht vertikal; _SIWH - Luftschicht vertikal, Participates in Collision Detection: no; _SIWH - MW Vormauerziegel, ThermalConductivity: 0.109; _SIWH - MW Vormauerziegel, SpecificHeatCapacity: 920 J/kg/K; _SIWH - MW Vormauerziegel, MassDensity: 600 kg/m3; _SIWH - MW Vormauerziegel, Embodied Energy: 6 (MJ/kg); _SIWH - MW Vormauerziegel, Embodied Carbon: 0.48 (kgCO₂/kg); _SIWH - MW Vormauerziegel, Name: _SIWH - MW Vormauerziegel; _SIWH - MW Vormauerziegel, Participates in Collision Detection: yes
Name
A-Wand005
A-Wand023

# IfcWall: _SIWH - WI | GK 2-lagig | 12,5cm 125 (5)
Classification: Wand (Archicad Klassifizierung); Material: _SIWH - Gipskarton (4), _SIWH - Dämmung, weich Mineralwolle
AC_Pset_RenovationAndPhasing - Renovation Status: Existing
Pset_WallCommon - IsExternal: no; LoadBearing: no
Material Properties - _SIWH - Gipskarton, ThermalConductivity: 0.25; _SIWH - Gipskarton, SpecificHeatCapacity: 1000 J/kg/K; _SIWH - Gipskarton, MassDensity: 900 kg/m3; _SIWH - Gipskarton, Embodied Energy: 6.75 (MJ/kg); _SIWH - Gipskarton, Embodied Carbon: 0.39 (kgCO₂/kg); _SIWH - Gipskarton, Name: _SIWH - Gipskarton; _SIWH - Gipskarton, Participates in Collision Detection: yes; _SIWH - Dämmung, weich Mineralwolle, ThermalConductivity: 0.037; _SIWH - Dämmung, weich Mineralwolle, SpecificHeatCapacity: 840 J/kg/K; _SIWH - Dämmung, weich Mineralwolle, MassDensity: 40 kg/m3; _SIWH - Dämmung, weich Mineralwolle, Embodied Energy: 14.3 (MJ/kg); _SIWH - Dämmung, weich Mineralwolle, Embodied Carbon: 1.08 (kgCO₂/kg); _SIWH - Dämmung, weich Mineralwolle, Name: _SIWH - Dämmung, weich Mineralwolle; _SIWH - Dämmung, weich Mineralwolle, Participates in Collision Detection: yes
Name | In
L-Wand025 | Erdgeschoss
L-Wand026 | Erdgeschoss
L-Wand044 | Erdgeschoss
L-Wand039 | Staffelgeschoss
L-Wand040 | Staffelgeschoss

# IfcWall: _SIWH - WI | GK 2-lagig | 15cm 150, L-Wand043
In: Erdgeschoss
Classification: Wand (Archicad Klassifizierung); Material: _SIWH - Gipskarton (4), _SIWH - Dämmung, weich Mineralwolle
AC_Pset_RenovationAndPhasing - Renovation Status: Existing
Material Properties - _SIWH - Gipskarton, ThermalConductivity: 0.25; _SIWH - Gipskarton, SpecificHeatCapacity: 1000 J/kg/K; _SIWH - Gipskarton, MassDensity: 900 kg/m3; _SIWH - Gipskarton, Embodied Energy: 6.75 (MJ/kg); _SIWH - Gipskarton, Embodied Carbon: 0.39 (kgCO₂/kg); _SIWH - Gipskarton, Name: _SIWH - Gipskarton; _SIWH - Gipskarton, Participates in Collision Detection: yes; _SIWH - Dämmung, weich Mineralwolle, ThermalConductivity: 0.037; _SIWH - Dämmung, weich Mineralwolle, SpecificHeatCapacity: 840 J/kg/K; _SIWH - Dämmung, weich Mineralwolle, MassDensity: 40 kg/m3; _SIWH - Dämmung, weich Mineralwolle, Embodied Energy: 14.3 (MJ/kg); _SIWH - Dämmung, weich Mineralwolle, Embodied Carbon: 1.08 (kgCO₂/kg); _SIWH - Dämmung, weich Mineralwolle, Name: _SIWH - Dämmung, weich Mineralwolle; _SIWH - Dämmung, weich Mineralwolle, Participates in Collision Detection: yes
Pset_WallCommon - IsExternal: no; LoadBearing: no

# IfcWall: _SIWH - WI | KS 17,5 | 17,5cm 175 (18)
Classification: Wand (Archicad Klassifizierung); Material: _SIWH - MW Kalksandstein
AC_Pset_RenovationAndPhasing - Renovation Status: Existing
Pset_WallCommon - IsExternal: no; LoadBearing: yes
Material Properties - _SIWH - MW Kalksandstein, ThermalConductivity: 0.93; _SIWH - MW Kalksandstein, SpecificHeatCapacity: 840 J/kg/K; _SIWH - MW Kalksandstein, MassDensity: 1800 kg/m3; _SIWH - MW Kalksandstein, Embodied Energy: 1.2 (MJ/kg); _SIWH - MW Kalksandstein, Embodied Carbon: 0.07 (kgCO₂/kg); _SIWH - MW Kalksandstein, Name: _SIWH - MW Kalksandstein; _SIWH - MW Kalksandstein, Participates in Collision Detection: yes
Name | In
I-Wand021 | Kellergeschoss
I-Wand023 | Kellergeschoss
I-Wand025 | Kellergeschoss
I-Wand026 | Kellergeschoss
I-Wand034 | Kellergeschoss
I-Wand029 | Kellergeschoss
I-Wand024 | Erdgeschoss
I-Wand027 | Erdgeschoss
I-Wand000 | Erdgeschoss
I-Wand001 | Erdgeschoss
I-Wand028 | Erdgeschoss
I-Wand030 | Erdgeschoss
I-Wand012 | Staffelgeschoss
I-Wand013 | Staffelgeschoss
I-Wand014 | Staffelgeschoss
I-Wand015 | Staffelgeschoss
I-Wand016 | Staffelgeschoss
I-Wand020 | Staffelgeschoss

# IfcWall: _SIWH - WI | KS 20 nichttragend | 20cm 200, L-Wand027
In: Erdgeschoss
Classification: Wand (Archicad Klassifizierung); Material: _SIWH - MW Kalksandstein, nichttragend
AC_Pset_RenovationAndPhasing - Renovation Status: Existing
Pset_WallCommon - IsExternal: no; LoadBearing: no
Material Properties - _SIWH - MW Kalksandstein, nichttragend, ThermalConductivity: 0.93; _SIWH - MW Kalksandstein, nichttragend, SpecificHeatCapacity: 840 J/kg/K; _SIWH - MW Kalksandstein, nichttragend, MassDensity: 1800 kg/m3; _SIWH - MW Kalksandstein, nichttragend, Embodied Energy: 1.2 (MJ/kg); _SIWH - MW Kalksandstein, nichttragend, Embodied Carbon: 0.07 (kgCO₂/kg); _SIWH - MW Kalksandstein, nichttragend, Name: _SIWH - MW Kalksandstein, nichttragend; _SIWH - MW Kalksandstein, nichttragend, Participates in Collision Detection: yes

# IfcWall: _SIWH - WI | Stb. 12 | 12cm 120, I-Wand022
In: Erdgeschoss
Classification: Wand (Archicad Klassifizierung); Material: _SIWH - Beton, Stahlbeton
AC_Pset_RenovationAndPhasing - Renovation Status: Existing
Pset_WallCommon - IsExternal: no; LoadBearing: yes
Material Properties - _SIWH - Beton, Stahlbeton, ThermalConductivity: 1.35; _SIWH - Beton, Stahlbeton, SpecificHeatCapacity: 1000 J/kg/K; _SIWH - Beton, Stahlbeton, MassDensity: 2000 kg/m3; _SIWH - Beton, Stahlbeton, Embodied Energy: 0.78 (MJ/kg); _SIWH - Beton, Stahlbeton, Embodied Carbon: 0.113 (kgCO₂/kg); _SIWH - Beton, Stahlbeton, Name: _SIWH - Beton, Stahlbeton; _SIWH - Beton, Stahlbeton, Participates in Collision Detection: yes

# IfcWall: _SIWH - WI | Stb. 20 | 20cm 200 (7)
Classification: Wand (Archicad Klassifizierung); Material: _SIWH - Beton, Stahlbeton
AC_Pset_RenovationAndPhasing - Renovation Status: Existing
Pset_WallCommon - IsExternal: no; LoadBearing: yes
Material Properties - _SIWH - Beton, Stahlbeton, ThermalConductivity: 1.35; _SIWH - Beton, Stahlbeton, SpecificHeatCapacity: 1000 J/kg/K; _SIWH - Beton, Stahlbeton, MassDensity: 2000 kg/m3; _SIWH - Beton, Stahlbeton, Embodied Energy: 0.78 (MJ/kg); _SIWH - Beton, Stahlbeton, Embodied Carbon: 0.113 (kgCO₂/kg); _SIWH - Beton, Stahlbeton, Name: _SIWH - Beton, Stahlbeton; _SIWH - Beton, Stahlbeton, Participates in Collision Detection: yes
Name | In
I-Wand004 | Erdgeschoss
I-Wand007 | Erdgeschoss
I-Wand005 | Erdgeschoss
I-Wand008 | Erdgeschoss
I-Wand009 | Erdgeschoss
I-Wand011 | Staffelgeschoss
I-Wand006 | Staffelgeschoss

# IfcWall: _SIWH - WI | Stb. 24 | 24cm 240 (3)
In: Erdgeschoss
Classification: Wand (Archicad Klassifizierung); Material: _SIWH - Beton, Stahlbeton
AC_Pset_RenovationAndPhasing - Renovation Status: Existing
Material Properties - _SIWH - Beton, Stahlbeton, ThermalConductivity: 1.35; _SIWH - Beton, Stahlbeton, SpecificHeatCapacity: 1000 J/kg/K; _SIWH - Beton, Stahlbeton, MassDensity: 2000 kg/m3; _SIWH - Beton, Stahlbeton, Embodied Energy: 0.78 (MJ/kg); _SIWH - Beton, Stahlbeton, Embodied Carbon: 0.113 (kgCO₂/kg); _SIWH - Beton, Stahlbeton, Name: _SIWH - Beton, Stahlbeton; _SIWH - Beton, Stahlbeton, Participates in Collision Detection: yes
Pset_WallCommon - LoadBearing: yes
Name | IsExternal
I-Wand002 | no
A-Wand006 | yes
I-Wand003 | no

# IfcWall: _SIWH - WI | Vorsatz-GK 2-lagig | 12,5cm 125 (4)
In: Erdgeschoss
Classification: Vorwand / Installationswand (Archicad Klassifizierung)
AC_Pset_RenovationAndPhasing - Renovation Status: Existing
Pset_WallCommon - IsExternal: no; LoadBearing: no
Material Properties - _SIWH - Installationswand, raumhoch, ThermalConductivity: 0.16; _SIWH - Installationswand, raumhoch, SpecificHeatCapacity: 1008 J/kg/K; _SIWH - Installationswand, raumhoch, MassDensity: 1.2 kg/m3; _SIWH - Installationswand, raumhoch, Embodied Energy: 0 (MJ/kg); _SIWH - Installationswand, raumhoch, Embodied Carbon: 0 (kgCO₂/kg); _SIWH - Installationswand, raumhoch, Name: _SIWH - Installationswand, raumhoch; _SIWH - Installationswand, raumhoch, Participates in Collision Detection: no; _SIWH - Gipskarton, ThermalConductivity: 0.25; _SIWH - Gipskarton, SpecificHeatCapacity: 1000 J/kg/K; _SIWH - Gipskarton, MassDensity: 900 kg/m3; _SIWH - Gipskarton, Embodied Energy: 6.75 (MJ/kg); _SIWH - Gipskarton, Embodied Carbon: 0.39 (kgCO₂/kg); _SIWH - Gipskarton, Name: _SIWH - Gipskarton; _SIWH - Gipskarton, Participates in Collision Detection: yes
Name | Material
L-Wand010 | _SIWH - Installationswand, raumhoch, _SIWH - Gipskarton (2)
L-Wand011 | _SIWH - Gipskarton (2), _SIWH - Installationswand, raumhoch
L-Wand041 | _SIWH - Installationswand, raumhoch, _SIWH - Gipskarton (2)
L-Wand035 | _SIWH - Gipskarton (2), _SIWH - Installationswand, raumhoch

# IfcWall: _SIWH - WI | Vorsatz-GK 2-lagig | 14cm 140, L-Wand024
In: Erdgeschoss
Classification: Vorwand / Installationswand (Archicad Klassifizierung); Material: _SIWH - Installationswand, raumhoch, _SIWH - Gipskarton (2)
AC_Pset_RenovationAndPhasing - Renovation Status: Existing
Pset_WallCommon - IsExternal: no; LoadBearing: no
Material Properties - _SIWH - Installationswand, raumhoch, ThermalConductivity: 0.16; _SIWH - Installationswand, raumhoch, SpecificHeatCapacity: 1008 J/kg/K; _SIWH - Installationswand, raumhoch, MassDensity: 1.2 kg/m3; _SIWH - Installationswand, raumhoch, Embodied Energy: 0 (MJ/kg); _SIWH - Installationswand, raumhoch, Embodied Carbon: 0 (kgCO₂/kg); _SIWH - Installationswand, raumhoch, Name: _SIWH - Installationswand, raumhoch; _SIWH - Installationswand, raumhoch, Participates in Collision Detection: no; _SIWH - Gipskarton, ThermalConductivity: 0.25; _SIWH - Gipskarton, SpecificHeatCapacity: 1000 J/kg/K; _SIWH - Gipskarton, MassDensity: 900 kg/m3; _SIWH - Gipskarton, Embodied Energy: 6.75 (MJ/kg); _SIWH - Gipskarton, Embodied Carbon: 0.39 (kgCO₂/kg); _SIWH - Gipskarton, Name: _SIWH - Gipskarton; _SIWH - Gipskarton, Participates in Collision Detection: yes

# IfcWall: _SIWH - WI | Vorsatz-GK 2-lagig | 15cm 150 (4)
Classification: Vorwand / Installationswand (Archicad Klassifizierung); Material: _SIWH - Gipskarton (4), _SIWH - Installationswand, raumhoch
AC_Pset_RenovationAndPhasing - Renovation Status: Existing
Pset_WallCommon - IsExternal: no; LoadBearing: no
Material Properties - _SIWH - Gipskarton, ThermalConductivity: 0.25; _SIWH - Gipskarton, SpecificHeatCapacity: 1000 J/kg/K; _SIWH - Gipskarton, MassDensity: 900 kg/m3; _SIWH - Gipskarton, Embodied Energy: 6.75 (MJ/kg); _SIWH - Gipskarton, Embodied Carbon: 0.39 (kgCO₂/kg); _SIWH - Gipskarton, Name: _SIWH - Gipskarton; _SIWH - Gipskarton, Participates in Collision Detection: yes; _SIWH - Installationswand, raumhoch, ThermalConductivity: 0.16; _SIWH - Installationswand, raumhoch, SpecificHeatCapacity: 1008 J/kg/K; _SIWH - Installationswand, raumhoch, MassDensity: 1.2 kg/m3; _SIWH - Installationswand, raumhoch, Embodied Energy: 0 (MJ/kg); _SIWH - Installationswand, raumhoch, Embodied Carbon: 0 (kgCO₂/kg); _SIWH - Installationswand, raumhoch, Name: _SIWH - Installationswand, raumhoch; _SIWH - Installationswand, raumhoch, Participates in Collision Detection: no
Name | In
L-Wand019 | Erdgeschoss
L-Wand018 | Erdgeschoss
L-Wand049 | Staffelgeschoss
L-Wand048 | Staffelgeschoss

# IfcWall: _SIWH - WI | Vorsatz-GK 2-lagig | 20cm 200 (3)
Classification: Vorwand / Installationswand (Archicad Klassifizierung)
Material Properties - _SIWH - Installationswand, raumhoch, ThermalConductivity: 0.16; _SIWH - Installationswand, raumhoch, SpecificHeatCapacity: 1008 J/kg/K; _SIWH - Installationswand, raumhoch, MassDensity: 1.2 kg/m3; _SIWH - Installationswand, raumhoch, Embodied Energy: 0 (MJ/kg); _SIWH - Installationswand, raumhoch, Embodied Carbon: 0 (kgCO₂/kg); _SIWH - Installationswand, raumhoch, Name: _SIWH - Installationswand, raumhoch; _SIWH - Installationswand, raumhoch, Participates in Collision Detection: no; _SIWH - Gipskarton, ThermalConductivity: 0.25; _SIWH - Gipskarton, SpecificHeatCapacity: 1000 J/kg/K; _SIWH - Gipskarton, MassDensity: 900 kg/m3; _SIWH - Gipskarton, Embodied Energy: 6.75 (MJ/kg); _SIWH - Gipskarton, Embodied Carbon: 0.39 (kgCO₂/kg); _SIWH - Gipskarton, Name: _SIWH - Gipskarton; _SIWH - Gipskarton, Participates in Collision Detection: yes
Pset_WallCommon - IsExternal: no; LoadBearing: no
AC_Pset_RenovationAndPhasing - Renovation Status: Existing
Name | In | Material
L-Wand028 | Erdgeschoss | _SIWH - Installationswand, raumhoch, _SIWH - Gipskarton (2)
L-Wand022 | Staffelgeschoss | _SIWH - Gipskarton (2), _SIWH - Installationswand, raumhoch
L-Wand023 | Staffelgeschoss | _SIWH - Installationswand, raumhoch, _SIWH - Gipskarton (2)

# IfcWall: _SIWH - WI | Vorsatz-GK 2-lagig | 7,5cm 75 (26)
Classification: Vorwand / Installationswand (Archicad Klassifizierung)
AC_Pset_RenovationAndPhasing - Renovation Status: Existing
Pset_WallCommon - IsExternal: no; LoadBearing: no
Material Properties - _SIWH - Gipskarton, ThermalConductivity: 0.25; _SIWH - Gipskarton, SpecificHeatCapacity: 1000 J/kg/K; _SIWH - Gipskarton, MassDensity: 900 kg/m3; _SIWH - Gipskarton, Embodied Energy: 6.75 (MJ/kg); _SIWH - Gipskarton, Embodied Carbon: 0.39 (kgCO₂/kg); _SIWH - Gipskarton, Name: _SIWH - Gipskarton; _SIWH - Gipskarton, Participates in Collision Detection: yes; _SIWH - Installationswand, raumhoch, ThermalConductivity: 0.16; _SIWH - Installationswand, raumhoch, SpecificHeatCapacity: 1008 J/kg/K; _SIWH - Installationswand, raumhoch, MassDensity: 1.2 kg/m3; _SIWH - Installationswand, raumhoch, Embodied Energy: 0 (MJ/kg); _SIWH - Installationswand, raumhoch, Embodied Carbon: 0 (kgCO₂/kg); _SIWH - Installationswand, raumhoch, Name: _SIWH - Installationswand, raumhoch; _SIWH - Installationswand, raumhoch, Participates in Collision Detection: no
Name | In | Material
L-Wand002 | Erdgeschoss | _SIWH - Gipskarton (2), _SIWH - Installationswand, raumhoch
L-Wand009 | Erdgeschoss | _SIWH - Installationswand, raumhoch, _SIWH - Gipskarton (2)
L-Wand008 | Erdgeschoss | _SIWH - Gipskarton (2), _SIWH - Installationswand, raumhoch
L-Wand015 | Erdgeschoss | _SIWH - Gipskarton (2), _SIWH - Installationswand, raumhoch
L-Wand005 | Erdgeschoss | _SIWH - Installationswand, raumhoch, _SIWH - Gipskarton (2)
L-Wand007 | Erdgeschoss | _SIWH - Installationswand, raumhoch, _SIWH - Gipskarton (2)
L-Wand006 | Erdgeschoss | _SIWH - Installationswand, raumhoch, _SIWH - Gipskarton (2)
L-Wand020 | Erdgeschoss | _SIWH - Gipskarton (2), _SIWH - Installationswand, raumhoch
L-Wand000 | Erdgeschoss | _SIWH - Gipskarton (2), _SIWH - Installationswand, raumhoch
L-Wand004 | Erdgeschoss | _SIWH - Installationswand, raumhoch, _SIWH - Gipskarton (2)
L-Wand012 | Erdgeschoss | _SIWH - Gipskarton (2), _SIWH - Installationswand, raumhoch
L-Wand034 | Erdgeschoss | _SIWH - Installationswand, raumhoch, _SIWH - Gipskarton (2)
L-Wand003 | Erdgeschoss | _SIWH - Gipskarton (2), _SIWH - Installationswand, raumhoch
L-Wand037 | Erdgeschoss | _SIWH - Installationswand, raumhoch, _SIWH - Gipskarton (2)
L-Wand013 | Erdgeschoss | _SIWH - Gipskarton (2), _SIWH - Installationswand, raumhoch
L-Wand014 | Erdgeschoss | _SIWH - Gipskarton (2), _SIWH - Installationswand, raumhoch
L-Wand001 | Erdgeschoss | _SIWH - Installationswand, raumhoch, _SIWH - Gipskarton (2)
L-Wand016 | Erdgeschoss | _SIWH - Gipskarton (2), _SIWH - Installationswand, raumhoch
L-Wand017 | Erdgeschoss | _SIWH - Gipskarton (2), _SIWH - Installationswand, raumhoch
L-Wand021 | Staffelgeschoss | _SIWH - Gipskarton (2), _SIWH - Installationswand, raumhoch
L-Wand030 | Staffelgeschoss | _SIWH - Gipskarton (2), _SIWH - Installationswand, raumhoch
L-Wand031 | Staffelgeschoss | _SIWH - Gipskarton (2), _SIWH - Installationswand, raumhoch
L-Wand029 | Staffelgeschoss | _SIWH - Gipskarton (2), _SIWH - Installationswand, raumhoch
L-Wand038 | Staffelgeschoss | _SIWH - Gipskarton (2), _SIWH - Installationswand, raumhoch
L-Wand032 | Staffelgeschoss | _SIWH - Gipskarton (2), _SIWH - Installationswand, raumhoch
L-Wand042 | Staffelgeschoss | _SIWH - Gipskarton (2), _SIWH - Installationswand, raumhoch

# IfcWindow: Dachfenster Glaskuppel 03 26, Objekt-0097
In: Staffelgeschoss
Type - ParameterTakesPrecedence: no; Sizeable: no
Classification: Lichtkuppel (Archicad Klassifizierung)
Pset_WindowCommon - IsExternal: yes
AC_Pset_RenovationAndPhasing - Renovation Status: Existing

# IfcWindow: _SIWH - Beton, Stahlbeton 85 (4)
In: Staffelgeschoss
Type - ParameterTakesPrecedence: no; Sizeable: no
Classification: Lichtkuppel (Archicad Klassifizierung); Material: _SIWH - Beton, Stahlbeton
AC_Pset_RenovationAndPhasing - Renovation Status: Existing
Pset_WindowCommon - IsExternal: yes
Material Properties - _SIWH - Beton, Stahlbeton, ThermalConductivity: 1.35; _SIWH - Beton, Stahlbeton, SpecificHeatCapacity: 1000 J/kg/K; _SIWH - Beton, Stahlbeton, MassDensity: 2000 kg/m3; _SIWH - Beton, Stahlbeton, Embodied Energy: 0.78 (MJ/kg); _SIWH - Beton, Stahlbeton, Embodied Carbon: 0.113 (kgCO₂/kg); _SIWH - Beton, Stahlbeton, Name: _SIWH - Beton, Stahlbeton; _SIWH - Beton, Stahlbeton, Participates in Collision Detection: yes
Name
A-Wand064
A-Wand062
A-Wand063
A-Wand061
